VERSION 5.8 ;
BUSBITCHARS "[]" ;
DIVIDERCHAR "/" ;
UNITS
    DATABASE MICRONS 1000 ;
END UNITS

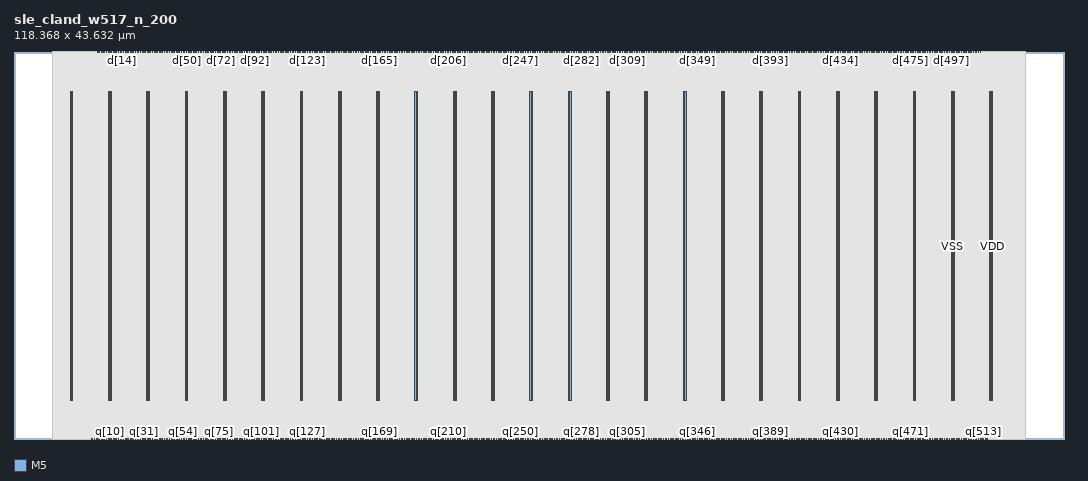
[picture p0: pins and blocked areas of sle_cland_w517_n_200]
MACRO sle_cland_w517_n_200
  FOREIGN sle_cland_w517_n_200 0 0 ;
  CLASS BLOCK ;
  SIZE 118.368 BY 43.632 ;
  PIN clk
    DIRECTION INPUT ;
    USE SIGNAL ;
    PORT
      LAYER M5 ;
        RECT  58.224 0 58.248 0.084 ;
    END
  END clk
  PIN d[0]
    DIRECTION INPUT ;
    USE SIGNAL ;
    PORT
      LAYER M5 ;
        RECT  9.84 43.548 9.864 43.632 ;
    END
  END d[0]
  PIN d[100]
    DIRECTION INPUT ;
    USE SIGNAL ;
    PORT
      LAYER M5 ;
        RECT  29.04 43.548 29.064 43.632 ;
    END
  END d[100]
  PIN d[101]
    DIRECTION INPUT ;
    USE SIGNAL ;
    PORT
      LAYER M5 ;
        RECT  28.656 43.548 28.68 43.632 ;
    END
  END d[101]
  PIN d[102]
    DIRECTION INPUT ;
    USE SIGNAL ;
    PORT
      LAYER M5 ;
        RECT  29.232 43.548 29.256 43.632 ;
    END
  END d[102]
  PIN d[103]
    DIRECTION INPUT ;
    USE SIGNAL ;
    PORT
      LAYER M5 ;
        RECT  28.848 43.548 28.872 43.632 ;
    END
  END d[103]
  PIN d[104]
    DIRECTION INPUT ;
    USE SIGNAL ;
    PORT
      LAYER M5 ;
        RECT  29.424 43.548 29.448 43.632 ;
    END
  END d[104]
  PIN d[105]
    DIRECTION INPUT ;
    USE SIGNAL ;
    PORT
      LAYER M5 ;
        RECT  29.616 43.548 29.64 43.632 ;
    END
  END d[105]
  PIN d[106]
    DIRECTION INPUT ;
    USE SIGNAL ;
    PORT
      LAYER M5 ;
        RECT  29.808 43.548 29.832 43.632 ;
    END
  END d[106]
  PIN d[107]
    DIRECTION INPUT ;
    USE SIGNAL ;
    PORT
      LAYER M5 ;
        RECT  30 43.548 30.024 43.632 ;
    END
  END d[107]
  PIN d[108]
    DIRECTION INPUT ;
    USE SIGNAL ;
    PORT
      LAYER M5 ;
        RECT  30.192 43.548 30.216 43.632 ;
    END
  END d[108]
  PIN d[109]
    DIRECTION INPUT ;
    USE SIGNAL ;
    PORT
      LAYER M5 ;
        RECT  30.384 43.548 30.408 43.632 ;
    END
  END d[109]
  PIN d[10]
    DIRECTION INPUT ;
    USE SIGNAL ;
    PORT
      LAYER M5 ;
        RECT  11.568 43.548 11.592 43.632 ;
    END
  END d[10]
  PIN d[110]
    DIRECTION INPUT ;
    USE SIGNAL ;
    PORT
      LAYER M5 ;
        RECT  30.576 43.548 30.6 43.632 ;
    END
  END d[110]
  PIN d[111]
    DIRECTION INPUT ;
    USE SIGNAL ;
    PORT
      LAYER M5 ;
        RECT  30.768 43.548 30.792 43.632 ;
    END
  END d[111]
  PIN d[112]
    DIRECTION INPUT ;
    USE SIGNAL ;
    PORT
      LAYER M5 ;
        RECT  30.96 43.548 30.984 43.632 ;
    END
  END d[112]
  PIN d[113]
    DIRECTION INPUT ;
    USE SIGNAL ;
    PORT
      LAYER M5 ;
        RECT  31.152 43.548 31.176 43.632 ;
    END
  END d[113]
  PIN d[114]
    DIRECTION INPUT ;
    USE SIGNAL ;
    PORT
      LAYER M5 ;
        RECT  31.344 43.548 31.368 43.632 ;
    END
  END d[114]
  PIN d[115]
    DIRECTION INPUT ;
    USE SIGNAL ;
    PORT
      LAYER M5 ;
        RECT  31.536 43.548 31.56 43.632 ;
    END
  END d[115]
  PIN d[116]
    DIRECTION INPUT ;
    USE SIGNAL ;
    PORT
      LAYER M5 ;
        RECT  31.728 43.548 31.752 43.632 ;
    END
  END d[116]
  PIN d[117]
    DIRECTION INPUT ;
    USE SIGNAL ;
    PORT
      LAYER M5 ;
        RECT  31.92 43.548 31.944 43.632 ;
    END
  END d[117]
  PIN d[118]
    DIRECTION INPUT ;
    USE SIGNAL ;
    PORT
      LAYER M5 ;
        RECT  32.112 43.548 32.136 43.632 ;
    END
  END d[118]
  PIN d[119]
    DIRECTION INPUT ;
    USE SIGNAL ;
    PORT
      LAYER M5 ;
        RECT  32.304 43.548 32.328 43.632 ;
    END
  END d[119]
  PIN d[11]
    DIRECTION INPUT ;
    USE SIGNAL ;
    PORT
      LAYER M5 ;
        RECT  11.376 43.548 11.4 43.632 ;
    END
  END d[11]
  PIN d[120]
    DIRECTION INPUT ;
    USE SIGNAL ;
    PORT
      LAYER M5 ;
        RECT  32.496 43.548 32.52 43.632 ;
    END
  END d[120]
  PIN d[121]
    DIRECTION INPUT ;
    USE SIGNAL ;
    PORT
      LAYER M5 ;
        RECT  32.688 43.548 32.712 43.632 ;
    END
  END d[121]
  PIN d[122]
    DIRECTION INPUT ;
    USE SIGNAL ;
    PORT
      LAYER M5 ;
        RECT  32.88 43.548 32.904 43.632 ;
    END
  END d[122]
  PIN d[123]
    DIRECTION INPUT ;
    USE SIGNAL ;
    PORT
      LAYER M5 ;
        RECT  33.072 43.548 33.096 43.632 ;
    END
  END d[123]
  PIN d[124]
    DIRECTION INPUT ;
    USE SIGNAL ;
    PORT
      LAYER M5 ;
        RECT  33.264 43.548 33.288 43.632 ;
    END
  END d[124]
  PIN d[125]
    DIRECTION INPUT ;
    USE SIGNAL ;
    PORT
      LAYER M5 ;
        RECT  33.456 43.548 33.48 43.632 ;
    END
  END d[125]
  PIN d[126]
    DIRECTION INPUT ;
    USE SIGNAL ;
    PORT
      LAYER M5 ;
        RECT  33.648 43.548 33.672 43.632 ;
    END
  END d[126]
  PIN d[127]
    DIRECTION INPUT ;
    USE SIGNAL ;
    PORT
      LAYER M5 ;
        RECT  33.84 43.548 33.864 43.632 ;
    END
  END d[127]
  PIN d[128]
    DIRECTION INPUT ;
    USE SIGNAL ;
    PORT
      LAYER M5 ;
        RECT  34.032 43.548 34.056 43.632 ;
    END
  END d[128]
  PIN d[129]
    DIRECTION INPUT ;
    USE SIGNAL ;
    PORT
      LAYER M5 ;
        RECT  34.224 43.548 34.248 43.632 ;
    END
  END d[129]
  PIN d[12]
    DIRECTION INPUT ;
    USE SIGNAL ;
    PORT
      LAYER M5 ;
        RECT  11.76 43.548 11.784 43.632 ;
    END
  END d[12]
  PIN d[130]
    DIRECTION INPUT ;
    USE SIGNAL ;
    PORT
      LAYER M5 ;
        RECT  34.416 43.548 34.44 43.632 ;
    END
  END d[130]
  PIN d[131]
    DIRECTION INPUT ;
    USE SIGNAL ;
    PORT
      LAYER M5 ;
        RECT  34.608 43.548 34.632 43.632 ;
    END
  END d[131]
  PIN d[132]
    DIRECTION INPUT ;
    USE SIGNAL ;
    PORT
      LAYER M5 ;
        RECT  34.8 43.548 34.824 43.632 ;
    END
  END d[132]
  PIN d[133]
    DIRECTION INPUT ;
    USE SIGNAL ;
    PORT
      LAYER M5 ;
        RECT  34.992 43.548 35.016 43.632 ;
    END
  END d[133]
  PIN d[134]
    DIRECTION INPUT ;
    USE SIGNAL ;
    PORT
      LAYER M5 ;
        RECT  35.184 43.548 35.208 43.632 ;
    END
  END d[134]
  PIN d[135]
    DIRECTION INPUT ;
    USE SIGNAL ;
    PORT
      LAYER M5 ;
        RECT  35.376 43.548 35.4 43.632 ;
    END
  END d[135]
  PIN d[136]
    DIRECTION INPUT ;
    USE SIGNAL ;
    PORT
      LAYER M5 ;
        RECT  35.76 43.548 35.784 43.632 ;
    END
  END d[136]
  PIN d[137]
    DIRECTION INPUT ;
    USE SIGNAL ;
    PORT
      LAYER M5 ;
        RECT  35.568 43.548 35.592 43.632 ;
    END
  END d[137]
  PIN d[138]
    DIRECTION INPUT ;
    USE SIGNAL ;
    PORT
      LAYER M5 ;
        RECT  35.952 43.548 35.976 43.632 ;
    END
  END d[138]
  PIN d[139]
    DIRECTION INPUT ;
    USE SIGNAL ;
    PORT
      LAYER M5 ;
        RECT  36.144 43.548 36.168 43.632 ;
    END
  END d[139]
  PIN d[13]
    DIRECTION INPUT ;
    USE SIGNAL ;
    PORT
      LAYER M5 ;
        RECT  11.952 43.548 11.976 43.632 ;
    END
  END d[13]
  PIN d[140]
    DIRECTION INPUT ;
    USE SIGNAL ;
    PORT
      LAYER M5 ;
        RECT  36.336 43.548 36.36 43.632 ;
    END
  END d[140]
  PIN d[141]
    DIRECTION INPUT ;
    USE SIGNAL ;
    PORT
      LAYER M5 ;
        RECT  36.528 43.548 36.552 43.632 ;
    END
  END d[141]
  PIN d[142]
    DIRECTION INPUT ;
    USE SIGNAL ;
    PORT
      LAYER M5 ;
        RECT  36.72 43.548 36.744 43.632 ;
    END
  END d[142]
  PIN d[143]
    DIRECTION INPUT ;
    USE SIGNAL ;
    PORT
      LAYER M5 ;
        RECT  36.912 43.548 36.936 43.632 ;
    END
  END d[143]
  PIN d[144]
    DIRECTION INPUT ;
    USE SIGNAL ;
    PORT
      LAYER M5 ;
        RECT  37.104 43.548 37.128 43.632 ;
    END
  END d[144]
  PIN d[145]
    DIRECTION INPUT ;
    USE SIGNAL ;
    PORT
      LAYER M5 ;
        RECT  37.296 43.548 37.32 43.632 ;
    END
  END d[145]
  PIN d[146]
    DIRECTION INPUT ;
    USE SIGNAL ;
    PORT
      LAYER M5 ;
        RECT  37.488 43.548 37.512 43.632 ;
    END
  END d[146]
  PIN d[147]
    DIRECTION INPUT ;
    USE SIGNAL ;
    PORT
      LAYER M5 ;
        RECT  37.872 43.548 37.896 43.632 ;
    END
  END d[147]
  PIN d[148]
    DIRECTION INPUT ;
    USE SIGNAL ;
    PORT
      LAYER M5 ;
        RECT  37.68 43.548 37.704 43.632 ;
    END
  END d[148]
  PIN d[149]
    DIRECTION INPUT ;
    USE SIGNAL ;
    PORT
      LAYER M5 ;
        RECT  38.064 43.548 38.088 43.632 ;
    END
  END d[149]
  PIN d[14]
    DIRECTION INPUT ;
    USE SIGNAL ;
    PORT
      LAYER M5 ;
        RECT  12.144 43.548 12.168 43.632 ;
    END
  END d[14]
  PIN d[150]
    DIRECTION INPUT ;
    USE SIGNAL ;
    PORT
      LAYER M5 ;
        RECT  38.64 43.548 38.664 43.632 ;
    END
  END d[150]
  PIN d[151]
    DIRECTION INPUT ;
    USE SIGNAL ;
    PORT
      LAYER M5 ;
        RECT  38.256 43.548 38.28 43.632 ;
    END
  END d[151]
  PIN d[152]
    DIRECTION INPUT ;
    USE SIGNAL ;
    PORT
      LAYER M5 ;
        RECT  38.832 43.548 38.856 43.632 ;
    END
  END d[152]
  PIN d[153]
    DIRECTION INPUT ;
    USE SIGNAL ;
    PORT
      LAYER M5 ;
        RECT  38.448 43.548 38.472 43.632 ;
    END
  END d[153]
  PIN d[154]
    DIRECTION INPUT ;
    USE SIGNAL ;
    PORT
      LAYER M5 ;
        RECT  39.024 43.548 39.048 43.632 ;
    END
  END d[154]
  PIN d[155]
    DIRECTION INPUT ;
    USE SIGNAL ;
    PORT
      LAYER M5 ;
        RECT  39.216 43.548 39.24 43.632 ;
    END
  END d[155]
  PIN d[156]
    DIRECTION INPUT ;
    USE SIGNAL ;
    PORT
      LAYER M5 ;
        RECT  39.408 43.548 39.432 43.632 ;
    END
  END d[156]
  PIN d[157]
    DIRECTION INPUT ;
    USE SIGNAL ;
    PORT
      LAYER M5 ;
        RECT  39.6 43.548 39.624 43.632 ;
    END
  END d[157]
  PIN d[158]
    DIRECTION INPUT ;
    USE SIGNAL ;
    PORT
      LAYER M5 ;
        RECT  39.792 43.548 39.816 43.632 ;
    END
  END d[158]
  PIN d[159]
    DIRECTION INPUT ;
    USE SIGNAL ;
    PORT
      LAYER M5 ;
        RECT  39.984 43.548 40.008 43.632 ;
    END
  END d[159]
  PIN d[15]
    DIRECTION INPUT ;
    USE SIGNAL ;
    PORT
      LAYER M5 ;
        RECT  12.336 43.548 12.36 43.632 ;
    END
  END d[15]
  PIN d[160]
    DIRECTION INPUT ;
    USE SIGNAL ;
    PORT
      LAYER M5 ;
        RECT  40.176 43.548 40.2 43.632 ;
    END
  END d[160]
  PIN d[161]
    DIRECTION INPUT ;
    USE SIGNAL ;
    PORT
      LAYER M5 ;
        RECT  40.368 43.548 40.392 43.632 ;
    END
  END d[161]
  PIN d[162]
    DIRECTION INPUT ;
    USE SIGNAL ;
    PORT
      LAYER M5 ;
        RECT  40.56 43.548 40.584 43.632 ;
    END
  END d[162]
  PIN d[163]
    DIRECTION INPUT ;
    USE SIGNAL ;
    PORT
      LAYER M5 ;
        RECT  40.752 43.548 40.776 43.632 ;
    END
  END d[163]
  PIN d[164]
    DIRECTION INPUT ;
    USE SIGNAL ;
    PORT
      LAYER M5 ;
        RECT  40.944 43.548 40.968 43.632 ;
    END
  END d[164]
  PIN d[165]
    DIRECTION INPUT ;
    USE SIGNAL ;
    PORT
      LAYER M5 ;
        RECT  41.136 43.548 41.16 43.632 ;
    END
  END d[165]
  PIN d[166]
    DIRECTION INPUT ;
    USE SIGNAL ;
    PORT
      LAYER M5 ;
        RECT  41.328 43.548 41.352 43.632 ;
    END
  END d[166]
  PIN d[167]
    DIRECTION INPUT ;
    USE SIGNAL ;
    PORT
      LAYER M5 ;
        RECT  41.52 43.548 41.544 43.632 ;
    END
  END d[167]
  PIN d[168]
    DIRECTION INPUT ;
    USE SIGNAL ;
    PORT
      LAYER M5 ;
        RECT  41.712 43.548 41.736 43.632 ;
    END
  END d[168]
  PIN d[169]
    DIRECTION INPUT ;
    USE SIGNAL ;
    PORT
      LAYER M5 ;
        RECT  41.904 43.548 41.928 43.632 ;
    END
  END d[169]
  PIN d[16]
    DIRECTION INPUT ;
    USE SIGNAL ;
    PORT
      LAYER M5 ;
        RECT  12.528 43.548 12.552 43.632 ;
    END
  END d[16]
  PIN d[170]
    DIRECTION INPUT ;
    USE SIGNAL ;
    PORT
      LAYER M5 ;
        RECT  42.096 43.548 42.12 43.632 ;
    END
  END d[170]
  PIN d[171]
    DIRECTION INPUT ;
    USE SIGNAL ;
    PORT
      LAYER M5 ;
        RECT  42.288 43.548 42.312 43.632 ;
    END
  END d[171]
  PIN d[172]
    DIRECTION INPUT ;
    USE SIGNAL ;
    PORT
      LAYER M5 ;
        RECT  42.48 43.548 42.504 43.632 ;
    END
  END d[172]
  PIN d[173]
    DIRECTION INPUT ;
    USE SIGNAL ;
    PORT
      LAYER M5 ;
        RECT  42.672 43.548 42.696 43.632 ;
    END
  END d[173]
  PIN d[174]
    DIRECTION INPUT ;
    USE SIGNAL ;
    PORT
      LAYER M5 ;
        RECT  42.864 43.548 42.888 43.632 ;
    END
  END d[174]
  PIN d[175]
    DIRECTION INPUT ;
    USE SIGNAL ;
    PORT
      LAYER M5 ;
        RECT  43.056 43.548 43.08 43.632 ;
    END
  END d[175]
  PIN d[176]
    DIRECTION INPUT ;
    USE SIGNAL ;
    PORT
      LAYER M5 ;
        RECT  43.248 43.548 43.272 43.632 ;
    END
  END d[176]
  PIN d[177]
    DIRECTION INPUT ;
    USE SIGNAL ;
    PORT
      LAYER M5 ;
        RECT  43.44 43.548 43.464 43.632 ;
    END
  END d[177]
  PIN d[178]
    DIRECTION INPUT ;
    USE SIGNAL ;
    PORT
      LAYER M5 ;
        RECT  43.632 43.548 43.656 43.632 ;
    END
  END d[178]
  PIN d[179]
    DIRECTION INPUT ;
    USE SIGNAL ;
    PORT
      LAYER M5 ;
        RECT  43.824 43.548 43.848 43.632 ;
    END
  END d[179]
  PIN d[17]
    DIRECTION INPUT ;
    USE SIGNAL ;
    PORT
      LAYER M5 ;
        RECT  12.72 43.548 12.744 43.632 ;
    END
  END d[17]
  PIN d[180]
    DIRECTION INPUT ;
    USE SIGNAL ;
    PORT
      LAYER M5 ;
        RECT  44.016 43.548 44.04 43.632 ;
    END
  END d[180]
  PIN d[181]
    DIRECTION INPUT ;
    USE SIGNAL ;
    PORT
      LAYER M5 ;
        RECT  44.208 43.548 44.232 43.632 ;
    END
  END d[181]
  PIN d[182]
    DIRECTION INPUT ;
    USE SIGNAL ;
    PORT
      LAYER M5 ;
        RECT  44.4 43.548 44.424 43.632 ;
    END
  END d[182]
  PIN d[183]
    DIRECTION INPUT ;
    USE SIGNAL ;
    PORT
      LAYER M5 ;
        RECT  44.592 43.548 44.616 43.632 ;
    END
  END d[183]
  PIN d[184]
    DIRECTION INPUT ;
    USE SIGNAL ;
    PORT
      LAYER M5 ;
        RECT  44.784 43.548 44.808 43.632 ;
    END
  END d[184]
  PIN d[185]
    DIRECTION INPUT ;
    USE SIGNAL ;
    PORT
      LAYER M5 ;
        RECT  44.976 43.548 45 43.632 ;
    END
  END d[185]
  PIN d[186]
    DIRECTION INPUT ;
    USE SIGNAL ;
    PORT
      LAYER M5 ;
        RECT  45.36 43.548 45.384 43.632 ;
    END
  END d[186]
  PIN d[187]
    DIRECTION INPUT ;
    USE SIGNAL ;
    PORT
      LAYER M5 ;
        RECT  45.168 43.548 45.192 43.632 ;
    END
  END d[187]
  PIN d[188]
    DIRECTION INPUT ;
    USE SIGNAL ;
    PORT
      LAYER M5 ;
        RECT  45.552 43.548 45.576 43.632 ;
    END
  END d[188]
  PIN d[189]
    DIRECTION INPUT ;
    USE SIGNAL ;
    PORT
      LAYER M5 ;
        RECT  45.744 43.548 45.768 43.632 ;
    END
  END d[189]
  PIN d[18]
    DIRECTION INPUT ;
    USE SIGNAL ;
    PORT
      LAYER M5 ;
        RECT  12.912 43.548 12.936 43.632 ;
    END
  END d[18]
  PIN d[190]
    DIRECTION INPUT ;
    USE SIGNAL ;
    PORT
      LAYER M5 ;
        RECT  45.936 43.548 45.96 43.632 ;
    END
  END d[190]
  PIN d[191]
    DIRECTION INPUT ;
    USE SIGNAL ;
    PORT
      LAYER M5 ;
        RECT  46.128 43.548 46.152 43.632 ;
    END
  END d[191]
  PIN d[192]
    DIRECTION INPUT ;
    USE SIGNAL ;
    PORT
      LAYER M5 ;
        RECT  46.32 43.548 46.344 43.632 ;
    END
  END d[192]
  PIN d[193]
    DIRECTION INPUT ;
    USE SIGNAL ;
    PORT
      LAYER M5 ;
        RECT  46.512 43.548 46.536 43.632 ;
    END
  END d[193]
  PIN d[194]
    DIRECTION INPUT ;
    USE SIGNAL ;
    PORT
      LAYER M5 ;
        RECT  46.704 43.548 46.728 43.632 ;
    END
  END d[194]
  PIN d[195]
    DIRECTION INPUT ;
    USE SIGNAL ;
    PORT
      LAYER M5 ;
        RECT  46.896 43.548 46.92 43.632 ;
    END
  END d[195]
  PIN d[196]
    DIRECTION INPUT ;
    USE SIGNAL ;
    PORT
      LAYER M5 ;
        RECT  47.088 43.548 47.112 43.632 ;
    END
  END d[196]
  PIN d[197]
    DIRECTION INPUT ;
    USE SIGNAL ;
    PORT
      LAYER M5 ;
        RECT  47.472 43.548 47.496 43.632 ;
    END
  END d[197]
  PIN d[198]
    DIRECTION INPUT ;
    USE SIGNAL ;
    PORT
      LAYER M5 ;
        RECT  47.28 43.548 47.304 43.632 ;
    END
  END d[198]
  PIN d[199]
    DIRECTION INPUT ;
    USE SIGNAL ;
    PORT
      LAYER M5 ;
        RECT  47.664 43.548 47.688 43.632 ;
    END
  END d[199]
  PIN d[19]
    DIRECTION INPUT ;
    USE SIGNAL ;
    PORT
      LAYER M5 ;
        RECT  13.104 43.548 13.128 43.632 ;
    END
  END d[19]
  PIN d[1]
    DIRECTION INPUT ;
    USE SIGNAL ;
    PORT
      LAYER M5 ;
        RECT  9.456 43.548 9.48 43.632 ;
    END
  END d[1]
  PIN d[200]
    DIRECTION INPUT ;
    USE SIGNAL ;
    PORT
      LAYER M5 ;
        RECT  48.24 43.548 48.264 43.632 ;
    END
  END d[200]
  PIN d[201]
    DIRECTION INPUT ;
    USE SIGNAL ;
    PORT
      LAYER M5 ;
        RECT  47.856 43.548 47.88 43.632 ;
    END
  END d[201]
  PIN d[202]
    DIRECTION INPUT ;
    USE SIGNAL ;
    PORT
      LAYER M5 ;
        RECT  48.432 43.548 48.456 43.632 ;
    END
  END d[202]
  PIN d[203]
    DIRECTION INPUT ;
    USE SIGNAL ;
    PORT
      LAYER M5 ;
        RECT  48.048 43.548 48.072 43.632 ;
    END
  END d[203]
  PIN d[204]
    DIRECTION INPUT ;
    USE SIGNAL ;
    PORT
      LAYER M5 ;
        RECT  48.624 43.548 48.648 43.632 ;
    END
  END d[204]
  PIN d[205]
    DIRECTION INPUT ;
    USE SIGNAL ;
    PORT
      LAYER M5 ;
        RECT  48.816 43.548 48.84 43.632 ;
    END
  END d[205]
  PIN d[206]
    DIRECTION INPUT ;
    USE SIGNAL ;
    PORT
      LAYER M5 ;
        RECT  49.008 43.548 49.032 43.632 ;
    END
  END d[206]
  PIN d[207]
    DIRECTION INPUT ;
    USE SIGNAL ;
    PORT
      LAYER M5 ;
        RECT  49.2 43.548 49.224 43.632 ;
    END
  END d[207]
  PIN d[208]
    DIRECTION INPUT ;
    USE SIGNAL ;
    PORT
      LAYER M5 ;
        RECT  49.392 43.548 49.416 43.632 ;
    END
  END d[208]
  PIN d[209]
    DIRECTION INPUT ;
    USE SIGNAL ;
    PORT
      LAYER M5 ;
        RECT  49.584 43.548 49.608 43.632 ;
    END
  END d[209]
  PIN d[20]
    DIRECTION INPUT ;
    USE SIGNAL ;
    PORT
      LAYER M5 ;
        RECT  13.296 43.548 13.32 43.632 ;
    END
  END d[20]
  PIN d[210]
    DIRECTION INPUT ;
    USE SIGNAL ;
    PORT
      LAYER M5 ;
        RECT  49.776 43.548 49.8 43.632 ;
    END
  END d[210]
  PIN d[211]
    DIRECTION INPUT ;
    USE SIGNAL ;
    PORT
      LAYER M5 ;
        RECT  49.968 43.548 49.992 43.632 ;
    END
  END d[211]
  PIN d[212]
    DIRECTION INPUT ;
    USE SIGNAL ;
    PORT
      LAYER M5 ;
        RECT  50.16 43.548 50.184 43.632 ;
    END
  END d[212]
  PIN d[213]
    DIRECTION INPUT ;
    USE SIGNAL ;
    PORT
      LAYER M5 ;
        RECT  50.352 43.548 50.376 43.632 ;
    END
  END d[213]
  PIN d[214]
    DIRECTION INPUT ;
    USE SIGNAL ;
    PORT
      LAYER M5 ;
        RECT  50.544 43.548 50.568 43.632 ;
    END
  END d[214]
  PIN d[215]
    DIRECTION INPUT ;
    USE SIGNAL ;
    PORT
      LAYER M5 ;
        RECT  50.736 43.548 50.76 43.632 ;
    END
  END d[215]
  PIN d[216]
    DIRECTION INPUT ;
    USE SIGNAL ;
    PORT
      LAYER M5 ;
        RECT  50.928 43.548 50.952 43.632 ;
    END
  END d[216]
  PIN d[217]
    DIRECTION INPUT ;
    USE SIGNAL ;
    PORT
      LAYER M5 ;
        RECT  51.12 43.548 51.144 43.632 ;
    END
  END d[217]
  PIN d[218]
    DIRECTION INPUT ;
    USE SIGNAL ;
    PORT
      LAYER M5 ;
        RECT  51.312 43.548 51.336 43.632 ;
    END
  END d[218]
  PIN d[219]
    DIRECTION INPUT ;
    USE SIGNAL ;
    PORT
      LAYER M5 ;
        RECT  51.504 43.548 51.528 43.632 ;
    END
  END d[219]
  PIN d[21]
    DIRECTION INPUT ;
    USE SIGNAL ;
    PORT
      LAYER M5 ;
        RECT  13.488 43.548 13.512 43.632 ;
    END
  END d[21]
  PIN d[220]
    DIRECTION INPUT ;
    USE SIGNAL ;
    PORT
      LAYER M5 ;
        RECT  51.696 43.548 51.72 43.632 ;
    END
  END d[220]
  PIN d[221]
    DIRECTION INPUT ;
    USE SIGNAL ;
    PORT
      LAYER M5 ;
        RECT  51.888 43.548 51.912 43.632 ;
    END
  END d[221]
  PIN d[222]
    DIRECTION INPUT ;
    USE SIGNAL ;
    PORT
      LAYER M5 ;
        RECT  52.08 43.548 52.104 43.632 ;
    END
  END d[222]
  PIN d[223]
    DIRECTION INPUT ;
    USE SIGNAL ;
    PORT
      LAYER M5 ;
        RECT  52.272 43.548 52.296 43.632 ;
    END
  END d[223]
  PIN d[224]
    DIRECTION INPUT ;
    USE SIGNAL ;
    PORT
      LAYER M5 ;
        RECT  52.464 43.548 52.488 43.632 ;
    END
  END d[224]
  PIN d[225]
    DIRECTION INPUT ;
    USE SIGNAL ;
    PORT
      LAYER M5 ;
        RECT  52.656 43.548 52.68 43.632 ;
    END
  END d[225]
  PIN d[226]
    DIRECTION INPUT ;
    USE SIGNAL ;
    PORT
      LAYER M5 ;
        RECT  52.848 43.548 52.872 43.632 ;
    END
  END d[226]
  PIN d[227]
    DIRECTION INPUT ;
    USE SIGNAL ;
    PORT
      LAYER M5 ;
        RECT  53.04 43.548 53.064 43.632 ;
    END
  END d[227]
  PIN d[228]
    DIRECTION INPUT ;
    USE SIGNAL ;
    PORT
      LAYER M5 ;
        RECT  53.232 43.548 53.256 43.632 ;
    END
  END d[228]
  PIN d[229]
    DIRECTION INPUT ;
    USE SIGNAL ;
    PORT
      LAYER M5 ;
        RECT  53.424 43.548 53.448 43.632 ;
    END
  END d[229]
  PIN d[22]
    DIRECTION INPUT ;
    USE SIGNAL ;
    PORT
      LAYER M5 ;
        RECT  13.872 43.548 13.896 43.632 ;
    END
  END d[22]
  PIN d[230]
    DIRECTION INPUT ;
    USE SIGNAL ;
    PORT
      LAYER M5 ;
        RECT  53.616 43.548 53.64 43.632 ;
    END
  END d[230]
  PIN d[231]
    DIRECTION INPUT ;
    USE SIGNAL ;
    PORT
      LAYER M5 ;
        RECT  53.808 43.548 53.832 43.632 ;
    END
  END d[231]
  PIN d[232]
    DIRECTION INPUT ;
    USE SIGNAL ;
    PORT
      LAYER M5 ;
        RECT  54 43.548 54.024 43.632 ;
    END
  END d[232]
  PIN d[233]
    DIRECTION INPUT ;
    USE SIGNAL ;
    PORT
      LAYER M5 ;
        RECT  54.192 43.548 54.216 43.632 ;
    END
  END d[233]
  PIN d[234]
    DIRECTION INPUT ;
    USE SIGNAL ;
    PORT
      LAYER M5 ;
        RECT  54.384 43.548 54.408 43.632 ;
    END
  END d[234]
  PIN d[235]
    DIRECTION INPUT ;
    USE SIGNAL ;
    PORT
      LAYER M5 ;
        RECT  54.576 43.548 54.6 43.632 ;
    END
  END d[235]
  PIN d[236]
    DIRECTION INPUT ;
    USE SIGNAL ;
    PORT
      LAYER M5 ;
        RECT  54.96 43.548 54.984 43.632 ;
    END
  END d[236]
  PIN d[237]
    DIRECTION INPUT ;
    USE SIGNAL ;
    PORT
      LAYER M5 ;
        RECT  54.768 43.548 54.792 43.632 ;
    END
  END d[237]
  PIN d[238]
    DIRECTION INPUT ;
    USE SIGNAL ;
    PORT
      LAYER M5 ;
        RECT  55.152 43.548 55.176 43.632 ;
    END
  END d[238]
  PIN d[239]
    DIRECTION INPUT ;
    USE SIGNAL ;
    PORT
      LAYER M5 ;
        RECT  55.344 43.548 55.368 43.632 ;
    END
  END d[239]
  PIN d[23]
    DIRECTION INPUT ;
    USE SIGNAL ;
    PORT
      LAYER M5 ;
        RECT  13.68 43.548 13.704 43.632 ;
    END
  END d[23]
  PIN d[240]
    DIRECTION INPUT ;
    USE SIGNAL ;
    PORT
      LAYER M5 ;
        RECT  55.536 43.548 55.56 43.632 ;
    END
  END d[240]
  PIN d[241]
    DIRECTION INPUT ;
    USE SIGNAL ;
    PORT
      LAYER M5 ;
        RECT  55.728 43.548 55.752 43.632 ;
    END
  END d[241]
  PIN d[242]
    DIRECTION INPUT ;
    USE SIGNAL ;
    PORT
      LAYER M5 ;
        RECT  55.92 43.548 55.944 43.632 ;
    END
  END d[242]
  PIN d[243]
    DIRECTION INPUT ;
    USE SIGNAL ;
    PORT
      LAYER M5 ;
        RECT  56.112 43.548 56.136 43.632 ;
    END
  END d[243]
  PIN d[244]
    DIRECTION INPUT ;
    USE SIGNAL ;
    PORT
      LAYER M5 ;
        RECT  56.304 43.548 56.328 43.632 ;
    END
  END d[244]
  PIN d[245]
    DIRECTION INPUT ;
    USE SIGNAL ;
    PORT
      LAYER M5 ;
        RECT  56.496 43.548 56.52 43.632 ;
    END
  END d[245]
  PIN d[246]
    DIRECTION INPUT ;
    USE SIGNAL ;
    PORT
      LAYER M5 ;
        RECT  56.688 43.548 56.712 43.632 ;
    END
  END d[246]
  PIN d[247]
    DIRECTION INPUT ;
    USE SIGNAL ;
    PORT
      LAYER M5 ;
        RECT  57.072 43.548 57.096 43.632 ;
    END
  END d[247]
  PIN d[248]
    DIRECTION INPUT ;
    USE SIGNAL ;
    PORT
      LAYER M5 ;
        RECT  56.88 43.548 56.904 43.632 ;
    END
  END d[248]
  PIN d[249]
    DIRECTION INPUT ;
    USE SIGNAL ;
    PORT
      LAYER M5 ;
        RECT  57.264 43.548 57.288 43.632 ;
    END
  END d[249]
  PIN d[24]
    DIRECTION INPUT ;
    USE SIGNAL ;
    PORT
      LAYER M5 ;
        RECT  14.064 43.548 14.088 43.632 ;
    END
  END d[24]
  PIN d[250]
    DIRECTION INPUT ;
    USE SIGNAL ;
    PORT
      LAYER M5 ;
        RECT  57.84 43.548 57.864 43.632 ;
    END
  END d[250]
  PIN d[251]
    DIRECTION INPUT ;
    USE SIGNAL ;
    PORT
      LAYER M5 ;
        RECT  57.456 43.548 57.48 43.632 ;
    END
  END d[251]
  PIN d[252]
    DIRECTION INPUT ;
    USE SIGNAL ;
    PORT
      LAYER M5 ;
        RECT  58.032 43.548 58.056 43.632 ;
    END
  END d[252]
  PIN d[253]
    DIRECTION INPUT ;
    USE SIGNAL ;
    PORT
      LAYER M5 ;
        RECT  57.648 43.548 57.672 43.632 ;
    END
  END d[253]
  PIN d[254]
    DIRECTION INPUT ;
    USE SIGNAL ;
    PORT
      LAYER M5 ;
        RECT  58.224 43.548 58.248 43.632 ;
    END
  END d[254]
  PIN d[255]
    DIRECTION INPUT ;
    USE SIGNAL ;
    PORT
      LAYER M5 ;
        RECT  58.416 43.548 58.44 43.632 ;
    END
  END d[255]
  PIN d[256]
    DIRECTION INPUT ;
    USE SIGNAL ;
    PORT
      LAYER M5 ;
        RECT  58.608 43.548 58.632 43.632 ;
    END
  END d[256]
  PIN d[257]
    DIRECTION INPUT ;
    USE SIGNAL ;
    PORT
      LAYER M5 ;
        RECT  58.8 43.548 58.824 43.632 ;
    END
  END d[257]
  PIN d[258]
    DIRECTION INPUT ;
    USE SIGNAL ;
    PORT
      LAYER M5 ;
        RECT  59.376 43.548 59.4 43.632 ;
    END
  END d[258]
  PIN d[259]
    DIRECTION INPUT ;
    USE SIGNAL ;
    PORT
      LAYER M5 ;
        RECT  59.568 43.548 59.592 43.632 ;
    END
  END d[259]
  PIN d[25]
    DIRECTION INPUT ;
    USE SIGNAL ;
    PORT
      LAYER M5 ;
        RECT  14.256 43.548 14.28 43.632 ;
    END
  END d[25]
  PIN d[260]
    DIRECTION INPUT ;
    USE SIGNAL ;
    PORT
      LAYER M5 ;
        RECT  59.76 43.548 59.784 43.632 ;
    END
  END d[260]
  PIN d[261]
    DIRECTION INPUT ;
    USE SIGNAL ;
    PORT
      LAYER M5 ;
        RECT  59.952 43.548 59.976 43.632 ;
    END
  END d[261]
  PIN d[262]
    DIRECTION INPUT ;
    USE SIGNAL ;
    PORT
      LAYER M5 ;
        RECT  60.144 43.548 60.168 43.632 ;
    END
  END d[262]
  PIN d[263]
    DIRECTION INPUT ;
    USE SIGNAL ;
    PORT
      LAYER M5 ;
        RECT  60.336 43.548 60.36 43.632 ;
    END
  END d[263]
  PIN d[264]
    DIRECTION INPUT ;
    USE SIGNAL ;
    PORT
      LAYER M5 ;
        RECT  60.528 43.548 60.552 43.632 ;
    END
  END d[264]
  PIN d[265]
    DIRECTION INPUT ;
    USE SIGNAL ;
    PORT
      LAYER M5 ;
        RECT  60.72 43.548 60.744 43.632 ;
    END
  END d[265]
  PIN d[266]
    DIRECTION INPUT ;
    USE SIGNAL ;
    PORT
      LAYER M5 ;
        RECT  60.912 43.548 60.936 43.632 ;
    END
  END d[266]
  PIN d[267]
    DIRECTION INPUT ;
    USE SIGNAL ;
    PORT
      LAYER M5 ;
        RECT  61.104 43.548 61.128 43.632 ;
    END
  END d[267]
  PIN d[268]
    DIRECTION INPUT ;
    USE SIGNAL ;
    PORT
      LAYER M5 ;
        RECT  61.296 43.548 61.32 43.632 ;
    END
  END d[268]
  PIN d[269]
    DIRECTION INPUT ;
    USE SIGNAL ;
    PORT
      LAYER M5 ;
        RECT  61.488 43.548 61.512 43.632 ;
    END
  END d[269]
  PIN d[26]
    DIRECTION INPUT ;
    USE SIGNAL ;
    PORT
      LAYER M5 ;
        RECT  14.448 43.548 14.472 43.632 ;
    END
  END d[26]
  PIN d[270]
    DIRECTION INPUT ;
    USE SIGNAL ;
    PORT
      LAYER M5 ;
        RECT  61.68 43.548 61.704 43.632 ;
    END
  END d[270]
  PIN d[271]
    DIRECTION INPUT ;
    USE SIGNAL ;
    PORT
      LAYER M5 ;
        RECT  61.872 43.548 61.896 43.632 ;
    END
  END d[271]
  PIN d[272]
    DIRECTION INPUT ;
    USE SIGNAL ;
    PORT
      LAYER M5 ;
        RECT  62.064 43.548 62.088 43.632 ;
    END
  END d[272]
  PIN d[273]
    DIRECTION INPUT ;
    USE SIGNAL ;
    PORT
      LAYER M5 ;
        RECT  62.256 43.548 62.28 43.632 ;
    END
  END d[273]
  PIN d[274]
    DIRECTION INPUT ;
    USE SIGNAL ;
    PORT
      LAYER M5 ;
        RECT  62.448 43.548 62.472 43.632 ;
    END
  END d[274]
  PIN d[275]
    DIRECTION INPUT ;
    USE SIGNAL ;
    PORT
      LAYER M5 ;
        RECT  62.64 43.548 62.664 43.632 ;
    END
  END d[275]
  PIN d[276]
    DIRECTION INPUT ;
    USE SIGNAL ;
    PORT
      LAYER M5 ;
        RECT  62.832 43.548 62.856 43.632 ;
    END
  END d[276]
  PIN d[277]
    DIRECTION INPUT ;
    USE SIGNAL ;
    PORT
      LAYER M5 ;
        RECT  63.024 43.548 63.048 43.632 ;
    END
  END d[277]
  PIN d[278]
    DIRECTION INPUT ;
    USE SIGNAL ;
    PORT
      LAYER M5 ;
        RECT  63.216 43.548 63.24 43.632 ;
    END
  END d[278]
  PIN d[279]
    DIRECTION INPUT ;
    USE SIGNAL ;
    PORT
      LAYER M5 ;
        RECT  63.408 43.548 63.432 43.632 ;
    END
  END d[279]
  PIN d[27]
    DIRECTION INPUT ;
    USE SIGNAL ;
    PORT
      LAYER M5 ;
        RECT  14.64 43.548 14.664 43.632 ;
    END
  END d[27]
  PIN d[280]
    DIRECTION INPUT ;
    USE SIGNAL ;
    PORT
      LAYER M5 ;
        RECT  63.6 43.548 63.624 43.632 ;
    END
  END d[280]
  PIN d[281]
    DIRECTION INPUT ;
    USE SIGNAL ;
    PORT
      LAYER M5 ;
        RECT  63.792 43.548 63.816 43.632 ;
    END
  END d[281]
  PIN d[282]
    DIRECTION INPUT ;
    USE SIGNAL ;
    PORT
      LAYER M5 ;
        RECT  63.984 43.548 64.008 43.632 ;
    END
  END d[282]
  PIN d[283]
    DIRECTION INPUT ;
    USE SIGNAL ;
    PORT
      LAYER M5 ;
        RECT  64.176 43.548 64.2 43.632 ;
    END
  END d[283]
  PIN d[284]
    DIRECTION INPUT ;
    USE SIGNAL ;
    PORT
      LAYER M5 ;
        RECT  64.368 43.548 64.392 43.632 ;
    END
  END d[284]
  PIN d[285]
    DIRECTION INPUT ;
    USE SIGNAL ;
    PORT
      LAYER M5 ;
        RECT  64.56 43.548 64.584 43.632 ;
    END
  END d[285]
  PIN d[286]
    DIRECTION INPUT ;
    USE SIGNAL ;
    PORT
      LAYER M5 ;
        RECT  64.752 43.548 64.776 43.632 ;
    END
  END d[286]
  PIN d[287]
    DIRECTION INPUT ;
    USE SIGNAL ;
    PORT
      LAYER M5 ;
        RECT  64.944 43.548 64.968 43.632 ;
    END
  END d[287]
  PIN d[288]
    DIRECTION INPUT ;
    USE SIGNAL ;
    PORT
      LAYER M5 ;
        RECT  65.136 43.548 65.16 43.632 ;
    END
  END d[288]
  PIN d[289]
    DIRECTION INPUT ;
    USE SIGNAL ;
    PORT
      LAYER M5 ;
        RECT  65.328 43.548 65.352 43.632 ;
    END
  END d[289]
  PIN d[28]
    DIRECTION INPUT ;
    USE SIGNAL ;
    PORT
      LAYER M5 ;
        RECT  14.832 43.548 14.856 43.632 ;
    END
  END d[28]
  PIN d[290]
    DIRECTION INPUT ;
    USE SIGNAL ;
    PORT
      LAYER M5 ;
        RECT  65.52 43.548 65.544 43.632 ;
    END
  END d[290]
  PIN d[291]
    DIRECTION INPUT ;
    USE SIGNAL ;
    PORT
      LAYER M5 ;
        RECT  65.712 43.548 65.736 43.632 ;
    END
  END d[291]
  PIN d[292]
    DIRECTION INPUT ;
    USE SIGNAL ;
    PORT
      LAYER M5 ;
        RECT  65.904 43.548 65.928 43.632 ;
    END
  END d[292]
  PIN d[293]
    DIRECTION INPUT ;
    USE SIGNAL ;
    PORT
      LAYER M5 ;
        RECT  66.096 43.548 66.12 43.632 ;
    END
  END d[293]
  PIN d[294]
    DIRECTION INPUT ;
    USE SIGNAL ;
    PORT
      LAYER M5 ;
        RECT  66.288 43.548 66.312 43.632 ;
    END
  END d[294]
  PIN d[295]
    DIRECTION INPUT ;
    USE SIGNAL ;
    PORT
      LAYER M5 ;
        RECT  66.48 43.548 66.504 43.632 ;
    END
  END d[295]
  PIN d[296]
    DIRECTION INPUT ;
    USE SIGNAL ;
    PORT
      LAYER M5 ;
        RECT  66.672 43.548 66.696 43.632 ;
    END
  END d[296]
  PIN d[297]
    DIRECTION INPUT ;
    USE SIGNAL ;
    PORT
      LAYER M5 ;
        RECT  67.248 43.548 67.272 43.632 ;
    END
  END d[297]
  PIN d[298]
    DIRECTION INPUT ;
    USE SIGNAL ;
    PORT
      LAYER M5 ;
        RECT  66.864 43.548 66.888 43.632 ;
    END
  END d[298]
  PIN d[299]
    DIRECTION INPUT ;
    USE SIGNAL ;
    PORT
      LAYER M5 ;
        RECT  67.44 43.548 67.464 43.632 ;
    END
  END d[299]
  PIN d[29]
    DIRECTION INPUT ;
    USE SIGNAL ;
    PORT
      LAYER M5 ;
        RECT  15.024 43.548 15.048 43.632 ;
    END
  END d[29]
  PIN d[2]
    DIRECTION INPUT ;
    USE SIGNAL ;
    PORT
      LAYER M5 ;
        RECT  10.032 43.548 10.056 43.632 ;
    END
  END d[2]
  PIN d[300]
    DIRECTION INPUT ;
    USE SIGNAL ;
    PORT
      LAYER M5 ;
        RECT  67.056 43.548 67.08 43.632 ;
    END
  END d[300]
  PIN d[301]
    DIRECTION INPUT ;
    USE SIGNAL ;
    PORT
      LAYER M5 ;
        RECT  67.632 43.548 67.656 43.632 ;
    END
  END d[301]
  PIN d[302]
    DIRECTION INPUT ;
    USE SIGNAL ;
    PORT
      LAYER M5 ;
        RECT  67.824 43.548 67.848 43.632 ;
    END
  END d[302]
  PIN d[303]
    DIRECTION INPUT ;
    USE SIGNAL ;
    PORT
      LAYER M5 ;
        RECT  68.016 43.548 68.04 43.632 ;
    END
  END d[303]
  PIN d[304]
    DIRECTION INPUT ;
    USE SIGNAL ;
    PORT
      LAYER M5 ;
        RECT  68.208 43.548 68.232 43.632 ;
    END
  END d[304]
  PIN d[305]
    DIRECTION INPUT ;
    USE SIGNAL ;
    PORT
      LAYER M5 ;
        RECT  68.4 43.548 68.424 43.632 ;
    END
  END d[305]
  PIN d[306]
    DIRECTION INPUT ;
    USE SIGNAL ;
    PORT
      LAYER M5 ;
        RECT  68.592 43.548 68.616 43.632 ;
    END
  END d[306]
  PIN d[307]
    DIRECTION INPUT ;
    USE SIGNAL ;
    PORT
      LAYER M5 ;
        RECT  68.784 43.548 68.808 43.632 ;
    END
  END d[307]
  PIN d[308]
    DIRECTION INPUT ;
    USE SIGNAL ;
    PORT
      LAYER M5 ;
        RECT  68.976 43.548 69 43.632 ;
    END
  END d[308]
  PIN d[309]
    DIRECTION INPUT ;
    USE SIGNAL ;
    PORT
      LAYER M5 ;
        RECT  69.168 43.548 69.192 43.632 ;
    END
  END d[309]
  PIN d[30]
    DIRECTION INPUT ;
    USE SIGNAL ;
    PORT
      LAYER M5 ;
        RECT  15.216 43.548 15.24 43.632 ;
    END
  END d[30]
  PIN d[310]
    DIRECTION INPUT ;
    USE SIGNAL ;
    PORT
      LAYER M5 ;
        RECT  69.36 43.548 69.384 43.632 ;
    END
  END d[310]
  PIN d[311]
    DIRECTION INPUT ;
    USE SIGNAL ;
    PORT
      LAYER M5 ;
        RECT  69.552 43.548 69.576 43.632 ;
    END
  END d[311]
  PIN d[312]
    DIRECTION INPUT ;
    USE SIGNAL ;
    PORT
      LAYER M5 ;
        RECT  69.744 43.548 69.768 43.632 ;
    END
  END d[312]
  PIN d[313]
    DIRECTION INPUT ;
    USE SIGNAL ;
    PORT
      LAYER M5 ;
        RECT  70.128 43.548 70.152 43.632 ;
    END
  END d[313]
  PIN d[314]
    DIRECTION INPUT ;
    USE SIGNAL ;
    PORT
      LAYER M5 ;
        RECT  69.936 43.548 69.96 43.632 ;
    END
  END d[314]
  PIN d[315]
    DIRECTION INPUT ;
    USE SIGNAL ;
    PORT
      LAYER M5 ;
        RECT  70.32 43.548 70.344 43.632 ;
    END
  END d[315]
  PIN d[316]
    DIRECTION INPUT ;
    USE SIGNAL ;
    PORT
      LAYER M5 ;
        RECT  70.512 43.548 70.536 43.632 ;
    END
  END d[316]
  PIN d[317]
    DIRECTION INPUT ;
    USE SIGNAL ;
    PORT
      LAYER M5 ;
        RECT  70.704 43.548 70.728 43.632 ;
    END
  END d[317]
  PIN d[318]
    DIRECTION INPUT ;
    USE SIGNAL ;
    PORT
      LAYER M5 ;
        RECT  70.896 43.548 70.92 43.632 ;
    END
  END d[318]
  PIN d[319]
    DIRECTION INPUT ;
    USE SIGNAL ;
    PORT
      LAYER M5 ;
        RECT  71.088 43.548 71.112 43.632 ;
    END
  END d[319]
  PIN d[31]
    DIRECTION INPUT ;
    USE SIGNAL ;
    PORT
      LAYER M5 ;
        RECT  15.408 43.548 15.432 43.632 ;
    END
  END d[31]
  PIN d[320]
    DIRECTION INPUT ;
    USE SIGNAL ;
    PORT
      LAYER M5 ;
        RECT  71.28 43.548 71.304 43.632 ;
    END
  END d[320]
  PIN d[321]
    DIRECTION INPUT ;
    USE SIGNAL ;
    PORT
      LAYER M5 ;
        RECT  71.472 43.548 71.496 43.632 ;
    END
  END d[321]
  PIN d[322]
    DIRECTION INPUT ;
    USE SIGNAL ;
    PORT
      LAYER M5 ;
        RECT  71.664 43.548 71.688 43.632 ;
    END
  END d[322]
  PIN d[323]
    DIRECTION INPUT ;
    USE SIGNAL ;
    PORT
      LAYER M5 ;
        RECT  71.856 43.548 71.88 43.632 ;
    END
  END d[323]
  PIN d[324]
    DIRECTION INPUT ;
    USE SIGNAL ;
    PORT
      LAYER M5 ;
        RECT  72.048 43.548 72.072 43.632 ;
    END
  END d[324]
  PIN d[325]
    DIRECTION INPUT ;
    USE SIGNAL ;
    PORT
      LAYER M5 ;
        RECT  72.24 43.548 72.264 43.632 ;
    END
  END d[325]
  PIN d[326]
    DIRECTION INPUT ;
    USE SIGNAL ;
    PORT
      LAYER M5 ;
        RECT  72.432 43.548 72.456 43.632 ;
    END
  END d[326]
  PIN d[327]
    DIRECTION INPUT ;
    USE SIGNAL ;
    PORT
      LAYER M5 ;
        RECT  72.624 43.548 72.648 43.632 ;
    END
  END d[327]
  PIN d[328]
    DIRECTION INPUT ;
    USE SIGNAL ;
    PORT
      LAYER M5 ;
        RECT  72.816 43.548 72.84 43.632 ;
    END
  END d[328]
  PIN d[329]
    DIRECTION INPUT ;
    USE SIGNAL ;
    PORT
      LAYER M5 ;
        RECT  73.008 43.548 73.032 43.632 ;
    END
  END d[329]
  PIN d[32]
    DIRECTION INPUT ;
    USE SIGNAL ;
    PORT
      LAYER M5 ;
        RECT  15.792 43.548 15.816 43.632 ;
    END
  END d[32]
  PIN d[330]
    DIRECTION INPUT ;
    USE SIGNAL ;
    PORT
      LAYER M5 ;
        RECT  73.2 43.548 73.224 43.632 ;
    END
  END d[330]
  PIN d[331]
    DIRECTION INPUT ;
    USE SIGNAL ;
    PORT
      LAYER M5 ;
        RECT  73.392 43.548 73.416 43.632 ;
    END
  END d[331]
  PIN d[332]
    DIRECTION INPUT ;
    USE SIGNAL ;
    PORT
      LAYER M5 ;
        RECT  73.584 43.548 73.608 43.632 ;
    END
  END d[332]
  PIN d[333]
    DIRECTION INPUT ;
    USE SIGNAL ;
    PORT
      LAYER M5 ;
        RECT  73.776 43.548 73.8 43.632 ;
    END
  END d[333]
  PIN d[334]
    DIRECTION INPUT ;
    USE SIGNAL ;
    PORT
      LAYER M5 ;
        RECT  73.968 43.548 73.992 43.632 ;
    END
  END d[334]
  PIN d[335]
    DIRECTION INPUT ;
    USE SIGNAL ;
    PORT
      LAYER M5 ;
        RECT  74.16 43.548 74.184 43.632 ;
    END
  END d[335]
  PIN d[336]
    DIRECTION INPUT ;
    USE SIGNAL ;
    PORT
      LAYER M5 ;
        RECT  74.352 43.548 74.376 43.632 ;
    END
  END d[336]
  PIN d[337]
    DIRECTION INPUT ;
    USE SIGNAL ;
    PORT
      LAYER M5 ;
        RECT  74.544 43.548 74.568 43.632 ;
    END
  END d[337]
  PIN d[338]
    DIRECTION INPUT ;
    USE SIGNAL ;
    PORT
      LAYER M5 ;
        RECT  74.736 43.548 74.76 43.632 ;
    END
  END d[338]
  PIN d[339]
    DIRECTION INPUT ;
    USE SIGNAL ;
    PORT
      LAYER M5 ;
        RECT  74.928 43.548 74.952 43.632 ;
    END
  END d[339]
  PIN d[33]
    DIRECTION INPUT ;
    USE SIGNAL ;
    PORT
      LAYER M5 ;
        RECT  15.6 43.548 15.624 43.632 ;
    END
  END d[33]
  PIN d[340]
    DIRECTION INPUT ;
    USE SIGNAL ;
    PORT
      LAYER M5 ;
        RECT  75.12 43.548 75.144 43.632 ;
    END
  END d[340]
  PIN d[341]
    DIRECTION INPUT ;
    USE SIGNAL ;
    PORT
      LAYER M5 ;
        RECT  75.312 43.548 75.336 43.632 ;
    END
  END d[341]
  PIN d[342]
    DIRECTION INPUT ;
    USE SIGNAL ;
    PORT
      LAYER M5 ;
        RECT  75.504 43.548 75.528 43.632 ;
    END
  END d[342]
  PIN d[343]
    DIRECTION INPUT ;
    USE SIGNAL ;
    PORT
      LAYER M5 ;
        RECT  75.696 43.548 75.72 43.632 ;
    END
  END d[343]
  PIN d[344]
    DIRECTION INPUT ;
    USE SIGNAL ;
    PORT
      LAYER M5 ;
        RECT  75.888 43.548 75.912 43.632 ;
    END
  END d[344]
  PIN d[345]
    DIRECTION INPUT ;
    USE SIGNAL ;
    PORT
      LAYER M5 ;
        RECT  76.08 43.548 76.104 43.632 ;
    END
  END d[345]
  PIN d[346]
    DIRECTION INPUT ;
    USE SIGNAL ;
    PORT
      LAYER M5 ;
        RECT  76.272 43.548 76.296 43.632 ;
    END
  END d[346]
  PIN d[347]
    DIRECTION INPUT ;
    USE SIGNAL ;
    PORT
      LAYER M5 ;
        RECT  76.848 43.548 76.872 43.632 ;
    END
  END d[347]
  PIN d[348]
    DIRECTION INPUT ;
    USE SIGNAL ;
    PORT
      LAYER M5 ;
        RECT  76.464 43.548 76.488 43.632 ;
    END
  END d[348]
  PIN d[349]
    DIRECTION INPUT ;
    USE SIGNAL ;
    PORT
      LAYER M5 ;
        RECT  77.04 43.548 77.064 43.632 ;
    END
  END d[349]
  PIN d[34]
    DIRECTION INPUT ;
    USE SIGNAL ;
    PORT
      LAYER M5 ;
        RECT  15.984 43.548 16.008 43.632 ;
    END
  END d[34]
  PIN d[350]
    DIRECTION INPUT ;
    USE SIGNAL ;
    PORT
      LAYER M5 ;
        RECT  76.656 43.548 76.68 43.632 ;
    END
  END d[350]
  PIN d[351]
    DIRECTION INPUT ;
    USE SIGNAL ;
    PORT
      LAYER M5 ;
        RECT  77.232 43.548 77.256 43.632 ;
    END
  END d[351]
  PIN d[352]
    DIRECTION INPUT ;
    USE SIGNAL ;
    PORT
      LAYER M5 ;
        RECT  77.424 43.548 77.448 43.632 ;
    END
  END d[352]
  PIN d[353]
    DIRECTION INPUT ;
    USE SIGNAL ;
    PORT
      LAYER M5 ;
        RECT  77.616 43.548 77.64 43.632 ;
    END
  END d[353]
  PIN d[354]
    DIRECTION INPUT ;
    USE SIGNAL ;
    PORT
      LAYER M5 ;
        RECT  77.808 43.548 77.832 43.632 ;
    END
  END d[354]
  PIN d[355]
    DIRECTION INPUT ;
    USE SIGNAL ;
    PORT
      LAYER M5 ;
        RECT  78 43.548 78.024 43.632 ;
    END
  END d[355]
  PIN d[356]
    DIRECTION INPUT ;
    USE SIGNAL ;
    PORT
      LAYER M5 ;
        RECT  78.192 43.548 78.216 43.632 ;
    END
  END d[356]
  PIN d[357]
    DIRECTION INPUT ;
    USE SIGNAL ;
    PORT
      LAYER M5 ;
        RECT  78.384 43.548 78.408 43.632 ;
    END
  END d[357]
  PIN d[358]
    DIRECTION INPUT ;
    USE SIGNAL ;
    PORT
      LAYER M5 ;
        RECT  78.576 43.548 78.6 43.632 ;
    END
  END d[358]
  PIN d[359]
    DIRECTION INPUT ;
    USE SIGNAL ;
    PORT
      LAYER M5 ;
        RECT  78.768 43.548 78.792 43.632 ;
    END
  END d[359]
  PIN d[35]
    DIRECTION INPUT ;
    USE SIGNAL ;
    PORT
      LAYER M5 ;
        RECT  16.176 43.548 16.2 43.632 ;
    END
  END d[35]
  PIN d[360]
    DIRECTION INPUT ;
    USE SIGNAL ;
    PORT
      LAYER M5 ;
        RECT  78.96 43.548 78.984 43.632 ;
    END
  END d[360]
  PIN d[361]
    DIRECTION INPUT ;
    USE SIGNAL ;
    PORT
      LAYER M5 ;
        RECT  79.152 43.548 79.176 43.632 ;
    END
  END d[361]
  PIN d[362]
    DIRECTION INPUT ;
    USE SIGNAL ;
    PORT
      LAYER M5 ;
        RECT  79.344 43.548 79.368 43.632 ;
    END
  END d[362]
  PIN d[363]
    DIRECTION INPUT ;
    USE SIGNAL ;
    PORT
      LAYER M5 ;
        RECT  79.728 43.548 79.752 43.632 ;
    END
  END d[363]
  PIN d[364]
    DIRECTION INPUT ;
    USE SIGNAL ;
    PORT
      LAYER M5 ;
        RECT  79.536 43.548 79.56 43.632 ;
    END
  END d[364]
  PIN d[365]
    DIRECTION INPUT ;
    USE SIGNAL ;
    PORT
      LAYER M5 ;
        RECT  79.92 43.548 79.944 43.632 ;
    END
  END d[365]
  PIN d[366]
    DIRECTION INPUT ;
    USE SIGNAL ;
    PORT
      LAYER M5 ;
        RECT  80.112 43.548 80.136 43.632 ;
    END
  END d[366]
  PIN d[367]
    DIRECTION INPUT ;
    USE SIGNAL ;
    PORT
      LAYER M5 ;
        RECT  80.304 43.548 80.328 43.632 ;
    END
  END d[367]
  PIN d[368]
    DIRECTION INPUT ;
    USE SIGNAL ;
    PORT
      LAYER M5 ;
        RECT  80.496 43.548 80.52 43.632 ;
    END
  END d[368]
  PIN d[369]
    DIRECTION INPUT ;
    USE SIGNAL ;
    PORT
      LAYER M5 ;
        RECT  80.688 43.548 80.712 43.632 ;
    END
  END d[369]
  PIN d[36]
    DIRECTION INPUT ;
    USE SIGNAL ;
    PORT
      LAYER M5 ;
        RECT  16.56 43.548 16.584 43.632 ;
    END
  END d[36]
  PIN d[370]
    DIRECTION INPUT ;
    USE SIGNAL ;
    PORT
      LAYER M5 ;
        RECT  80.88 43.548 80.904 43.632 ;
    END
  END d[370]
  PIN d[371]
    DIRECTION INPUT ;
    USE SIGNAL ;
    PORT
      LAYER M5 ;
        RECT  81.072 43.548 81.096 43.632 ;
    END
  END d[371]
  PIN d[372]
    DIRECTION INPUT ;
    USE SIGNAL ;
    PORT
      LAYER M5 ;
        RECT  81.264 43.548 81.288 43.632 ;
    END
  END d[372]
  PIN d[373]
    DIRECTION INPUT ;
    USE SIGNAL ;
    PORT
      LAYER M5 ;
        RECT  81.456 43.548 81.48 43.632 ;
    END
  END d[373]
  PIN d[374]
    DIRECTION INPUT ;
    USE SIGNAL ;
    PORT
      LAYER M5 ;
        RECT  81.648 43.548 81.672 43.632 ;
    END
  END d[374]
  PIN d[375]
    DIRECTION INPUT ;
    USE SIGNAL ;
    PORT
      LAYER M5 ;
        RECT  81.84 43.548 81.864 43.632 ;
    END
  END d[375]
  PIN d[376]
    DIRECTION INPUT ;
    USE SIGNAL ;
    PORT
      LAYER M5 ;
        RECT  82.032 43.548 82.056 43.632 ;
    END
  END d[376]
  PIN d[377]
    DIRECTION INPUT ;
    USE SIGNAL ;
    PORT
      LAYER M5 ;
        RECT  82.224 43.548 82.248 43.632 ;
    END
  END d[377]
  PIN d[378]
    DIRECTION INPUT ;
    USE SIGNAL ;
    PORT
      LAYER M5 ;
        RECT  82.416 43.548 82.44 43.632 ;
    END
  END d[378]
  PIN d[379]
    DIRECTION INPUT ;
    USE SIGNAL ;
    PORT
      LAYER M5 ;
        RECT  82.608 43.548 82.632 43.632 ;
    END
  END d[379]
  PIN d[37]
    DIRECTION INPUT ;
    USE SIGNAL ;
    PORT
      LAYER M5 ;
        RECT  16.368 43.548 16.392 43.632 ;
    END
  END d[37]
  PIN d[380]
    DIRECTION INPUT ;
    USE SIGNAL ;
    PORT
      LAYER M5 ;
        RECT  82.8 43.548 82.824 43.632 ;
    END
  END d[380]
  PIN d[381]
    DIRECTION INPUT ;
    USE SIGNAL ;
    PORT
      LAYER M5 ;
        RECT  82.992 43.548 83.016 43.632 ;
    END
  END d[381]
  PIN d[382]
    DIRECTION INPUT ;
    USE SIGNAL ;
    PORT
      LAYER M5 ;
        RECT  83.184 43.548 83.208 43.632 ;
    END
  END d[382]
  PIN d[383]
    DIRECTION INPUT ;
    USE SIGNAL ;
    PORT
      LAYER M5 ;
        RECT  83.376 43.548 83.4 43.632 ;
    END
  END d[383]
  PIN d[384]
    DIRECTION INPUT ;
    USE SIGNAL ;
    PORT
      LAYER M5 ;
        RECT  83.568 43.548 83.592 43.632 ;
    END
  END d[384]
  PIN d[385]
    DIRECTION INPUT ;
    USE SIGNAL ;
    PORT
      LAYER M5 ;
        RECT  83.76 43.548 83.784 43.632 ;
    END
  END d[385]
  PIN d[386]
    DIRECTION INPUT ;
    USE SIGNAL ;
    PORT
      LAYER M5 ;
        RECT  83.952 43.548 83.976 43.632 ;
    END
  END d[386]
  PIN d[387]
    DIRECTION INPUT ;
    USE SIGNAL ;
    PORT
      LAYER M5 ;
        RECT  84.144 43.548 84.168 43.632 ;
    END
  END d[387]
  PIN d[388]
    DIRECTION INPUT ;
    USE SIGNAL ;
    PORT
      LAYER M5 ;
        RECT  84.336 43.548 84.36 43.632 ;
    END
  END d[388]
  PIN d[389]
    DIRECTION INPUT ;
    USE SIGNAL ;
    PORT
      LAYER M5 ;
        RECT  84.528 43.548 84.552 43.632 ;
    END
  END d[389]
  PIN d[38]
    DIRECTION INPUT ;
    USE SIGNAL ;
    PORT
      LAYER M5 ;
        RECT  16.752 43.548 16.776 43.632 ;
    END
  END d[38]
  PIN d[390]
    DIRECTION INPUT ;
    USE SIGNAL ;
    PORT
      LAYER M5 ;
        RECT  84.72 43.548 84.744 43.632 ;
    END
  END d[390]
  PIN d[391]
    DIRECTION INPUT ;
    USE SIGNAL ;
    PORT
      LAYER M5 ;
        RECT  84.912 43.548 84.936 43.632 ;
    END
  END d[391]
  PIN d[392]
    DIRECTION INPUT ;
    USE SIGNAL ;
    PORT
      LAYER M5 ;
        RECT  85.104 43.548 85.128 43.632 ;
    END
  END d[392]
  PIN d[393]
    DIRECTION INPUT ;
    USE SIGNAL ;
    PORT
      LAYER M5 ;
        RECT  85.296 43.548 85.32 43.632 ;
    END
  END d[393]
  PIN d[394]
    DIRECTION INPUT ;
    USE SIGNAL ;
    PORT
      LAYER M5 ;
        RECT  85.488 43.548 85.512 43.632 ;
    END
  END d[394]
  PIN d[395]
    DIRECTION INPUT ;
    USE SIGNAL ;
    PORT
      LAYER M5 ;
        RECT  85.68 43.548 85.704 43.632 ;
    END
  END d[395]
  PIN d[396]
    DIRECTION INPUT ;
    USE SIGNAL ;
    PORT
      LAYER M5 ;
        RECT  85.872 43.548 85.896 43.632 ;
    END
  END d[396]
  PIN d[397]
    DIRECTION INPUT ;
    USE SIGNAL ;
    PORT
      LAYER M5 ;
        RECT  86.448 43.548 86.472 43.632 ;
    END
  END d[397]
  PIN d[398]
    DIRECTION INPUT ;
    USE SIGNAL ;
    PORT
      LAYER M5 ;
        RECT  86.064 43.548 86.088 43.632 ;
    END
  END d[398]
  PIN d[399]
    DIRECTION INPUT ;
    USE SIGNAL ;
    PORT
      LAYER M5 ;
        RECT  86.64 43.548 86.664 43.632 ;
    END
  END d[399]
  PIN d[39]
    DIRECTION INPUT ;
    USE SIGNAL ;
    PORT
      LAYER M5 ;
        RECT  16.944 43.548 16.968 43.632 ;
    END
  END d[39]
  PIN d[3]
    DIRECTION INPUT ;
    USE SIGNAL ;
    PORT
      LAYER M5 ;
        RECT  9.648 43.548 9.672 43.632 ;
    END
  END d[3]
  PIN d[400]
    DIRECTION INPUT ;
    USE SIGNAL ;
    PORT
      LAYER M5 ;
        RECT  86.256 43.548 86.28 43.632 ;
    END
  END d[400]
  PIN d[401]
    DIRECTION INPUT ;
    USE SIGNAL ;
    PORT
      LAYER M5 ;
        RECT  86.832 43.548 86.856 43.632 ;
    END
  END d[401]
  PIN d[402]
    DIRECTION INPUT ;
    USE SIGNAL ;
    PORT
      LAYER M5 ;
        RECT  87.024 43.548 87.048 43.632 ;
    END
  END d[402]
  PIN d[403]
    DIRECTION INPUT ;
    USE SIGNAL ;
    PORT
      LAYER M5 ;
        RECT  87.216 43.548 87.24 43.632 ;
    END
  END d[403]
  PIN d[404]
    DIRECTION INPUT ;
    USE SIGNAL ;
    PORT
      LAYER M5 ;
        RECT  87.408 43.548 87.432 43.632 ;
    END
  END d[404]
  PIN d[405]
    DIRECTION INPUT ;
    USE SIGNAL ;
    PORT
      LAYER M5 ;
        RECT  87.6 43.548 87.624 43.632 ;
    END
  END d[405]
  PIN d[406]
    DIRECTION INPUT ;
    USE SIGNAL ;
    PORT
      LAYER M5 ;
        RECT  87.792 43.548 87.816 43.632 ;
    END
  END d[406]
  PIN d[407]
    DIRECTION INPUT ;
    USE SIGNAL ;
    PORT
      LAYER M5 ;
        RECT  87.984 43.548 88.008 43.632 ;
    END
  END d[407]
  PIN d[408]
    DIRECTION INPUT ;
    USE SIGNAL ;
    PORT
      LAYER M5 ;
        RECT  88.176 43.548 88.2 43.632 ;
    END
  END d[408]
  PIN d[409]
    DIRECTION INPUT ;
    USE SIGNAL ;
    PORT
      LAYER M5 ;
        RECT  88.368 43.548 88.392 43.632 ;
    END
  END d[409]
  PIN d[40]
    DIRECTION INPUT ;
    USE SIGNAL ;
    PORT
      LAYER M5 ;
        RECT  17.136 43.548 17.16 43.632 ;
    END
  END d[40]
  PIN d[410]
    DIRECTION INPUT ;
    USE SIGNAL ;
    PORT
      LAYER M5 ;
        RECT  88.56 43.548 88.584 43.632 ;
    END
  END d[410]
  PIN d[411]
    DIRECTION INPUT ;
    USE SIGNAL ;
    PORT
      LAYER M5 ;
        RECT  88.752 43.548 88.776 43.632 ;
    END
  END d[411]
  PIN d[412]
    DIRECTION INPUT ;
    USE SIGNAL ;
    PORT
      LAYER M5 ;
        RECT  88.944 43.548 88.968 43.632 ;
    END
  END d[412]
  PIN d[413]
    DIRECTION INPUT ;
    USE SIGNAL ;
    PORT
      LAYER M5 ;
        RECT  89.328 43.548 89.352 43.632 ;
    END
  END d[413]
  PIN d[414]
    DIRECTION INPUT ;
    USE SIGNAL ;
    PORT
      LAYER M5 ;
        RECT  89.136 43.548 89.16 43.632 ;
    END
  END d[414]
  PIN d[415]
    DIRECTION INPUT ;
    USE SIGNAL ;
    PORT
      LAYER M5 ;
        RECT  89.52 43.548 89.544 43.632 ;
    END
  END d[415]
  PIN d[416]
    DIRECTION INPUT ;
    USE SIGNAL ;
    PORT
      LAYER M5 ;
        RECT  89.712 43.548 89.736 43.632 ;
    END
  END d[416]
  PIN d[417]
    DIRECTION INPUT ;
    USE SIGNAL ;
    PORT
      LAYER M5 ;
        RECT  89.904 43.548 89.928 43.632 ;
    END
  END d[417]
  PIN d[418]
    DIRECTION INPUT ;
    USE SIGNAL ;
    PORT
      LAYER M5 ;
        RECT  90.096 43.548 90.12 43.632 ;
    END
  END d[418]
  PIN d[419]
    DIRECTION INPUT ;
    USE SIGNAL ;
    PORT
      LAYER M5 ;
        RECT  90.288 43.548 90.312 43.632 ;
    END
  END d[419]
  PIN d[41]
    DIRECTION INPUT ;
    USE SIGNAL ;
    PORT
      LAYER M5 ;
        RECT  17.328 43.548 17.352 43.632 ;
    END
  END d[41]
  PIN d[420]
    DIRECTION INPUT ;
    USE SIGNAL ;
    PORT
      LAYER M5 ;
        RECT  90.48 43.548 90.504 43.632 ;
    END
  END d[420]
  PIN d[421]
    DIRECTION INPUT ;
    USE SIGNAL ;
    PORT
      LAYER M5 ;
        RECT  90.672 43.548 90.696 43.632 ;
    END
  END d[421]
  PIN d[422]
    DIRECTION INPUT ;
    USE SIGNAL ;
    PORT
      LAYER M5 ;
        RECT  90.864 43.548 90.888 43.632 ;
    END
  END d[422]
  PIN d[423]
    DIRECTION INPUT ;
    USE SIGNAL ;
    PORT
      LAYER M5 ;
        RECT  91.056 43.548 91.08 43.632 ;
    END
  END d[423]
  PIN d[424]
    DIRECTION INPUT ;
    USE SIGNAL ;
    PORT
      LAYER M5 ;
        RECT  91.248 43.548 91.272 43.632 ;
    END
  END d[424]
  PIN d[425]
    DIRECTION INPUT ;
    USE SIGNAL ;
    PORT
      LAYER M5 ;
        RECT  91.44 43.548 91.464 43.632 ;
    END
  END d[425]
  PIN d[426]
    DIRECTION INPUT ;
    USE SIGNAL ;
    PORT
      LAYER M5 ;
        RECT  91.632 43.548 91.656 43.632 ;
    END
  END d[426]
  PIN d[427]
    DIRECTION INPUT ;
    USE SIGNAL ;
    PORT
      LAYER M5 ;
        RECT  91.824 43.548 91.848 43.632 ;
    END
  END d[427]
  PIN d[428]
    DIRECTION INPUT ;
    USE SIGNAL ;
    PORT
      LAYER M5 ;
        RECT  92.016 43.548 92.04 43.632 ;
    END
  END d[428]
  PIN d[429]
    DIRECTION INPUT ;
    USE SIGNAL ;
    PORT
      LAYER M5 ;
        RECT  92.208 43.548 92.232 43.632 ;
    END
  END d[429]
  PIN d[42]
    DIRECTION INPUT ;
    USE SIGNAL ;
    PORT
      LAYER M5 ;
        RECT  17.712 43.548 17.736 43.632 ;
    END
  END d[42]
  PIN d[430]
    DIRECTION INPUT ;
    USE SIGNAL ;
    PORT
      LAYER M5 ;
        RECT  92.4 43.548 92.424 43.632 ;
    END
  END d[430]
  PIN d[431]
    DIRECTION INPUT ;
    USE SIGNAL ;
    PORT
      LAYER M5 ;
        RECT  92.592 43.548 92.616 43.632 ;
    END
  END d[431]
  PIN d[432]
    DIRECTION INPUT ;
    USE SIGNAL ;
    PORT
      LAYER M5 ;
        RECT  92.784 43.548 92.808 43.632 ;
    END
  END d[432]
  PIN d[433]
    DIRECTION INPUT ;
    USE SIGNAL ;
    PORT
      LAYER M5 ;
        RECT  92.976 43.548 93 43.632 ;
    END
  END d[433]
  PIN d[434]
    DIRECTION INPUT ;
    USE SIGNAL ;
    PORT
      LAYER M5 ;
        RECT  93.168 43.548 93.192 43.632 ;
    END
  END d[434]
  PIN d[435]
    DIRECTION INPUT ;
    USE SIGNAL ;
    PORT
      LAYER M5 ;
        RECT  93.36 43.548 93.384 43.632 ;
    END
  END d[435]
  PIN d[436]
    DIRECTION INPUT ;
    USE SIGNAL ;
    PORT
      LAYER M5 ;
        RECT  93.552 43.548 93.576 43.632 ;
    END
  END d[436]
  PIN d[437]
    DIRECTION INPUT ;
    USE SIGNAL ;
    PORT
      LAYER M5 ;
        RECT  93.744 43.548 93.768 43.632 ;
    END
  END d[437]
  PIN d[438]
    DIRECTION INPUT ;
    USE SIGNAL ;
    PORT
      LAYER M5 ;
        RECT  93.936 43.548 93.96 43.632 ;
    END
  END d[438]
  PIN d[439]
    DIRECTION INPUT ;
    USE SIGNAL ;
    PORT
      LAYER M5 ;
        RECT  94.128 43.548 94.152 43.632 ;
    END
  END d[439]
  PIN d[43]
    DIRECTION INPUT ;
    USE SIGNAL ;
    PORT
      LAYER M5 ;
        RECT  17.52 43.548 17.544 43.632 ;
    END
  END d[43]
  PIN d[440]
    DIRECTION INPUT ;
    USE SIGNAL ;
    PORT
      LAYER M5 ;
        RECT  94.32 43.548 94.344 43.632 ;
    END
  END d[440]
  PIN d[441]
    DIRECTION INPUT ;
    USE SIGNAL ;
    PORT
      LAYER M5 ;
        RECT  94.512 43.548 94.536 43.632 ;
    END
  END d[441]
  PIN d[442]
    DIRECTION INPUT ;
    USE SIGNAL ;
    PORT
      LAYER M5 ;
        RECT  94.704 43.548 94.728 43.632 ;
    END
  END d[442]
  PIN d[443]
    DIRECTION INPUT ;
    USE SIGNAL ;
    PORT
      LAYER M5 ;
        RECT  94.896 43.548 94.92 43.632 ;
    END
  END d[443]
  PIN d[444]
    DIRECTION INPUT ;
    USE SIGNAL ;
    PORT
      LAYER M5 ;
        RECT  95.088 43.548 95.112 43.632 ;
    END
  END d[444]
  PIN d[445]
    DIRECTION INPUT ;
    USE SIGNAL ;
    PORT
      LAYER M5 ;
        RECT  95.28 43.548 95.304 43.632 ;
    END
  END d[445]
  PIN d[446]
    DIRECTION INPUT ;
    USE SIGNAL ;
    PORT
      LAYER M5 ;
        RECT  95.472 43.548 95.496 43.632 ;
    END
  END d[446]
  PIN d[447]
    DIRECTION INPUT ;
    USE SIGNAL ;
    PORT
      LAYER M5 ;
        RECT  96.048 43.548 96.072 43.632 ;
    END
  END d[447]
  PIN d[448]
    DIRECTION INPUT ;
    USE SIGNAL ;
    PORT
      LAYER M5 ;
        RECT  95.664 43.548 95.688 43.632 ;
    END
  END d[448]
  PIN d[449]
    DIRECTION INPUT ;
    USE SIGNAL ;
    PORT
      LAYER M5 ;
        RECT  96.24 43.548 96.264 43.632 ;
    END
  END d[449]
  PIN d[44]
    DIRECTION INPUT ;
    USE SIGNAL ;
    PORT
      LAYER M5 ;
        RECT  17.904 43.548 17.928 43.632 ;
    END
  END d[44]
  PIN d[450]
    DIRECTION INPUT ;
    USE SIGNAL ;
    PORT
      LAYER M5 ;
        RECT  95.856 43.548 95.88 43.632 ;
    END
  END d[450]
  PIN d[451]
    DIRECTION INPUT ;
    USE SIGNAL ;
    PORT
      LAYER M5 ;
        RECT  96.432 43.548 96.456 43.632 ;
    END
  END d[451]
  PIN d[452]
    DIRECTION INPUT ;
    USE SIGNAL ;
    PORT
      LAYER M5 ;
        RECT  96.624 43.548 96.648 43.632 ;
    END
  END d[452]
  PIN d[453]
    DIRECTION INPUT ;
    USE SIGNAL ;
    PORT
      LAYER M5 ;
        RECT  96.816 43.548 96.84 43.632 ;
    END
  END d[453]
  PIN d[454]
    DIRECTION INPUT ;
    USE SIGNAL ;
    PORT
      LAYER M5 ;
        RECT  97.008 43.548 97.032 43.632 ;
    END
  END d[454]
  PIN d[455]
    DIRECTION INPUT ;
    USE SIGNAL ;
    PORT
      LAYER M5 ;
        RECT  97.2 43.548 97.224 43.632 ;
    END
  END d[455]
  PIN d[456]
    DIRECTION INPUT ;
    USE SIGNAL ;
    PORT
      LAYER M5 ;
        RECT  97.392 43.548 97.416 43.632 ;
    END
  END d[456]
  PIN d[457]
    DIRECTION INPUT ;
    USE SIGNAL ;
    PORT
      LAYER M5 ;
        RECT  97.584 43.548 97.608 43.632 ;
    END
  END d[457]
  PIN d[458]
    DIRECTION INPUT ;
    USE SIGNAL ;
    PORT
      LAYER M5 ;
        RECT  97.776 43.548 97.8 43.632 ;
    END
  END d[458]
  PIN d[459]
    DIRECTION INPUT ;
    USE SIGNAL ;
    PORT
      LAYER M5 ;
        RECT  97.968 43.548 97.992 43.632 ;
    END
  END d[459]
  PIN d[45]
    DIRECTION INPUT ;
    USE SIGNAL ;
    PORT
      LAYER M5 ;
        RECT  18.096 43.548 18.12 43.632 ;
    END
  END d[45]
  PIN d[460]
    DIRECTION INPUT ;
    USE SIGNAL ;
    PORT
      LAYER M5 ;
        RECT  98.16 43.548 98.184 43.632 ;
    END
  END d[460]
  PIN d[461]
    DIRECTION INPUT ;
    USE SIGNAL ;
    PORT
      LAYER M5 ;
        RECT  98.352 43.548 98.376 43.632 ;
    END
  END d[461]
  PIN d[462]
    DIRECTION INPUT ;
    USE SIGNAL ;
    PORT
      LAYER M5 ;
        RECT  98.544 43.548 98.568 43.632 ;
    END
  END d[462]
  PIN d[463]
    DIRECTION INPUT ;
    USE SIGNAL ;
    PORT
      LAYER M5 ;
        RECT  98.928 43.548 98.952 43.632 ;
    END
  END d[463]
  PIN d[464]
    DIRECTION INPUT ;
    USE SIGNAL ;
    PORT
      LAYER M5 ;
        RECT  98.736 43.548 98.76 43.632 ;
    END
  END d[464]
  PIN d[465]
    DIRECTION INPUT ;
    USE SIGNAL ;
    PORT
      LAYER M5 ;
        RECT  99.12 43.548 99.144 43.632 ;
    END
  END d[465]
  PIN d[466]
    DIRECTION INPUT ;
    USE SIGNAL ;
    PORT
      LAYER M5 ;
        RECT  99.312 43.548 99.336 43.632 ;
    END
  END d[466]
  PIN d[467]
    DIRECTION INPUT ;
    USE SIGNAL ;
    PORT
      LAYER M5 ;
        RECT  99.504 43.548 99.528 43.632 ;
    END
  END d[467]
  PIN d[468]
    DIRECTION INPUT ;
    USE SIGNAL ;
    PORT
      LAYER M5 ;
        RECT  99.696 43.548 99.72 43.632 ;
    END
  END d[468]
  PIN d[469]
    DIRECTION INPUT ;
    USE SIGNAL ;
    PORT
      LAYER M5 ;
        RECT  99.888 43.548 99.912 43.632 ;
    END
  END d[469]
  PIN d[46]
    DIRECTION INPUT ;
    USE SIGNAL ;
    PORT
      LAYER M5 ;
        RECT  18.288 43.548 18.312 43.632 ;
    END
  END d[46]
  PIN d[470]
    DIRECTION INPUT ;
    USE SIGNAL ;
    PORT
      LAYER M5 ;
        RECT  100.08 43.548 100.104 43.632 ;
    END
  END d[470]
  PIN d[471]
    DIRECTION INPUT ;
    USE SIGNAL ;
    PORT
      LAYER M5 ;
        RECT  100.272 43.548 100.296 43.632 ;
    END
  END d[471]
  PIN d[472]
    DIRECTION INPUT ;
    USE SIGNAL ;
    PORT
      LAYER M5 ;
        RECT  100.464 43.548 100.488 43.632 ;
    END
  END d[472]
  PIN d[473]
    DIRECTION INPUT ;
    USE SIGNAL ;
    PORT
      LAYER M5 ;
        RECT  100.656 43.548 100.68 43.632 ;
    END
  END d[473]
  PIN d[474]
    DIRECTION INPUT ;
    USE SIGNAL ;
    PORT
      LAYER M5 ;
        RECT  100.848 43.548 100.872 43.632 ;
    END
  END d[474]
  PIN d[475]
    DIRECTION INPUT ;
    USE SIGNAL ;
    PORT
      LAYER M5 ;
        RECT  101.04 43.548 101.064 43.632 ;
    END
  END d[475]
  PIN d[476]
    DIRECTION INPUT ;
    USE SIGNAL ;
    PORT
      LAYER M5 ;
        RECT  101.232 43.548 101.256 43.632 ;
    END
  END d[476]
  PIN d[477]
    DIRECTION INPUT ;
    USE SIGNAL ;
    PORT
      LAYER M5 ;
        RECT  101.424 43.548 101.448 43.632 ;
    END
  END d[477]
  PIN d[478]
    DIRECTION INPUT ;
    USE SIGNAL ;
    PORT
      LAYER M5 ;
        RECT  101.616 43.548 101.64 43.632 ;
    END
  END d[478]
  PIN d[479]
    DIRECTION INPUT ;
    USE SIGNAL ;
    PORT
      LAYER M5 ;
        RECT  101.808 43.548 101.832 43.632 ;
    END
  END d[479]
  PIN d[47]
    DIRECTION INPUT ;
    USE SIGNAL ;
    PORT
      LAYER M5 ;
        RECT  18.672 43.548 18.696 43.632 ;
    END
  END d[47]
  PIN d[480]
    DIRECTION INPUT ;
    USE SIGNAL ;
    PORT
      LAYER M5 ;
        RECT  102 43.548 102.024 43.632 ;
    END
  END d[480]
  PIN d[481]
    DIRECTION INPUT ;
    USE SIGNAL ;
    PORT
      LAYER M5 ;
        RECT  102.192 43.548 102.216 43.632 ;
    END
  END d[481]
  PIN d[482]
    DIRECTION INPUT ;
    USE SIGNAL ;
    PORT
      LAYER M5 ;
        RECT  102.384 43.548 102.408 43.632 ;
    END
  END d[482]
  PIN d[483]
    DIRECTION INPUT ;
    USE SIGNAL ;
    PORT
      LAYER M5 ;
        RECT  102.576 43.548 102.6 43.632 ;
    END
  END d[483]
  PIN d[484]
    DIRECTION INPUT ;
    USE SIGNAL ;
    PORT
      LAYER M5 ;
        RECT  102.768 43.548 102.792 43.632 ;
    END
  END d[484]
  PIN d[485]
    DIRECTION INPUT ;
    USE SIGNAL ;
    PORT
      LAYER M5 ;
        RECT  102.96 43.548 102.984 43.632 ;
    END
  END d[485]
  PIN d[486]
    DIRECTION INPUT ;
    USE SIGNAL ;
    PORT
      LAYER M5 ;
        RECT  103.152 43.548 103.176 43.632 ;
    END
  END d[486]
  PIN d[487]
    DIRECTION INPUT ;
    USE SIGNAL ;
    PORT
      LAYER M5 ;
        RECT  103.344 43.548 103.368 43.632 ;
    END
  END d[487]
  PIN d[488]
    DIRECTION INPUT ;
    USE SIGNAL ;
    PORT
      LAYER M5 ;
        RECT  103.536 43.548 103.56 43.632 ;
    END
  END d[488]
  PIN d[489]
    DIRECTION INPUT ;
    USE SIGNAL ;
    PORT
      LAYER M5 ;
        RECT  103.728 43.548 103.752 43.632 ;
    END
  END d[489]
  PIN d[48]
    DIRECTION INPUT ;
    USE SIGNAL ;
    PORT
      LAYER M5 ;
        RECT  18.48 43.548 18.504 43.632 ;
    END
  END d[48]
  PIN d[490]
    DIRECTION INPUT ;
    USE SIGNAL ;
    PORT
      LAYER M5 ;
        RECT  103.92 43.548 103.944 43.632 ;
    END
  END d[490]
  PIN d[491]
    DIRECTION INPUT ;
    USE SIGNAL ;
    PORT
      LAYER M5 ;
        RECT  104.112 43.548 104.136 43.632 ;
    END
  END d[491]
  PIN d[492]
    DIRECTION INPUT ;
    USE SIGNAL ;
    PORT
      LAYER M5 ;
        RECT  104.304 43.548 104.328 43.632 ;
    END
  END d[492]
  PIN d[493]
    DIRECTION INPUT ;
    USE SIGNAL ;
    PORT
      LAYER M5 ;
        RECT  104.496 43.548 104.52 43.632 ;
    END
  END d[493]
  PIN d[494]
    DIRECTION INPUT ;
    USE SIGNAL ;
    PORT
      LAYER M5 ;
        RECT  104.688 43.548 104.712 43.632 ;
    END
  END d[494]
  PIN d[495]
    DIRECTION INPUT ;
    USE SIGNAL ;
    PORT
      LAYER M5 ;
        RECT  104.88 43.548 104.904 43.632 ;
    END
  END d[495]
  PIN d[496]
    DIRECTION INPUT ;
    USE SIGNAL ;
    PORT
      LAYER M5 ;
        RECT  105.072 43.548 105.096 43.632 ;
    END
  END d[496]
  PIN d[497]
    DIRECTION INPUT ;
    USE SIGNAL ;
    PORT
      LAYER M5 ;
        RECT  105.648 43.548 105.672 43.632 ;
    END
  END d[497]
  PIN d[498]
    DIRECTION INPUT ;
    USE SIGNAL ;
    PORT
      LAYER M5 ;
        RECT  105.264 43.548 105.288 43.632 ;
    END
  END d[498]
  PIN d[499]
    DIRECTION INPUT ;
    USE SIGNAL ;
    PORT
      LAYER M5 ;
        RECT  105.84 43.548 105.864 43.632 ;
    END
  END d[499]
  PIN d[49]
    DIRECTION INPUT ;
    USE SIGNAL ;
    PORT
      LAYER M5 ;
        RECT  18.864 43.548 18.888 43.632 ;
    END
  END d[49]
  PIN d[4]
    DIRECTION INPUT ;
    USE SIGNAL ;
    PORT
      LAYER M5 ;
        RECT  10.224 43.548 10.248 43.632 ;
    END
  END d[4]
  PIN d[500]
    DIRECTION INPUT ;
    USE SIGNAL ;
    PORT
      LAYER M5 ;
        RECT  105.456 43.548 105.48 43.632 ;
    END
  END d[500]
  PIN d[501]
    DIRECTION INPUT ;
    USE SIGNAL ;
    PORT
      LAYER M5 ;
        RECT  106.032 43.548 106.056 43.632 ;
    END
  END d[501]
  PIN d[502]
    DIRECTION INPUT ;
    USE SIGNAL ;
    PORT
      LAYER M5 ;
        RECT  106.224 43.548 106.248 43.632 ;
    END
  END d[502]
  PIN d[503]
    DIRECTION INPUT ;
    USE SIGNAL ;
    PORT
      LAYER M5 ;
        RECT  106.416 43.548 106.44 43.632 ;
    END
  END d[503]
  PIN d[504]
    DIRECTION INPUT ;
    USE SIGNAL ;
    PORT
      LAYER M5 ;
        RECT  106.608 43.548 106.632 43.632 ;
    END
  END d[504]
  PIN d[505]
    DIRECTION INPUT ;
    USE SIGNAL ;
    PORT
      LAYER M5 ;
        RECT  106.8 43.548 106.824 43.632 ;
    END
  END d[505]
  PIN d[506]
    DIRECTION INPUT ;
    USE SIGNAL ;
    PORT
      LAYER M5 ;
        RECT  106.992 43.548 107.016 43.632 ;
    END
  END d[506]
  PIN d[507]
    DIRECTION INPUT ;
    USE SIGNAL ;
    PORT
      LAYER M5 ;
        RECT  107.376 43.548 107.4 43.632 ;
    END
  END d[507]
  PIN d[508]
    DIRECTION INPUT ;
    USE SIGNAL ;
    PORT
      LAYER M5 ;
        RECT  107.184 43.548 107.208 43.632 ;
    END
  END d[508]
  PIN d[509]
    DIRECTION INPUT ;
    USE SIGNAL ;
    PORT
      LAYER M5 ;
        RECT  107.568 43.548 107.592 43.632 ;
    END
  END d[509]
  PIN d[50]
    DIRECTION INPUT ;
    USE SIGNAL ;
    PORT
      LAYER M5 ;
        RECT  19.44 43.548 19.464 43.632 ;
    END
  END d[50]
  PIN d[510]
    DIRECTION INPUT ;
    USE SIGNAL ;
    PORT
      LAYER M5 ;
        RECT  107.76 43.548 107.784 43.632 ;
    END
  END d[510]
  PIN d[511]
    DIRECTION INPUT ;
    USE SIGNAL ;
    PORT
      LAYER M5 ;
        RECT  107.952 43.548 107.976 43.632 ;
    END
  END d[511]
  PIN d[512]
    DIRECTION INPUT ;
    USE SIGNAL ;
    PORT
      LAYER M5 ;
        RECT  108.144 43.548 108.168 43.632 ;
    END
  END d[512]
  PIN d[513]
    DIRECTION INPUT ;
    USE SIGNAL ;
    PORT
      LAYER M5 ;
        RECT  108.528 43.548 108.552 43.632 ;
    END
  END d[513]
  PIN d[514]
    DIRECTION INPUT ;
    USE SIGNAL ;
    PORT
      LAYER M5 ;
        RECT  108.336 43.548 108.36 43.632 ;
    END
  END d[514]
  PIN d[515]
    DIRECTION INPUT ;
    USE SIGNAL ;
    PORT
      LAYER M5 ;
        RECT  108.72 43.548 108.744 43.632 ;
    END
  END d[515]
  PIN d[516]
    DIRECTION INPUT ;
    USE SIGNAL ;
    PORT
      LAYER M5 ;
        RECT  108.912 43.548 108.936 43.632 ;
    END
  END d[516]
  PIN d[51]
    DIRECTION INPUT ;
    USE SIGNAL ;
    PORT
      LAYER M5 ;
        RECT  19.056 43.548 19.08 43.632 ;
    END
  END d[51]
  PIN d[52]
    DIRECTION INPUT ;
    USE SIGNAL ;
    PORT
      LAYER M5 ;
        RECT  19.632 43.548 19.656 43.632 ;
    END
  END d[52]
  PIN d[53]
    DIRECTION INPUT ;
    USE SIGNAL ;
    PORT
      LAYER M5 ;
        RECT  19.248 43.548 19.272 43.632 ;
    END
  END d[53]
  PIN d[54]
    DIRECTION INPUT ;
    USE SIGNAL ;
    PORT
      LAYER M5 ;
        RECT  19.824 43.548 19.848 43.632 ;
    END
  END d[54]
  PIN d[55]
    DIRECTION INPUT ;
    USE SIGNAL ;
    PORT
      LAYER M5 ;
        RECT  20.016 43.548 20.04 43.632 ;
    END
  END d[55]
  PIN d[56]
    DIRECTION INPUT ;
    USE SIGNAL ;
    PORT
      LAYER M5 ;
        RECT  20.208 43.548 20.232 43.632 ;
    END
  END d[56]
  PIN d[57]
    DIRECTION INPUT ;
    USE SIGNAL ;
    PORT
      LAYER M5 ;
        RECT  20.4 43.548 20.424 43.632 ;
    END
  END d[57]
  PIN d[58]
    DIRECTION INPUT ;
    USE SIGNAL ;
    PORT
      LAYER M5 ;
        RECT  20.592 43.548 20.616 43.632 ;
    END
  END d[58]
  PIN d[59]
    DIRECTION INPUT ;
    USE SIGNAL ;
    PORT
      LAYER M5 ;
        RECT  20.784 43.548 20.808 43.632 ;
    END
  END d[59]
  PIN d[5]
    DIRECTION INPUT ;
    USE SIGNAL ;
    PORT
      LAYER M5 ;
        RECT  10.416 43.548 10.44 43.632 ;
    END
  END d[5]
  PIN d[60]
    DIRECTION INPUT ;
    USE SIGNAL ;
    PORT
      LAYER M5 ;
        RECT  20.976 43.548 21 43.632 ;
    END
  END d[60]
  PIN d[61]
    DIRECTION INPUT ;
    USE SIGNAL ;
    PORT
      LAYER M5 ;
        RECT  21.168 43.548 21.192 43.632 ;
    END
  END d[61]
  PIN d[62]
    DIRECTION INPUT ;
    USE SIGNAL ;
    PORT
      LAYER M5 ;
        RECT  21.36 43.548 21.384 43.632 ;
    END
  END d[62]
  PIN d[63]
    DIRECTION INPUT ;
    USE SIGNAL ;
    PORT
      LAYER M5 ;
        RECT  21.552 43.548 21.576 43.632 ;
    END
  END d[63]
  PIN d[64]
    DIRECTION INPUT ;
    USE SIGNAL ;
    PORT
      LAYER M5 ;
        RECT  21.744 43.548 21.768 43.632 ;
    END
  END d[64]
  PIN d[65]
    DIRECTION INPUT ;
    USE SIGNAL ;
    PORT
      LAYER M5 ;
        RECT  21.936 43.548 21.96 43.632 ;
    END
  END d[65]
  PIN d[66]
    DIRECTION INPUT ;
    USE SIGNAL ;
    PORT
      LAYER M5 ;
        RECT  22.128 43.548 22.152 43.632 ;
    END
  END d[66]
  PIN d[67]
    DIRECTION INPUT ;
    USE SIGNAL ;
    PORT
      LAYER M5 ;
        RECT  22.32 43.548 22.344 43.632 ;
    END
  END d[67]
  PIN d[68]
    DIRECTION INPUT ;
    USE SIGNAL ;
    PORT
      LAYER M5 ;
        RECT  22.512 43.548 22.536 43.632 ;
    END
  END d[68]
  PIN d[69]
    DIRECTION INPUT ;
    USE SIGNAL ;
    PORT
      LAYER M5 ;
        RECT  22.704 43.548 22.728 43.632 ;
    END
  END d[69]
  PIN d[6]
    DIRECTION INPUT ;
    USE SIGNAL ;
    PORT
      LAYER M5 ;
        RECT  10.608 43.548 10.632 43.632 ;
    END
  END d[6]
  PIN d[70]
    DIRECTION INPUT ;
    USE SIGNAL ;
    PORT
      LAYER M5 ;
        RECT  22.896 43.548 22.92 43.632 ;
    END
  END d[70]
  PIN d[71]
    DIRECTION INPUT ;
    USE SIGNAL ;
    PORT
      LAYER M5 ;
        RECT  23.088 43.548 23.112 43.632 ;
    END
  END d[71]
  PIN d[72]
    DIRECTION INPUT ;
    USE SIGNAL ;
    PORT
      LAYER M5 ;
        RECT  23.28 43.548 23.304 43.632 ;
    END
  END d[72]
  PIN d[73]
    DIRECTION INPUT ;
    USE SIGNAL ;
    PORT
      LAYER M5 ;
        RECT  23.472 43.548 23.496 43.632 ;
    END
  END d[73]
  PIN d[74]
    DIRECTION INPUT ;
    USE SIGNAL ;
    PORT
      LAYER M5 ;
        RECT  23.664 43.548 23.688 43.632 ;
    END
  END d[74]
  PIN d[75]
    DIRECTION INPUT ;
    USE SIGNAL ;
    PORT
      LAYER M5 ;
        RECT  23.856 43.548 23.88 43.632 ;
    END
  END d[75]
  PIN d[76]
    DIRECTION INPUT ;
    USE SIGNAL ;
    PORT
      LAYER M5 ;
        RECT  24.048 43.548 24.072 43.632 ;
    END
  END d[76]
  PIN d[77]
    DIRECTION INPUT ;
    USE SIGNAL ;
    PORT
      LAYER M5 ;
        RECT  24.24 43.548 24.264 43.632 ;
    END
  END d[77]
  PIN d[78]
    DIRECTION INPUT ;
    USE SIGNAL ;
    PORT
      LAYER M5 ;
        RECT  24.432 43.548 24.456 43.632 ;
    END
  END d[78]
  PIN d[79]
    DIRECTION INPUT ;
    USE SIGNAL ;
    PORT
      LAYER M5 ;
        RECT  24.624 43.548 24.648 43.632 ;
    END
  END d[79]
  PIN d[7]
    DIRECTION INPUT ;
    USE SIGNAL ;
    PORT
      LAYER M5 ;
        RECT  10.8 43.548 10.824 43.632 ;
    END
  END d[7]
  PIN d[80]
    DIRECTION INPUT ;
    USE SIGNAL ;
    PORT
      LAYER M5 ;
        RECT  24.816 43.548 24.84 43.632 ;
    END
  END d[80]
  PIN d[81]
    DIRECTION INPUT ;
    USE SIGNAL ;
    PORT
      LAYER M5 ;
        RECT  25.008 43.548 25.032 43.632 ;
    END
  END d[81]
  PIN d[82]
    DIRECTION INPUT ;
    USE SIGNAL ;
    PORT
      LAYER M5 ;
        RECT  25.2 43.548 25.224 43.632 ;
    END
  END d[82]
  PIN d[83]
    DIRECTION INPUT ;
    USE SIGNAL ;
    PORT
      LAYER M5 ;
        RECT  25.392 43.548 25.416 43.632 ;
    END
  END d[83]
  PIN d[84]
    DIRECTION INPUT ;
    USE SIGNAL ;
    PORT
      LAYER M5 ;
        RECT  25.584 43.548 25.608 43.632 ;
    END
  END d[84]
  PIN d[85]
    DIRECTION INPUT ;
    USE SIGNAL ;
    PORT
      LAYER M5 ;
        RECT  25.776 43.548 25.8 43.632 ;
    END
  END d[85]
  PIN d[86]
    DIRECTION INPUT ;
    USE SIGNAL ;
    PORT
      LAYER M5 ;
        RECT  26.16 43.548 26.184 43.632 ;
    END
  END d[86]
  PIN d[87]
    DIRECTION INPUT ;
    USE SIGNAL ;
    PORT
      LAYER M5 ;
        RECT  25.968 43.548 25.992 43.632 ;
    END
  END d[87]
  PIN d[88]
    DIRECTION INPUT ;
    USE SIGNAL ;
    PORT
      LAYER M5 ;
        RECT  26.352 43.548 26.376 43.632 ;
    END
  END d[88]
  PIN d[89]
    DIRECTION INPUT ;
    USE SIGNAL ;
    PORT
      LAYER M5 ;
        RECT  26.544 43.548 26.568 43.632 ;
    END
  END d[89]
  PIN d[8]
    DIRECTION INPUT ;
    USE SIGNAL ;
    PORT
      LAYER M5 ;
        RECT  10.992 43.548 11.016 43.632 ;
    END
  END d[8]
  PIN d[90]
    DIRECTION INPUT ;
    USE SIGNAL ;
    PORT
      LAYER M5 ;
        RECT  26.736 43.548 26.76 43.632 ;
    END
  END d[90]
  PIN d[91]
    DIRECTION INPUT ;
    USE SIGNAL ;
    PORT
      LAYER M5 ;
        RECT  26.928 43.548 26.952 43.632 ;
    END
  END d[91]
  PIN d[92]
    DIRECTION INPUT ;
    USE SIGNAL ;
    PORT
      LAYER M5 ;
        RECT  27.12 43.548 27.144 43.632 ;
    END
  END d[92]
  PIN d[93]
    DIRECTION INPUT ;
    USE SIGNAL ;
    PORT
      LAYER M5 ;
        RECT  27.312 43.548 27.336 43.632 ;
    END
  END d[93]
  PIN d[94]
    DIRECTION INPUT ;
    USE SIGNAL ;
    PORT
      LAYER M5 ;
        RECT  27.504 43.548 27.528 43.632 ;
    END
  END d[94]
  PIN d[95]
    DIRECTION INPUT ;
    USE SIGNAL ;
    PORT
      LAYER M5 ;
        RECT  27.696 43.548 27.72 43.632 ;
    END
  END d[95]
  PIN d[96]
    DIRECTION INPUT ;
    USE SIGNAL ;
    PORT
      LAYER M5 ;
        RECT  27.888 43.548 27.912 43.632 ;
    END
  END d[96]
  PIN d[97]
    DIRECTION INPUT ;
    USE SIGNAL ;
    PORT
      LAYER M5 ;
        RECT  28.272 43.548 28.296 43.632 ;
    END
  END d[97]
  PIN d[98]
    DIRECTION INPUT ;
    USE SIGNAL ;
    PORT
      LAYER M5 ;
        RECT  28.08 43.548 28.104 43.632 ;
    END
  END d[98]
  PIN d[99]
    DIRECTION INPUT ;
    USE SIGNAL ;
    PORT
      LAYER M5 ;
        RECT  28.464 43.548 28.488 43.632 ;
    END
  END d[99]
  PIN d[9]
    DIRECTION INPUT ;
    USE SIGNAL ;
    PORT
      LAYER M5 ;
        RECT  11.184 43.548 11.208 43.632 ;
    END
  END d[9]
  PIN fault
    DIRECTION OUTPUT ;
    USE SIGNAL ;
    PORT
      LAYER M5 ;
        RECT  58.8 0 58.824 0.084 ;
    END
  END fault
  PIN fclk
    DIRECTION INPUT ;
    USE SIGNAL ;
    PORT
      LAYER M5 ;
        RECT  58.992 43.548 59.016 43.632 ;
    END
  END fclk
  PIN q[0]
    DIRECTION OUTPUT ;
    USE SIGNAL ;
    PORT
      LAYER M5 ;
        RECT  9.072 0 9.096 0.084 ;
    END
  END q[0]
  PIN q[100]
    DIRECTION OUTPUT ;
    USE SIGNAL ;
    PORT
      LAYER M5 ;
        RECT  28.272 0 28.296 0.084 ;
    END
  END q[100]
  PIN q[101]
    DIRECTION OUTPUT ;
    USE SIGNAL ;
    PORT
      LAYER M5 ;
        RECT  27.888 0 27.912 0.084 ;
    END
  END q[101]
  PIN q[102]
    DIRECTION OUTPUT ;
    USE SIGNAL ;
    PORT
      LAYER M5 ;
        RECT  28.464 0 28.488 0.084 ;
    END
  END q[102]
  PIN q[103]
    DIRECTION OUTPUT ;
    USE SIGNAL ;
    PORT
      LAYER M5 ;
        RECT  28.08 0 28.104 0.084 ;
    END
  END q[103]
  PIN q[104]
    DIRECTION OUTPUT ;
    USE SIGNAL ;
    PORT
      LAYER M5 ;
        RECT  28.656 0 28.68 0.084 ;
    END
  END q[104]
  PIN q[105]
    DIRECTION OUTPUT ;
    USE SIGNAL ;
    PORT
      LAYER M5 ;
        RECT  28.848 0 28.872 0.084 ;
    END
  END q[105]
  PIN q[106]
    DIRECTION OUTPUT ;
    USE SIGNAL ;
    PORT
      LAYER M5 ;
        RECT  29.04 0 29.064 0.084 ;
    END
  END q[106]
  PIN q[107]
    DIRECTION OUTPUT ;
    USE SIGNAL ;
    PORT
      LAYER M5 ;
        RECT  29.232 0 29.256 0.084 ;
    END
  END q[107]
  PIN q[108]
    DIRECTION OUTPUT ;
    USE SIGNAL ;
    PORT
      LAYER M5 ;
        RECT  29.424 0 29.448 0.084 ;
    END
  END q[108]
  PIN q[109]
    DIRECTION OUTPUT ;
    USE SIGNAL ;
    PORT
      LAYER M5 ;
        RECT  29.616 0 29.64 0.084 ;
    END
  END q[109]
  PIN q[10]
    DIRECTION OUTPUT ;
    USE SIGNAL ;
    PORT
      LAYER M5 ;
        RECT  10.8 0 10.824 0.084 ;
    END
  END q[10]
  PIN q[110]
    DIRECTION OUTPUT ;
    USE SIGNAL ;
    PORT
      LAYER M5 ;
        RECT  29.808 0 29.832 0.084 ;
    END
  END q[110]
  PIN q[111]
    DIRECTION OUTPUT ;
    USE SIGNAL ;
    PORT
      LAYER M5 ;
        RECT  30 0 30.024 0.084 ;
    END
  END q[111]
  PIN q[112]
    DIRECTION OUTPUT ;
    USE SIGNAL ;
    PORT
      LAYER M5 ;
        RECT  30.192 0 30.216 0.084 ;
    END
  END q[112]
  PIN q[113]
    DIRECTION OUTPUT ;
    USE SIGNAL ;
    PORT
      LAYER M5 ;
        RECT  30.384 0 30.408 0.084 ;
    END
  END q[113]
  PIN q[114]
    DIRECTION OUTPUT ;
    USE SIGNAL ;
    PORT
      LAYER M5 ;
        RECT  30.576 0 30.6 0.084 ;
    END
  END q[114]
  PIN q[115]
    DIRECTION OUTPUT ;
    USE SIGNAL ;
    PORT
      LAYER M5 ;
        RECT  30.768 0 30.792 0.084 ;
    END
  END q[115]
  PIN q[116]
    DIRECTION OUTPUT ;
    USE SIGNAL ;
    PORT
      LAYER M5 ;
        RECT  30.96 0 30.984 0.084 ;
    END
  END q[116]
  PIN q[117]
    DIRECTION OUTPUT ;
    USE SIGNAL ;
    PORT
      LAYER M5 ;
        RECT  31.152 0 31.176 0.084 ;
    END
  END q[117]
  PIN q[118]
    DIRECTION OUTPUT ;
    USE SIGNAL ;
    PORT
      LAYER M5 ;
        RECT  31.344 0 31.368 0.084 ;
    END
  END q[118]
  PIN q[119]
    DIRECTION OUTPUT ;
    USE SIGNAL ;
    PORT
      LAYER M5 ;
        RECT  31.536 0 31.56 0.084 ;
    END
  END q[119]
  PIN q[11]
    DIRECTION OUTPUT ;
    USE SIGNAL ;
    PORT
      LAYER M5 ;
        RECT  10.608 0 10.632 0.084 ;
    END
  END q[11]
  PIN q[120]
    DIRECTION OUTPUT ;
    USE SIGNAL ;
    PORT
      LAYER M5 ;
        RECT  31.728 0 31.752 0.084 ;
    END
  END q[120]
  PIN q[121]
    DIRECTION OUTPUT ;
    USE SIGNAL ;
    PORT
      LAYER M5 ;
        RECT  31.92 0 31.944 0.084 ;
    END
  END q[121]
  PIN q[122]
    DIRECTION OUTPUT ;
    USE SIGNAL ;
    PORT
      LAYER M5 ;
        RECT  32.112 0 32.136 0.084 ;
    END
  END q[122]
  PIN q[123]
    DIRECTION OUTPUT ;
    USE SIGNAL ;
    PORT
      LAYER M5 ;
        RECT  32.304 0 32.328 0.084 ;
    END
  END q[123]
  PIN q[124]
    DIRECTION OUTPUT ;
    USE SIGNAL ;
    PORT
      LAYER M5 ;
        RECT  32.496 0 32.52 0.084 ;
    END
  END q[124]
  PIN q[125]
    DIRECTION OUTPUT ;
    USE SIGNAL ;
    PORT
      LAYER M5 ;
        RECT  32.688 0 32.712 0.084 ;
    END
  END q[125]
  PIN q[126]
    DIRECTION OUTPUT ;
    USE SIGNAL ;
    PORT
      LAYER M5 ;
        RECT  32.88 0 32.904 0.084 ;
    END
  END q[126]
  PIN q[127]
    DIRECTION OUTPUT ;
    USE SIGNAL ;
    PORT
      LAYER M5 ;
        RECT  33.072 0 33.096 0.084 ;
    END
  END q[127]
  PIN q[128]
    DIRECTION OUTPUT ;
    USE SIGNAL ;
    PORT
      LAYER M5 ;
        RECT  33.264 0 33.288 0.084 ;
    END
  END q[128]
  PIN q[129]
    DIRECTION OUTPUT ;
    USE SIGNAL ;
    PORT
      LAYER M5 ;
        RECT  33.456 0 33.48 0.084 ;
    END
  END q[129]
  PIN q[12]
    DIRECTION OUTPUT ;
    USE SIGNAL ;
    PORT
      LAYER M5 ;
        RECT  10.992 0 11.016 0.084 ;
    END
  END q[12]
  PIN q[130]
    DIRECTION OUTPUT ;
    USE SIGNAL ;
    PORT
      LAYER M5 ;
        RECT  33.648 0 33.672 0.084 ;
    END
  END q[130]
  PIN q[131]
    DIRECTION OUTPUT ;
    USE SIGNAL ;
    PORT
      LAYER M5 ;
        RECT  33.84 0 33.864 0.084 ;
    END
  END q[131]
  PIN q[132]
    DIRECTION OUTPUT ;
    USE SIGNAL ;
    PORT
      LAYER M5 ;
        RECT  34.032 0 34.056 0.084 ;
    END
  END q[132]
  PIN q[133]
    DIRECTION OUTPUT ;
    USE SIGNAL ;
    PORT
      LAYER M5 ;
        RECT  34.224 0 34.248 0.084 ;
    END
  END q[133]
  PIN q[134]
    DIRECTION OUTPUT ;
    USE SIGNAL ;
    PORT
      LAYER M5 ;
        RECT  34.416 0 34.44 0.084 ;
    END
  END q[134]
  PIN q[135]
    DIRECTION OUTPUT ;
    USE SIGNAL ;
    PORT
      LAYER M5 ;
        RECT  34.608 0 34.632 0.084 ;
    END
  END q[135]
  PIN q[136]
    DIRECTION OUTPUT ;
    USE SIGNAL ;
    PORT
      LAYER M5 ;
        RECT  34.992 0 35.016 0.084 ;
    END
  END q[136]
  PIN q[137]
    DIRECTION OUTPUT ;
    USE SIGNAL ;
    PORT
      LAYER M5 ;
        RECT  34.8 0 34.824 0.084 ;
    END
  END q[137]
  PIN q[138]
    DIRECTION OUTPUT ;
    USE SIGNAL ;
    PORT
      LAYER M5 ;
        RECT  35.184 0 35.208 0.084 ;
    END
  END q[138]
  PIN q[139]
    DIRECTION OUTPUT ;
    USE SIGNAL ;
    PORT
      LAYER M5 ;
        RECT  35.376 0 35.4 0.084 ;
    END
  END q[139]
  PIN q[13]
    DIRECTION OUTPUT ;
    USE SIGNAL ;
    PORT
      LAYER M5 ;
        RECT  11.184 0 11.208 0.084 ;
    END
  END q[13]
  PIN q[140]
    DIRECTION OUTPUT ;
    USE SIGNAL ;
    PORT
      LAYER M5 ;
        RECT  35.568 0 35.592 0.084 ;
    END
  END q[140]
  PIN q[141]
    DIRECTION OUTPUT ;
    USE SIGNAL ;
    PORT
      LAYER M5 ;
        RECT  35.76 0 35.784 0.084 ;
    END
  END q[141]
  PIN q[142]
    DIRECTION OUTPUT ;
    USE SIGNAL ;
    PORT
      LAYER M5 ;
        RECT  35.952 0 35.976 0.084 ;
    END
  END q[142]
  PIN q[143]
    DIRECTION OUTPUT ;
    USE SIGNAL ;
    PORT
      LAYER M5 ;
        RECT  36.144 0 36.168 0.084 ;
    END
  END q[143]
  PIN q[144]
    DIRECTION OUTPUT ;
    USE SIGNAL ;
    PORT
      LAYER M5 ;
        RECT  36.336 0 36.36 0.084 ;
    END
  END q[144]
  PIN q[145]
    DIRECTION OUTPUT ;
    USE SIGNAL ;
    PORT
      LAYER M5 ;
        RECT  36.528 0 36.552 0.084 ;
    END
  END q[145]
  PIN q[146]
    DIRECTION OUTPUT ;
    USE SIGNAL ;
    PORT
      LAYER M5 ;
        RECT  36.72 0 36.744 0.084 ;
    END
  END q[146]
  PIN q[147]
    DIRECTION OUTPUT ;
    USE SIGNAL ;
    PORT
      LAYER M5 ;
        RECT  37.104 0 37.128 0.084 ;
    END
  END q[147]
  PIN q[148]
    DIRECTION OUTPUT ;
    USE SIGNAL ;
    PORT
      LAYER M5 ;
        RECT  36.912 0 36.936 0.084 ;
    END
  END q[148]
  PIN q[149]
    DIRECTION OUTPUT ;
    USE SIGNAL ;
    PORT
      LAYER M5 ;
        RECT  37.296 0 37.32 0.084 ;
    END
  END q[149]
  PIN q[14]
    DIRECTION OUTPUT ;
    USE SIGNAL ;
    PORT
      LAYER M5 ;
        RECT  11.376 0 11.4 0.084 ;
    END
  END q[14]
  PIN q[150]
    DIRECTION OUTPUT ;
    USE SIGNAL ;
    PORT
      LAYER M5 ;
        RECT  37.872 0 37.896 0.084 ;
    END
  END q[150]
  PIN q[151]
    DIRECTION OUTPUT ;
    USE SIGNAL ;
    PORT
      LAYER M5 ;
        RECT  37.488 0 37.512 0.084 ;
    END
  END q[151]
  PIN q[152]
    DIRECTION OUTPUT ;
    USE SIGNAL ;
    PORT
      LAYER M5 ;
        RECT  38.064 0 38.088 0.084 ;
    END
  END q[152]
  PIN q[153]
    DIRECTION OUTPUT ;
    USE SIGNAL ;
    PORT
      LAYER M5 ;
        RECT  37.68 0 37.704 0.084 ;
    END
  END q[153]
  PIN q[154]
    DIRECTION OUTPUT ;
    USE SIGNAL ;
    PORT
      LAYER M5 ;
        RECT  38.256 0 38.28 0.084 ;
    END
  END q[154]
  PIN q[155]
    DIRECTION OUTPUT ;
    USE SIGNAL ;
    PORT
      LAYER M5 ;
        RECT  38.448 0 38.472 0.084 ;
    END
  END q[155]
  PIN q[156]
    DIRECTION OUTPUT ;
    USE SIGNAL ;
    PORT
      LAYER M5 ;
        RECT  38.64 0 38.664 0.084 ;
    END
  END q[156]
  PIN q[157]
    DIRECTION OUTPUT ;
    USE SIGNAL ;
    PORT
      LAYER M5 ;
        RECT  38.832 0 38.856 0.084 ;
    END
  END q[157]
  PIN q[158]
    DIRECTION OUTPUT ;
    USE SIGNAL ;
    PORT
      LAYER M5 ;
        RECT  39.024 0 39.048 0.084 ;
    END
  END q[158]
  PIN q[159]
    DIRECTION OUTPUT ;
    USE SIGNAL ;
    PORT
      LAYER M5 ;
        RECT  39.216 0 39.24 0.084 ;
    END
  END q[159]
  PIN q[15]
    DIRECTION OUTPUT ;
    USE SIGNAL ;
    PORT
      LAYER M5 ;
        RECT  11.568 0 11.592 0.084 ;
    END
  END q[15]
  PIN q[160]
    DIRECTION OUTPUT ;
    USE SIGNAL ;
    PORT
      LAYER M5 ;
        RECT  39.408 0 39.432 0.084 ;
    END
  END q[160]
  PIN q[161]
    DIRECTION OUTPUT ;
    USE SIGNAL ;
    PORT
      LAYER M5 ;
        RECT  39.6 0 39.624 0.084 ;
    END
  END q[161]
  PIN q[162]
    DIRECTION OUTPUT ;
    USE SIGNAL ;
    PORT
      LAYER M5 ;
        RECT  39.792 0 39.816 0.084 ;
    END
  END q[162]
  PIN q[163]
    DIRECTION OUTPUT ;
    USE SIGNAL ;
    PORT
      LAYER M5 ;
        RECT  39.984 0 40.008 0.084 ;
    END
  END q[163]
  PIN q[164]
    DIRECTION OUTPUT ;
    USE SIGNAL ;
    PORT
      LAYER M5 ;
        RECT  40.176 0 40.2 0.084 ;
    END
  END q[164]
  PIN q[165]
    DIRECTION OUTPUT ;
    USE SIGNAL ;
    PORT
      LAYER M5 ;
        RECT  40.368 0 40.392 0.084 ;
    END
  END q[165]
  PIN q[166]
    DIRECTION OUTPUT ;
    USE SIGNAL ;
    PORT
      LAYER M5 ;
        RECT  40.56 0 40.584 0.084 ;
    END
  END q[166]
  PIN q[167]
    DIRECTION OUTPUT ;
    USE SIGNAL ;
    PORT
      LAYER M5 ;
        RECT  40.752 0 40.776 0.084 ;
    END
  END q[167]
  PIN q[168]
    DIRECTION OUTPUT ;
    USE SIGNAL ;
    PORT
      LAYER M5 ;
        RECT  40.944 0 40.968 0.084 ;
    END
  END q[168]
  PIN q[169]
    DIRECTION OUTPUT ;
    USE SIGNAL ;
    PORT
      LAYER M5 ;
        RECT  41.136 0 41.16 0.084 ;
    END
  END q[169]
  PIN q[16]
    DIRECTION OUTPUT ;
    USE SIGNAL ;
    PORT
      LAYER M5 ;
        RECT  11.76 0 11.784 0.084 ;
    END
  END q[16]
  PIN q[170]
    DIRECTION OUTPUT ;
    USE SIGNAL ;
    PORT
      LAYER M5 ;
        RECT  41.328 0 41.352 0.084 ;
    END
  END q[170]
  PIN q[171]
    DIRECTION OUTPUT ;
    USE SIGNAL ;
    PORT
      LAYER M5 ;
        RECT  41.52 0 41.544 0.084 ;
    END
  END q[171]
  PIN q[172]
    DIRECTION OUTPUT ;
    USE SIGNAL ;
    PORT
      LAYER M5 ;
        RECT  41.712 0 41.736 0.084 ;
    END
  END q[172]
  PIN q[173]
    DIRECTION OUTPUT ;
    USE SIGNAL ;
    PORT
      LAYER M5 ;
        RECT  41.904 0 41.928 0.084 ;
    END
  END q[173]
  PIN q[174]
    DIRECTION OUTPUT ;
    USE SIGNAL ;
    PORT
      LAYER M5 ;
        RECT  42.096 0 42.12 0.084 ;
    END
  END q[174]
  PIN q[175]
    DIRECTION OUTPUT ;
    USE SIGNAL ;
    PORT
      LAYER M5 ;
        RECT  42.288 0 42.312 0.084 ;
    END
  END q[175]
  PIN q[176]
    DIRECTION OUTPUT ;
    USE SIGNAL ;
    PORT
      LAYER M5 ;
        RECT  42.48 0 42.504 0.084 ;
    END
  END q[176]
  PIN q[177]
    DIRECTION OUTPUT ;
    USE SIGNAL ;
    PORT
      LAYER M5 ;
        RECT  42.672 0 42.696 0.084 ;
    END
  END q[177]
  PIN q[178]
    DIRECTION OUTPUT ;
    USE SIGNAL ;
    PORT
      LAYER M5 ;
        RECT  42.864 0 42.888 0.084 ;
    END
  END q[178]
  PIN q[179]
    DIRECTION OUTPUT ;
    USE SIGNAL ;
    PORT
      LAYER M5 ;
        RECT  43.056 0 43.08 0.084 ;
    END
  END q[179]
  PIN q[17]
    DIRECTION OUTPUT ;
    USE SIGNAL ;
    PORT
      LAYER M5 ;
        RECT  11.952 0 11.976 0.084 ;
    END
  END q[17]
  PIN q[180]
    DIRECTION OUTPUT ;
    USE SIGNAL ;
    PORT
      LAYER M5 ;
        RECT  43.248 0 43.272 0.084 ;
    END
  END q[180]
  PIN q[181]
    DIRECTION OUTPUT ;
    USE SIGNAL ;
    PORT
      LAYER M5 ;
        RECT  43.44 0 43.464 0.084 ;
    END
  END q[181]
  PIN q[182]
    DIRECTION OUTPUT ;
    USE SIGNAL ;
    PORT
      LAYER M5 ;
        RECT  43.632 0 43.656 0.084 ;
    END
  END q[182]
  PIN q[183]
    DIRECTION OUTPUT ;
    USE SIGNAL ;
    PORT
      LAYER M5 ;
        RECT  43.824 0 43.848 0.084 ;
    END
  END q[183]
  PIN q[184]
    DIRECTION OUTPUT ;
    USE SIGNAL ;
    PORT
      LAYER M5 ;
        RECT  44.016 0 44.04 0.084 ;
    END
  END q[184]
  PIN q[185]
    DIRECTION OUTPUT ;
    USE SIGNAL ;
    PORT
      LAYER M5 ;
        RECT  44.208 0 44.232 0.084 ;
    END
  END q[185]
  PIN q[186]
    DIRECTION OUTPUT ;
    USE SIGNAL ;
    PORT
      LAYER M5 ;
        RECT  44.592 0 44.616 0.084 ;
    END
  END q[186]
  PIN q[187]
    DIRECTION OUTPUT ;
    USE SIGNAL ;
    PORT
      LAYER M5 ;
        RECT  44.4 0 44.424 0.084 ;
    END
  END q[187]
  PIN q[188]
    DIRECTION OUTPUT ;
    USE SIGNAL ;
    PORT
      LAYER M5 ;
        RECT  44.784 0 44.808 0.084 ;
    END
  END q[188]
  PIN q[189]
    DIRECTION OUTPUT ;
    USE SIGNAL ;
    PORT
      LAYER M5 ;
        RECT  44.976 0 45 0.084 ;
    END
  END q[189]
  PIN q[18]
    DIRECTION OUTPUT ;
    USE SIGNAL ;
    PORT
      LAYER M5 ;
        RECT  12.144 0 12.168 0.084 ;
    END
  END q[18]
  PIN q[190]
    DIRECTION OUTPUT ;
    USE SIGNAL ;
    PORT
      LAYER M5 ;
        RECT  45.168 0 45.192 0.084 ;
    END
  END q[190]
  PIN q[191]
    DIRECTION OUTPUT ;
    USE SIGNAL ;
    PORT
      LAYER M5 ;
        RECT  45.36 0 45.384 0.084 ;
    END
  END q[191]
  PIN q[192]
    DIRECTION OUTPUT ;
    USE SIGNAL ;
    PORT
      LAYER M5 ;
        RECT  45.552 0 45.576 0.084 ;
    END
  END q[192]
  PIN q[193]
    DIRECTION OUTPUT ;
    USE SIGNAL ;
    PORT
      LAYER M5 ;
        RECT  45.744 0 45.768 0.084 ;
    END
  END q[193]
  PIN q[194]
    DIRECTION OUTPUT ;
    USE SIGNAL ;
    PORT
      LAYER M5 ;
        RECT  45.936 0 45.96 0.084 ;
    END
  END q[194]
  PIN q[195]
    DIRECTION OUTPUT ;
    USE SIGNAL ;
    PORT
      LAYER M5 ;
        RECT  46.128 0 46.152 0.084 ;
    END
  END q[195]
  PIN q[196]
    DIRECTION OUTPUT ;
    USE SIGNAL ;
    PORT
      LAYER M5 ;
        RECT  46.32 0 46.344 0.084 ;
    END
  END q[196]
  PIN q[197]
    DIRECTION OUTPUT ;
    USE SIGNAL ;
    PORT
      LAYER M5 ;
        RECT  46.704 0 46.728 0.084 ;
    END
  END q[197]
  PIN q[198]
    DIRECTION OUTPUT ;
    USE SIGNAL ;
    PORT
      LAYER M5 ;
        RECT  46.512 0 46.536 0.084 ;
    END
  END q[198]
  PIN q[199]
    DIRECTION OUTPUT ;
    USE SIGNAL ;
    PORT
      LAYER M5 ;
        RECT  46.896 0 46.92 0.084 ;
    END
  END q[199]
  PIN q[19]
    DIRECTION OUTPUT ;
    USE SIGNAL ;
    PORT
      LAYER M5 ;
        RECT  12.336 0 12.36 0.084 ;
    END
  END q[19]
  PIN q[1]
    DIRECTION OUTPUT ;
    USE SIGNAL ;
    PORT
      LAYER M5 ;
        RECT  8.688 0 8.712 0.084 ;
    END
  END q[1]
  PIN q[200]
    DIRECTION OUTPUT ;
    USE SIGNAL ;
    PORT
      LAYER M5 ;
        RECT  47.472 0 47.496 0.084 ;
    END
  END q[200]
  PIN q[201]
    DIRECTION OUTPUT ;
    USE SIGNAL ;
    PORT
      LAYER M5 ;
        RECT  47.088 0 47.112 0.084 ;
    END
  END q[201]
  PIN q[202]
    DIRECTION OUTPUT ;
    USE SIGNAL ;
    PORT
      LAYER M5 ;
        RECT  47.664 0 47.688 0.084 ;
    END
  END q[202]
  PIN q[203]
    DIRECTION OUTPUT ;
    USE SIGNAL ;
    PORT
      LAYER M5 ;
        RECT  47.28 0 47.304 0.084 ;
    END
  END q[203]
  PIN q[204]
    DIRECTION OUTPUT ;
    USE SIGNAL ;
    PORT
      LAYER M5 ;
        RECT  47.856 0 47.88 0.084 ;
    END
  END q[204]
  PIN q[205]
    DIRECTION OUTPUT ;
    USE SIGNAL ;
    PORT
      LAYER M5 ;
        RECT  48.048 0 48.072 0.084 ;
    END
  END q[205]
  PIN q[206]
    DIRECTION OUTPUT ;
    USE SIGNAL ;
    PORT
      LAYER M5 ;
        RECT  48.24 0 48.264 0.084 ;
    END
  END q[206]
  PIN q[207]
    DIRECTION OUTPUT ;
    USE SIGNAL ;
    PORT
      LAYER M5 ;
        RECT  48.432 0 48.456 0.084 ;
    END
  END q[207]
  PIN q[208]
    DIRECTION OUTPUT ;
    USE SIGNAL ;
    PORT
      LAYER M5 ;
        RECT  48.624 0 48.648 0.084 ;
    END
  END q[208]
  PIN q[209]
    DIRECTION OUTPUT ;
    USE SIGNAL ;
    PORT
      LAYER M5 ;
        RECT  48.816 0 48.84 0.084 ;
    END
  END q[209]
  PIN q[20]
    DIRECTION OUTPUT ;
    USE SIGNAL ;
    PORT
      LAYER M5 ;
        RECT  12.528 0 12.552 0.084 ;
    END
  END q[20]
  PIN q[210]
    DIRECTION OUTPUT ;
    USE SIGNAL ;
    PORT
      LAYER M5 ;
        RECT  49.008 0 49.032 0.084 ;
    END
  END q[210]
  PIN q[211]
    DIRECTION OUTPUT ;
    USE SIGNAL ;
    PORT
      LAYER M5 ;
        RECT  49.2 0 49.224 0.084 ;
    END
  END q[211]
  PIN q[212]
    DIRECTION OUTPUT ;
    USE SIGNAL ;
    PORT
      LAYER M5 ;
        RECT  49.392 0 49.416 0.084 ;
    END
  END q[212]
  PIN q[213]
    DIRECTION OUTPUT ;
    USE SIGNAL ;
    PORT
      LAYER M5 ;
        RECT  49.584 0 49.608 0.084 ;
    END
  END q[213]
  PIN q[214]
    DIRECTION OUTPUT ;
    USE SIGNAL ;
    PORT
      LAYER M5 ;
        RECT  49.776 0 49.8 0.084 ;
    END
  END q[214]
  PIN q[215]
    DIRECTION OUTPUT ;
    USE SIGNAL ;
    PORT
      LAYER M5 ;
        RECT  49.968 0 49.992 0.084 ;
    END
  END q[215]
  PIN q[216]
    DIRECTION OUTPUT ;
    USE SIGNAL ;
    PORT
      LAYER M5 ;
        RECT  50.16 0 50.184 0.084 ;
    END
  END q[216]
  PIN q[217]
    DIRECTION OUTPUT ;
    USE SIGNAL ;
    PORT
      LAYER M5 ;
        RECT  50.352 0 50.376 0.084 ;
    END
  END q[217]
  PIN q[218]
    DIRECTION OUTPUT ;
    USE SIGNAL ;
    PORT
      LAYER M5 ;
        RECT  50.544 0 50.568 0.084 ;
    END
  END q[218]
  PIN q[219]
    DIRECTION OUTPUT ;
    USE SIGNAL ;
    PORT
      LAYER M5 ;
        RECT  50.736 0 50.76 0.084 ;
    END
  END q[219]
  PIN q[21]
    DIRECTION OUTPUT ;
    USE SIGNAL ;
    PORT
      LAYER M5 ;
        RECT  12.72 0 12.744 0.084 ;
    END
  END q[21]
  PIN q[220]
    DIRECTION OUTPUT ;
    USE SIGNAL ;
    PORT
      LAYER M5 ;
        RECT  50.928 0 50.952 0.084 ;
    END
  END q[220]
  PIN q[221]
    DIRECTION OUTPUT ;
    USE SIGNAL ;
    PORT
      LAYER M5 ;
        RECT  51.12 0 51.144 0.084 ;
    END
  END q[221]
  PIN q[222]
    DIRECTION OUTPUT ;
    USE SIGNAL ;
    PORT
      LAYER M5 ;
        RECT  51.312 0 51.336 0.084 ;
    END
  END q[222]
  PIN q[223]
    DIRECTION OUTPUT ;
    USE SIGNAL ;
    PORT
      LAYER M5 ;
        RECT  51.504 0 51.528 0.084 ;
    END
  END q[223]
  PIN q[224]
    DIRECTION OUTPUT ;
    USE SIGNAL ;
    PORT
      LAYER M5 ;
        RECT  51.696 0 51.72 0.084 ;
    END
  END q[224]
  PIN q[225]
    DIRECTION OUTPUT ;
    USE SIGNAL ;
    PORT
      LAYER M5 ;
        RECT  51.888 0 51.912 0.084 ;
    END
  END q[225]
  PIN q[226]
    DIRECTION OUTPUT ;
    USE SIGNAL ;
    PORT
      LAYER M5 ;
        RECT  52.08 0 52.104 0.084 ;
    END
  END q[226]
  PIN q[227]
    DIRECTION OUTPUT ;
    USE SIGNAL ;
    PORT
      LAYER M5 ;
        RECT  52.272 0 52.296 0.084 ;
    END
  END q[227]
  PIN q[228]
    DIRECTION OUTPUT ;
    USE SIGNAL ;
    PORT
      LAYER M5 ;
        RECT  52.464 0 52.488 0.084 ;
    END
  END q[228]
  PIN q[229]
    DIRECTION OUTPUT ;
    USE SIGNAL ;
    PORT
      LAYER M5 ;
        RECT  52.656 0 52.68 0.084 ;
    END
  END q[229]
  PIN q[22]
    DIRECTION OUTPUT ;
    USE SIGNAL ;
    PORT
      LAYER M5 ;
        RECT  13.104 0 13.128 0.084 ;
    END
  END q[22]
  PIN q[230]
    DIRECTION OUTPUT ;
    USE SIGNAL ;
    PORT
      LAYER M5 ;
        RECT  52.848 0 52.872 0.084 ;
    END
  END q[230]
  PIN q[231]
    DIRECTION OUTPUT ;
    USE SIGNAL ;
    PORT
      LAYER M5 ;
        RECT  53.04 0 53.064 0.084 ;
    END
  END q[231]
  PIN q[232]
    DIRECTION OUTPUT ;
    USE SIGNAL ;
    PORT
      LAYER M5 ;
        RECT  53.232 0 53.256 0.084 ;
    END
  END q[232]
  PIN q[233]
    DIRECTION OUTPUT ;
    USE SIGNAL ;
    PORT
      LAYER M5 ;
        RECT  53.424 0 53.448 0.084 ;
    END
  END q[233]
  PIN q[234]
    DIRECTION OUTPUT ;
    USE SIGNAL ;
    PORT
      LAYER M5 ;
        RECT  53.616 0 53.64 0.084 ;
    END
  END q[234]
  PIN q[235]
    DIRECTION OUTPUT ;
    USE SIGNAL ;
    PORT
      LAYER M5 ;
        RECT  53.808 0 53.832 0.084 ;
    END
  END q[235]
  PIN q[236]
    DIRECTION OUTPUT ;
    USE SIGNAL ;
    PORT
      LAYER M5 ;
        RECT  54.192 0 54.216 0.084 ;
    END
  END q[236]
  PIN q[237]
    DIRECTION OUTPUT ;
    USE SIGNAL ;
    PORT
      LAYER M5 ;
        RECT  54 0 54.024 0.084 ;
    END
  END q[237]
  PIN q[238]
    DIRECTION OUTPUT ;
    USE SIGNAL ;
    PORT
      LAYER M5 ;
        RECT  54.384 0 54.408 0.084 ;
    END
  END q[238]
  PIN q[239]
    DIRECTION OUTPUT ;
    USE SIGNAL ;
    PORT
      LAYER M5 ;
        RECT  54.576 0 54.6 0.084 ;
    END
  END q[239]
  PIN q[23]
    DIRECTION OUTPUT ;
    USE SIGNAL ;
    PORT
      LAYER M5 ;
        RECT  12.912 0 12.936 0.084 ;
    END
  END q[23]
  PIN q[240]
    DIRECTION OUTPUT ;
    USE SIGNAL ;
    PORT
      LAYER M5 ;
        RECT  54.768 0 54.792 0.084 ;
    END
  END q[240]
  PIN q[241]
    DIRECTION OUTPUT ;
    USE SIGNAL ;
    PORT
      LAYER M5 ;
        RECT  54.96 0 54.984 0.084 ;
    END
  END q[241]
  PIN q[242]
    DIRECTION OUTPUT ;
    USE SIGNAL ;
    PORT
      LAYER M5 ;
        RECT  55.152 0 55.176 0.084 ;
    END
  END q[242]
  PIN q[243]
    DIRECTION OUTPUT ;
    USE SIGNAL ;
    PORT
      LAYER M5 ;
        RECT  55.344 0 55.368 0.084 ;
    END
  END q[243]
  PIN q[244]
    DIRECTION OUTPUT ;
    USE SIGNAL ;
    PORT
      LAYER M5 ;
        RECT  55.536 0 55.56 0.084 ;
    END
  END q[244]
  PIN q[245]
    DIRECTION OUTPUT ;
    USE SIGNAL ;
    PORT
      LAYER M5 ;
        RECT  55.728 0 55.752 0.084 ;
    END
  END q[245]
  PIN q[246]
    DIRECTION OUTPUT ;
    USE SIGNAL ;
    PORT
      LAYER M5 ;
        RECT  55.92 0 55.944 0.084 ;
    END
  END q[246]
  PIN q[247]
    DIRECTION OUTPUT ;
    USE SIGNAL ;
    PORT
      LAYER M5 ;
        RECT  56.304 0 56.328 0.084 ;
    END
  END q[247]
  PIN q[248]
    DIRECTION OUTPUT ;
    USE SIGNAL ;
    PORT
      LAYER M5 ;
        RECT  56.112 0 56.136 0.084 ;
    END
  END q[248]
  PIN q[249]
    DIRECTION OUTPUT ;
    USE SIGNAL ;
    PORT
      LAYER M5 ;
        RECT  56.496 0 56.52 0.084 ;
    END
  END q[249]
  PIN q[24]
    DIRECTION OUTPUT ;
    USE SIGNAL ;
    PORT
      LAYER M5 ;
        RECT  13.296 0 13.32 0.084 ;
    END
  END q[24]
  PIN q[250]
    DIRECTION OUTPUT ;
    USE SIGNAL ;
    PORT
      LAYER M5 ;
        RECT  57.072 0 57.096 0.084 ;
    END
  END q[250]
  PIN q[251]
    DIRECTION OUTPUT ;
    USE SIGNAL ;
    PORT
      LAYER M5 ;
        RECT  56.688 0 56.712 0.084 ;
    END
  END q[251]
  PIN q[252]
    DIRECTION OUTPUT ;
    USE SIGNAL ;
    PORT
      LAYER M5 ;
        RECT  57.264 0 57.288 0.084 ;
    END
  END q[252]
  PIN q[253]
    DIRECTION OUTPUT ;
    USE SIGNAL ;
    PORT
      LAYER M5 ;
        RECT  56.88 0 56.904 0.084 ;
    END
  END q[253]
  PIN q[254]
    DIRECTION OUTPUT ;
    USE SIGNAL ;
    PORT
      LAYER M5 ;
        RECT  57.456 0 57.48 0.084 ;
    END
  END q[254]
  PIN q[255]
    DIRECTION OUTPUT ;
    USE SIGNAL ;
    PORT
      LAYER M5 ;
        RECT  57.648 0 57.672 0.084 ;
    END
  END q[255]
  PIN q[256]
    DIRECTION OUTPUT ;
    USE SIGNAL ;
    PORT
      LAYER M5 ;
        RECT  57.84 0 57.864 0.084 ;
    END
  END q[256]
  PIN q[257]
    DIRECTION OUTPUT ;
    USE SIGNAL ;
    PORT
      LAYER M5 ;
        RECT  58.032 0 58.056 0.084 ;
    END
  END q[257]
  PIN q[258]
    DIRECTION OUTPUT ;
    USE SIGNAL ;
    PORT
      LAYER M5 ;
        RECT  60.144 0 60.168 0.084 ;
    END
  END q[258]
  PIN q[259]
    DIRECTION OUTPUT ;
    USE SIGNAL ;
    PORT
      LAYER M5 ;
        RECT  60.336 0 60.36 0.084 ;
    END
  END q[259]
  PIN q[25]
    DIRECTION OUTPUT ;
    USE SIGNAL ;
    PORT
      LAYER M5 ;
        RECT  13.488 0 13.512 0.084 ;
    END
  END q[25]
  PIN q[260]
    DIRECTION OUTPUT ;
    USE SIGNAL ;
    PORT
      LAYER M5 ;
        RECT  60.528 0 60.552 0.084 ;
    END
  END q[260]
  PIN q[261]
    DIRECTION OUTPUT ;
    USE SIGNAL ;
    PORT
      LAYER M5 ;
        RECT  60.72 0 60.744 0.084 ;
    END
  END q[261]
  PIN q[262]
    DIRECTION OUTPUT ;
    USE SIGNAL ;
    PORT
      LAYER M5 ;
        RECT  60.912 0 60.936 0.084 ;
    END
  END q[262]
  PIN q[263]
    DIRECTION OUTPUT ;
    USE SIGNAL ;
    PORT
      LAYER M5 ;
        RECT  61.104 0 61.128 0.084 ;
    END
  END q[263]
  PIN q[264]
    DIRECTION OUTPUT ;
    USE SIGNAL ;
    PORT
      LAYER M5 ;
        RECT  61.296 0 61.32 0.084 ;
    END
  END q[264]
  PIN q[265]
    DIRECTION OUTPUT ;
    USE SIGNAL ;
    PORT
      LAYER M5 ;
        RECT  61.488 0 61.512 0.084 ;
    END
  END q[265]
  PIN q[266]
    DIRECTION OUTPUT ;
    USE SIGNAL ;
    PORT
      LAYER M5 ;
        RECT  61.68 0 61.704 0.084 ;
    END
  END q[266]
  PIN q[267]
    DIRECTION OUTPUT ;
    USE SIGNAL ;
    PORT
      LAYER M5 ;
        RECT  61.872 0 61.896 0.084 ;
    END
  END q[267]
  PIN q[268]
    DIRECTION OUTPUT ;
    USE SIGNAL ;
    PORT
      LAYER M5 ;
        RECT  62.064 0 62.088 0.084 ;
    END
  END q[268]
  PIN q[269]
    DIRECTION OUTPUT ;
    USE SIGNAL ;
    PORT
      LAYER M5 ;
        RECT  62.256 0 62.28 0.084 ;
    END
  END q[269]
  PIN q[26]
    DIRECTION OUTPUT ;
    USE SIGNAL ;
    PORT
      LAYER M5 ;
        RECT  13.68 0 13.704 0.084 ;
    END
  END q[26]
  PIN q[270]
    DIRECTION OUTPUT ;
    USE SIGNAL ;
    PORT
      LAYER M5 ;
        RECT  62.448 0 62.472 0.084 ;
    END
  END q[270]
  PIN q[271]
    DIRECTION OUTPUT ;
    USE SIGNAL ;
    PORT
      LAYER M5 ;
        RECT  62.64 0 62.664 0.084 ;
    END
  END q[271]
  PIN q[272]
    DIRECTION OUTPUT ;
    USE SIGNAL ;
    PORT
      LAYER M5 ;
        RECT  62.832 0 62.856 0.084 ;
    END
  END q[272]
  PIN q[273]
    DIRECTION OUTPUT ;
    USE SIGNAL ;
    PORT
      LAYER M5 ;
        RECT  63.024 0 63.048 0.084 ;
    END
  END q[273]
  PIN q[274]
    DIRECTION OUTPUT ;
    USE SIGNAL ;
    PORT
      LAYER M5 ;
        RECT  63.216 0 63.24 0.084 ;
    END
  END q[274]
  PIN q[275]
    DIRECTION OUTPUT ;
    USE SIGNAL ;
    PORT
      LAYER M5 ;
        RECT  63.408 0 63.432 0.084 ;
    END
  END q[275]
  PIN q[276]
    DIRECTION OUTPUT ;
    USE SIGNAL ;
    PORT
      LAYER M5 ;
        RECT  63.6 0 63.624 0.084 ;
    END
  END q[276]
  PIN q[277]
    DIRECTION OUTPUT ;
    USE SIGNAL ;
    PORT
      LAYER M5 ;
        RECT  63.792 0 63.816 0.084 ;
    END
  END q[277]
  PIN q[278]
    DIRECTION OUTPUT ;
    USE SIGNAL ;
    PORT
      LAYER M5 ;
        RECT  63.984 0 64.008 0.084 ;
    END
  END q[278]
  PIN q[279]
    DIRECTION OUTPUT ;
    USE SIGNAL ;
    PORT
      LAYER M5 ;
        RECT  64.176 0 64.2 0.084 ;
    END
  END q[279]
  PIN q[27]
    DIRECTION OUTPUT ;
    USE SIGNAL ;
    PORT
      LAYER M5 ;
        RECT  13.872 0 13.896 0.084 ;
    END
  END q[27]
  PIN q[280]
    DIRECTION OUTPUT ;
    USE SIGNAL ;
    PORT
      LAYER M5 ;
        RECT  64.368 0 64.392 0.084 ;
    END
  END q[280]
  PIN q[281]
    DIRECTION OUTPUT ;
    USE SIGNAL ;
    PORT
      LAYER M5 ;
        RECT  64.56 0 64.584 0.084 ;
    END
  END q[281]
  PIN q[282]
    DIRECTION OUTPUT ;
    USE SIGNAL ;
    PORT
      LAYER M5 ;
        RECT  64.752 0 64.776 0.084 ;
    END
  END q[282]
  PIN q[283]
    DIRECTION OUTPUT ;
    USE SIGNAL ;
    PORT
      LAYER M5 ;
        RECT  64.944 0 64.968 0.084 ;
    END
  END q[283]
  PIN q[284]
    DIRECTION OUTPUT ;
    USE SIGNAL ;
    PORT
      LAYER M5 ;
        RECT  65.136 0 65.16 0.084 ;
    END
  END q[284]
  PIN q[285]
    DIRECTION OUTPUT ;
    USE SIGNAL ;
    PORT
      LAYER M5 ;
        RECT  65.328 0 65.352 0.084 ;
    END
  END q[285]
  PIN q[286]
    DIRECTION OUTPUT ;
    USE SIGNAL ;
    PORT
      LAYER M5 ;
        RECT  65.52 0 65.544 0.084 ;
    END
  END q[286]
  PIN q[287]
    DIRECTION OUTPUT ;
    USE SIGNAL ;
    PORT
      LAYER M5 ;
        RECT  65.712 0 65.736 0.084 ;
    END
  END q[287]
  PIN q[288]
    DIRECTION OUTPUT ;
    USE SIGNAL ;
    PORT
      LAYER M5 ;
        RECT  65.904 0 65.928 0.084 ;
    END
  END q[288]
  PIN q[289]
    DIRECTION OUTPUT ;
    USE SIGNAL ;
    PORT
      LAYER M5 ;
        RECT  66.096 0 66.12 0.084 ;
    END
  END q[289]
  PIN q[28]
    DIRECTION OUTPUT ;
    USE SIGNAL ;
    PORT
      LAYER M5 ;
        RECT  14.064 0 14.088 0.084 ;
    END
  END q[28]
  PIN q[290]
    DIRECTION OUTPUT ;
    USE SIGNAL ;
    PORT
      LAYER M5 ;
        RECT  66.288 0 66.312 0.084 ;
    END
  END q[290]
  PIN q[291]
    DIRECTION OUTPUT ;
    USE SIGNAL ;
    PORT
      LAYER M5 ;
        RECT  66.48 0 66.504 0.084 ;
    END
  END q[291]
  PIN q[292]
    DIRECTION OUTPUT ;
    USE SIGNAL ;
    PORT
      LAYER M5 ;
        RECT  66.672 0 66.696 0.084 ;
    END
  END q[292]
  PIN q[293]
    DIRECTION OUTPUT ;
    USE SIGNAL ;
    PORT
      LAYER M5 ;
        RECT  66.864 0 66.888 0.084 ;
    END
  END q[293]
  PIN q[294]
    DIRECTION OUTPUT ;
    USE SIGNAL ;
    PORT
      LAYER M5 ;
        RECT  67.056 0 67.08 0.084 ;
    END
  END q[294]
  PIN q[295]
    DIRECTION OUTPUT ;
    USE SIGNAL ;
    PORT
      LAYER M5 ;
        RECT  67.248 0 67.272 0.084 ;
    END
  END q[295]
  PIN q[296]
    DIRECTION OUTPUT ;
    USE SIGNAL ;
    PORT
      LAYER M5 ;
        RECT  67.44 0 67.464 0.084 ;
    END
  END q[296]
  PIN q[297]
    DIRECTION OUTPUT ;
    USE SIGNAL ;
    PORT
      LAYER M5 ;
        RECT  68.016 0 68.04 0.084 ;
    END
  END q[297]
  PIN q[298]
    DIRECTION OUTPUT ;
    USE SIGNAL ;
    PORT
      LAYER M5 ;
        RECT  67.632 0 67.656 0.084 ;
    END
  END q[298]
  PIN q[299]
    DIRECTION OUTPUT ;
    USE SIGNAL ;
    PORT
      LAYER M5 ;
        RECT  68.208 0 68.232 0.084 ;
    END
  END q[299]
  PIN q[29]
    DIRECTION OUTPUT ;
    USE SIGNAL ;
    PORT
      LAYER M5 ;
        RECT  14.256 0 14.28 0.084 ;
    END
  END q[29]
  PIN q[2]
    DIRECTION OUTPUT ;
    USE SIGNAL ;
    PORT
      LAYER M5 ;
        RECT  9.264 0 9.288 0.084 ;
    END
  END q[2]
  PIN q[300]
    DIRECTION OUTPUT ;
    USE SIGNAL ;
    PORT
      LAYER M5 ;
        RECT  67.824 0 67.848 0.084 ;
    END
  END q[300]
  PIN q[301]
    DIRECTION OUTPUT ;
    USE SIGNAL ;
    PORT
      LAYER M5 ;
        RECT  68.4 0 68.424 0.084 ;
    END
  END q[301]
  PIN q[302]
    DIRECTION OUTPUT ;
    USE SIGNAL ;
    PORT
      LAYER M5 ;
        RECT  68.592 0 68.616 0.084 ;
    END
  END q[302]
  PIN q[303]
    DIRECTION OUTPUT ;
    USE SIGNAL ;
    PORT
      LAYER M5 ;
        RECT  68.784 0 68.808 0.084 ;
    END
  END q[303]
  PIN q[304]
    DIRECTION OUTPUT ;
    USE SIGNAL ;
    PORT
      LAYER M5 ;
        RECT  68.976 0 69 0.084 ;
    END
  END q[304]
  PIN q[305]
    DIRECTION OUTPUT ;
    USE SIGNAL ;
    PORT
      LAYER M5 ;
        RECT  69.168 0 69.192 0.084 ;
    END
  END q[305]
  PIN q[306]
    DIRECTION OUTPUT ;
    USE SIGNAL ;
    PORT
      LAYER M5 ;
        RECT  69.36 0 69.384 0.084 ;
    END
  END q[306]
  PIN q[307]
    DIRECTION OUTPUT ;
    USE SIGNAL ;
    PORT
      LAYER M5 ;
        RECT  69.552 0 69.576 0.084 ;
    END
  END q[307]
  PIN q[308]
    DIRECTION OUTPUT ;
    USE SIGNAL ;
    PORT
      LAYER M5 ;
        RECT  69.744 0 69.768 0.084 ;
    END
  END q[308]
  PIN q[309]
    DIRECTION OUTPUT ;
    USE SIGNAL ;
    PORT
      LAYER M5 ;
        RECT  69.936 0 69.96 0.084 ;
    END
  END q[309]
  PIN q[30]
    DIRECTION OUTPUT ;
    USE SIGNAL ;
    PORT
      LAYER M5 ;
        RECT  14.448 0 14.472 0.084 ;
    END
  END q[30]
  PIN q[310]
    DIRECTION OUTPUT ;
    USE SIGNAL ;
    PORT
      LAYER M5 ;
        RECT  70.128 0 70.152 0.084 ;
    END
  END q[310]
  PIN q[311]
    DIRECTION OUTPUT ;
    USE SIGNAL ;
    PORT
      LAYER M5 ;
        RECT  70.32 0 70.344 0.084 ;
    END
  END q[311]
  PIN q[312]
    DIRECTION OUTPUT ;
    USE SIGNAL ;
    PORT
      LAYER M5 ;
        RECT  70.512 0 70.536 0.084 ;
    END
  END q[312]
  PIN q[313]
    DIRECTION OUTPUT ;
    USE SIGNAL ;
    PORT
      LAYER M5 ;
        RECT  70.896 0 70.92 0.084 ;
    END
  END q[313]
  PIN q[314]
    DIRECTION OUTPUT ;
    USE SIGNAL ;
    PORT
      LAYER M5 ;
        RECT  70.704 0 70.728 0.084 ;
    END
  END q[314]
  PIN q[315]
    DIRECTION OUTPUT ;
    USE SIGNAL ;
    PORT
      LAYER M5 ;
        RECT  71.088 0 71.112 0.084 ;
    END
  END q[315]
  PIN q[316]
    DIRECTION OUTPUT ;
    USE SIGNAL ;
    PORT
      LAYER M5 ;
        RECT  71.28 0 71.304 0.084 ;
    END
  END q[316]
  PIN q[317]
    DIRECTION OUTPUT ;
    USE SIGNAL ;
    PORT
      LAYER M5 ;
        RECT  71.472 0 71.496 0.084 ;
    END
  END q[317]
  PIN q[318]
    DIRECTION OUTPUT ;
    USE SIGNAL ;
    PORT
      LAYER M5 ;
        RECT  71.664 0 71.688 0.084 ;
    END
  END q[318]
  PIN q[319]
    DIRECTION OUTPUT ;
    USE SIGNAL ;
    PORT
      LAYER M5 ;
        RECT  71.856 0 71.88 0.084 ;
    END
  END q[319]
  PIN q[31]
    DIRECTION OUTPUT ;
    USE SIGNAL ;
    PORT
      LAYER M5 ;
        RECT  14.64 0 14.664 0.084 ;
    END
  END q[31]
  PIN q[320]
    DIRECTION OUTPUT ;
    USE SIGNAL ;
    PORT
      LAYER M5 ;
        RECT  72.048 0 72.072 0.084 ;
    END
  END q[320]
  PIN q[321]
    DIRECTION OUTPUT ;
    USE SIGNAL ;
    PORT
      LAYER M5 ;
        RECT  72.24 0 72.264 0.084 ;
    END
  END q[321]
  PIN q[322]
    DIRECTION OUTPUT ;
    USE SIGNAL ;
    PORT
      LAYER M5 ;
        RECT  72.432 0 72.456 0.084 ;
    END
  END q[322]
  PIN q[323]
    DIRECTION OUTPUT ;
    USE SIGNAL ;
    PORT
      LAYER M5 ;
        RECT  72.624 0 72.648 0.084 ;
    END
  END q[323]
  PIN q[324]
    DIRECTION OUTPUT ;
    USE SIGNAL ;
    PORT
      LAYER M5 ;
        RECT  72.816 0 72.84 0.084 ;
    END
  END q[324]
  PIN q[325]
    DIRECTION OUTPUT ;
    USE SIGNAL ;
    PORT
      LAYER M5 ;
        RECT  73.008 0 73.032 0.084 ;
    END
  END q[325]
  PIN q[326]
    DIRECTION OUTPUT ;
    USE SIGNAL ;
    PORT
      LAYER M5 ;
        RECT  73.2 0 73.224 0.084 ;
    END
  END q[326]
  PIN q[327]
    DIRECTION OUTPUT ;
    USE SIGNAL ;
    PORT
      LAYER M5 ;
        RECT  73.392 0 73.416 0.084 ;
    END
  END q[327]
  PIN q[328]
    DIRECTION OUTPUT ;
    USE SIGNAL ;
    PORT
      LAYER M5 ;
        RECT  73.584 0 73.608 0.084 ;
    END
  END q[328]
  PIN q[329]
    DIRECTION OUTPUT ;
    USE SIGNAL ;
    PORT
      LAYER M5 ;
        RECT  73.776 0 73.8 0.084 ;
    END
  END q[329]
  PIN q[32]
    DIRECTION OUTPUT ;
    USE SIGNAL ;
    PORT
      LAYER M5 ;
        RECT  15.024 0 15.048 0.084 ;
    END
  END q[32]
  PIN q[330]
    DIRECTION OUTPUT ;
    USE SIGNAL ;
    PORT
      LAYER M5 ;
        RECT  73.968 0 73.992 0.084 ;
    END
  END q[330]
  PIN q[331]
    DIRECTION OUTPUT ;
    USE SIGNAL ;
    PORT
      LAYER M5 ;
        RECT  74.16 0 74.184 0.084 ;
    END
  END q[331]
  PIN q[332]
    DIRECTION OUTPUT ;
    USE SIGNAL ;
    PORT
      LAYER M5 ;
        RECT  74.352 0 74.376 0.084 ;
    END
  END q[332]
  PIN q[333]
    DIRECTION OUTPUT ;
    USE SIGNAL ;
    PORT
      LAYER M5 ;
        RECT  74.544 0 74.568 0.084 ;
    END
  END q[333]
  PIN q[334]
    DIRECTION OUTPUT ;
    USE SIGNAL ;
    PORT
      LAYER M5 ;
        RECT  74.736 0 74.76 0.084 ;
    END
  END q[334]
  PIN q[335]
    DIRECTION OUTPUT ;
    USE SIGNAL ;
    PORT
      LAYER M5 ;
        RECT  74.928 0 74.952 0.084 ;
    END
  END q[335]
  PIN q[336]
    DIRECTION OUTPUT ;
    USE SIGNAL ;
    PORT
      LAYER M5 ;
        RECT  75.12 0 75.144 0.084 ;
    END
  END q[336]
  PIN q[337]
    DIRECTION OUTPUT ;
    USE SIGNAL ;
    PORT
      LAYER M5 ;
        RECT  75.312 0 75.336 0.084 ;
    END
  END q[337]
  PIN q[338]
    DIRECTION OUTPUT ;
    USE SIGNAL ;
    PORT
      LAYER M5 ;
        RECT  75.504 0 75.528 0.084 ;
    END
  END q[338]
  PIN q[339]
    DIRECTION OUTPUT ;
    USE SIGNAL ;
    PORT
      LAYER M5 ;
        RECT  75.696 0 75.72 0.084 ;
    END
  END q[339]
  PIN q[33]
    DIRECTION OUTPUT ;
    USE SIGNAL ;
    PORT
      LAYER M5 ;
        RECT  14.832 0 14.856 0.084 ;
    END
  END q[33]
  PIN q[340]
    DIRECTION OUTPUT ;
    USE SIGNAL ;
    PORT
      LAYER M5 ;
        RECT  75.888 0 75.912 0.084 ;
    END
  END q[340]
  PIN q[341]
    DIRECTION OUTPUT ;
    USE SIGNAL ;
    PORT
      LAYER M5 ;
        RECT  76.08 0 76.104 0.084 ;
    END
  END q[341]
  PIN q[342]
    DIRECTION OUTPUT ;
    USE SIGNAL ;
    PORT
      LAYER M5 ;
        RECT  76.272 0 76.296 0.084 ;
    END
  END q[342]
  PIN q[343]
    DIRECTION OUTPUT ;
    USE SIGNAL ;
    PORT
      LAYER M5 ;
        RECT  76.464 0 76.488 0.084 ;
    END
  END q[343]
  PIN q[344]
    DIRECTION OUTPUT ;
    USE SIGNAL ;
    PORT
      LAYER M5 ;
        RECT  76.656 0 76.68 0.084 ;
    END
  END q[344]
  PIN q[345]
    DIRECTION OUTPUT ;
    USE SIGNAL ;
    PORT
      LAYER M5 ;
        RECT  76.848 0 76.872 0.084 ;
    END
  END q[345]
  PIN q[346]
    DIRECTION OUTPUT ;
    USE SIGNAL ;
    PORT
      LAYER M5 ;
        RECT  77.04 0 77.064 0.084 ;
    END
  END q[346]
  PIN q[347]
    DIRECTION OUTPUT ;
    USE SIGNAL ;
    PORT
      LAYER M5 ;
        RECT  77.616 0 77.64 0.084 ;
    END
  END q[347]
  PIN q[348]
    DIRECTION OUTPUT ;
    USE SIGNAL ;
    PORT
      LAYER M5 ;
        RECT  77.232 0 77.256 0.084 ;
    END
  END q[348]
  PIN q[349]
    DIRECTION OUTPUT ;
    USE SIGNAL ;
    PORT
      LAYER M5 ;
        RECT  77.808 0 77.832 0.084 ;
    END
  END q[349]
  PIN q[34]
    DIRECTION OUTPUT ;
    USE SIGNAL ;
    PORT
      LAYER M5 ;
        RECT  15.216 0 15.24 0.084 ;
    END
  END q[34]
  PIN q[350]
    DIRECTION OUTPUT ;
    USE SIGNAL ;
    PORT
      LAYER M5 ;
        RECT  77.424 0 77.448 0.084 ;
    END
  END q[350]
  PIN q[351]
    DIRECTION OUTPUT ;
    USE SIGNAL ;
    PORT
      LAYER M5 ;
        RECT  78 0 78.024 0.084 ;
    END
  END q[351]
  PIN q[352]
    DIRECTION OUTPUT ;
    USE SIGNAL ;
    PORT
      LAYER M5 ;
        RECT  78.192 0 78.216 0.084 ;
    END
  END q[352]
  PIN q[353]
    DIRECTION OUTPUT ;
    USE SIGNAL ;
    PORT
      LAYER M5 ;
        RECT  78.384 0 78.408 0.084 ;
    END
  END q[353]
  PIN q[354]
    DIRECTION OUTPUT ;
    USE SIGNAL ;
    PORT
      LAYER M5 ;
        RECT  78.576 0 78.6 0.084 ;
    END
  END q[354]
  PIN q[355]
    DIRECTION OUTPUT ;
    USE SIGNAL ;
    PORT
      LAYER M5 ;
        RECT  78.768 0 78.792 0.084 ;
    END
  END q[355]
  PIN q[356]
    DIRECTION OUTPUT ;
    USE SIGNAL ;
    PORT
      LAYER M5 ;
        RECT  78.96 0 78.984 0.084 ;
    END
  END q[356]
  PIN q[357]
    DIRECTION OUTPUT ;
    USE SIGNAL ;
    PORT
      LAYER M5 ;
        RECT  79.152 0 79.176 0.084 ;
    END
  END q[357]
  PIN q[358]
    DIRECTION OUTPUT ;
    USE SIGNAL ;
    PORT
      LAYER M5 ;
        RECT  79.344 0 79.368 0.084 ;
    END
  END q[358]
  PIN q[359]
    DIRECTION OUTPUT ;
    USE SIGNAL ;
    PORT
      LAYER M5 ;
        RECT  79.536 0 79.56 0.084 ;
    END
  END q[359]
  PIN q[35]
    DIRECTION OUTPUT ;
    USE SIGNAL ;
    PORT
      LAYER M5 ;
        RECT  15.408 0 15.432 0.084 ;
    END
  END q[35]
  PIN q[360]
    DIRECTION OUTPUT ;
    USE SIGNAL ;
    PORT
      LAYER M5 ;
        RECT  79.728 0 79.752 0.084 ;
    END
  END q[360]
  PIN q[361]
    DIRECTION OUTPUT ;
    USE SIGNAL ;
    PORT
      LAYER M5 ;
        RECT  79.92 0 79.944 0.084 ;
    END
  END q[361]
  PIN q[362]
    DIRECTION OUTPUT ;
    USE SIGNAL ;
    PORT
      LAYER M5 ;
        RECT  80.112 0 80.136 0.084 ;
    END
  END q[362]
  PIN q[363]
    DIRECTION OUTPUT ;
    USE SIGNAL ;
    PORT
      LAYER M5 ;
        RECT  80.496 0 80.52 0.084 ;
    END
  END q[363]
  PIN q[364]
    DIRECTION OUTPUT ;
    USE SIGNAL ;
    PORT
      LAYER M5 ;
        RECT  80.304 0 80.328 0.084 ;
    END
  END q[364]
  PIN q[365]
    DIRECTION OUTPUT ;
    USE SIGNAL ;
    PORT
      LAYER M5 ;
        RECT  80.688 0 80.712 0.084 ;
    END
  END q[365]
  PIN q[366]
    DIRECTION OUTPUT ;
    USE SIGNAL ;
    PORT
      LAYER M5 ;
        RECT  80.88 0 80.904 0.084 ;
    END
  END q[366]
  PIN q[367]
    DIRECTION OUTPUT ;
    USE SIGNAL ;
    PORT
      LAYER M5 ;
        RECT  81.072 0 81.096 0.084 ;
    END
  END q[367]
  PIN q[368]
    DIRECTION OUTPUT ;
    USE SIGNAL ;
    PORT
      LAYER M5 ;
        RECT  81.264 0 81.288 0.084 ;
    END
  END q[368]
  PIN q[369]
    DIRECTION OUTPUT ;
    USE SIGNAL ;
    PORT
      LAYER M5 ;
        RECT  81.456 0 81.48 0.084 ;
    END
  END q[369]
  PIN q[36]
    DIRECTION OUTPUT ;
    USE SIGNAL ;
    PORT
      LAYER M5 ;
        RECT  15.792 0 15.816 0.084 ;
    END
  END q[36]
  PIN q[370]
    DIRECTION OUTPUT ;
    USE SIGNAL ;
    PORT
      LAYER M5 ;
        RECT  81.648 0 81.672 0.084 ;
    END
  END q[370]
  PIN q[371]
    DIRECTION OUTPUT ;
    USE SIGNAL ;
    PORT
      LAYER M5 ;
        RECT  81.84 0 81.864 0.084 ;
    END
  END q[371]
  PIN q[372]
    DIRECTION OUTPUT ;
    USE SIGNAL ;
    PORT
      LAYER M5 ;
        RECT  82.032 0 82.056 0.084 ;
    END
  END q[372]
  PIN q[373]
    DIRECTION OUTPUT ;
    USE SIGNAL ;
    PORT
      LAYER M5 ;
        RECT  82.224 0 82.248 0.084 ;
    END
  END q[373]
  PIN q[374]
    DIRECTION OUTPUT ;
    USE SIGNAL ;
    PORT
      LAYER M5 ;
        RECT  82.416 0 82.44 0.084 ;
    END
  END q[374]
  PIN q[375]
    DIRECTION OUTPUT ;
    USE SIGNAL ;
    PORT
      LAYER M5 ;
        RECT  82.608 0 82.632 0.084 ;
    END
  END q[375]
  PIN q[376]
    DIRECTION OUTPUT ;
    USE SIGNAL ;
    PORT
      LAYER M5 ;
        RECT  82.8 0 82.824 0.084 ;
    END
  END q[376]
  PIN q[377]
    DIRECTION OUTPUT ;
    USE SIGNAL ;
    PORT
      LAYER M5 ;
        RECT  82.992 0 83.016 0.084 ;
    END
  END q[377]
  PIN q[378]
    DIRECTION OUTPUT ;
    USE SIGNAL ;
    PORT
      LAYER M5 ;
        RECT  83.184 0 83.208 0.084 ;
    END
  END q[378]
  PIN q[379]
    DIRECTION OUTPUT ;
    USE SIGNAL ;
    PORT
      LAYER M5 ;
        RECT  83.376 0 83.4 0.084 ;
    END
  END q[379]
  PIN q[37]
    DIRECTION OUTPUT ;
    USE SIGNAL ;
    PORT
      LAYER M5 ;
        RECT  15.6 0 15.624 0.084 ;
    END
  END q[37]
  PIN q[380]
    DIRECTION OUTPUT ;
    USE SIGNAL ;
    PORT
      LAYER M5 ;
        RECT  83.568 0 83.592 0.084 ;
    END
  END q[380]
  PIN q[381]
    DIRECTION OUTPUT ;
    USE SIGNAL ;
    PORT
      LAYER M5 ;
        RECT  83.76 0 83.784 0.084 ;
    END
  END q[381]
  PIN q[382]
    DIRECTION OUTPUT ;
    USE SIGNAL ;
    PORT
      LAYER M5 ;
        RECT  83.952 0 83.976 0.084 ;
    END
  END q[382]
  PIN q[383]
    DIRECTION OUTPUT ;
    USE SIGNAL ;
    PORT
      LAYER M5 ;
        RECT  84.144 0 84.168 0.084 ;
    END
  END q[383]
  PIN q[384]
    DIRECTION OUTPUT ;
    USE SIGNAL ;
    PORT
      LAYER M5 ;
        RECT  84.336 0 84.36 0.084 ;
    END
  END q[384]
  PIN q[385]
    DIRECTION OUTPUT ;
    USE SIGNAL ;
    PORT
      LAYER M5 ;
        RECT  84.528 0 84.552 0.084 ;
    END
  END q[385]
  PIN q[386]
    DIRECTION OUTPUT ;
    USE SIGNAL ;
    PORT
      LAYER M5 ;
        RECT  84.72 0 84.744 0.084 ;
    END
  END q[386]
  PIN q[387]
    DIRECTION OUTPUT ;
    USE SIGNAL ;
    PORT
      LAYER M5 ;
        RECT  84.912 0 84.936 0.084 ;
    END
  END q[387]
  PIN q[388]
    DIRECTION OUTPUT ;
    USE SIGNAL ;
    PORT
      LAYER M5 ;
        RECT  85.104 0 85.128 0.084 ;
    END
  END q[388]
  PIN q[389]
    DIRECTION OUTPUT ;
    USE SIGNAL ;
    PORT
      LAYER M5 ;
        RECT  85.296 0 85.32 0.084 ;
    END
  END q[389]
  PIN q[38]
    DIRECTION OUTPUT ;
    USE SIGNAL ;
    PORT
      LAYER M5 ;
        RECT  15.984 0 16.008 0.084 ;
    END
  END q[38]
  PIN q[390]
    DIRECTION OUTPUT ;
    USE SIGNAL ;
    PORT
      LAYER M5 ;
        RECT  85.488 0 85.512 0.084 ;
    END
  END q[390]
  PIN q[391]
    DIRECTION OUTPUT ;
    USE SIGNAL ;
    PORT
      LAYER M5 ;
        RECT  85.68 0 85.704 0.084 ;
    END
  END q[391]
  PIN q[392]
    DIRECTION OUTPUT ;
    USE SIGNAL ;
    PORT
      LAYER M5 ;
        RECT  85.872 0 85.896 0.084 ;
    END
  END q[392]
  PIN q[393]
    DIRECTION OUTPUT ;
    USE SIGNAL ;
    PORT
      LAYER M5 ;
        RECT  86.064 0 86.088 0.084 ;
    END
  END q[393]
  PIN q[394]
    DIRECTION OUTPUT ;
    USE SIGNAL ;
    PORT
      LAYER M5 ;
        RECT  86.256 0 86.28 0.084 ;
    END
  END q[394]
  PIN q[395]
    DIRECTION OUTPUT ;
    USE SIGNAL ;
    PORT
      LAYER M5 ;
        RECT  86.448 0 86.472 0.084 ;
    END
  END q[395]
  PIN q[396]
    DIRECTION OUTPUT ;
    USE SIGNAL ;
    PORT
      LAYER M5 ;
        RECT  86.64 0 86.664 0.084 ;
    END
  END q[396]
  PIN q[397]
    DIRECTION OUTPUT ;
    USE SIGNAL ;
    PORT
      LAYER M5 ;
        RECT  87.216 0 87.24 0.084 ;
    END
  END q[397]
  PIN q[398]
    DIRECTION OUTPUT ;
    USE SIGNAL ;
    PORT
      LAYER M5 ;
        RECT  86.832 0 86.856 0.084 ;
    END
  END q[398]
  PIN q[399]
    DIRECTION OUTPUT ;
    USE SIGNAL ;
    PORT
      LAYER M5 ;
        RECT  87.408 0 87.432 0.084 ;
    END
  END q[399]
  PIN q[39]
    DIRECTION OUTPUT ;
    USE SIGNAL ;
    PORT
      LAYER M5 ;
        RECT  16.176 0 16.2 0.084 ;
    END
  END q[39]
  PIN q[3]
    DIRECTION OUTPUT ;
    USE SIGNAL ;
    PORT
      LAYER M5 ;
        RECT  8.88 0 8.904 0.084 ;
    END
  END q[3]
  PIN q[400]
    DIRECTION OUTPUT ;
    USE SIGNAL ;
    PORT
      LAYER M5 ;
        RECT  87.024 0 87.048 0.084 ;
    END
  END q[400]
  PIN q[401]
    DIRECTION OUTPUT ;
    USE SIGNAL ;
    PORT
      LAYER M5 ;
        RECT  87.6 0 87.624 0.084 ;
    END
  END q[401]
  PIN q[402]
    DIRECTION OUTPUT ;
    USE SIGNAL ;
    PORT
      LAYER M5 ;
        RECT  87.792 0 87.816 0.084 ;
    END
  END q[402]
  PIN q[403]
    DIRECTION OUTPUT ;
    USE SIGNAL ;
    PORT
      LAYER M5 ;
        RECT  87.984 0 88.008 0.084 ;
    END
  END q[403]
  PIN q[404]
    DIRECTION OUTPUT ;
    USE SIGNAL ;
    PORT
      LAYER M5 ;
        RECT  88.176 0 88.2 0.084 ;
    END
  END q[404]
  PIN q[405]
    DIRECTION OUTPUT ;
    USE SIGNAL ;
    PORT
      LAYER M5 ;
        RECT  88.368 0 88.392 0.084 ;
    END
  END q[405]
  PIN q[406]
    DIRECTION OUTPUT ;
    USE SIGNAL ;
    PORT
      LAYER M5 ;
        RECT  88.56 0 88.584 0.084 ;
    END
  END q[406]
  PIN q[407]
    DIRECTION OUTPUT ;
    USE SIGNAL ;
    PORT
      LAYER M5 ;
        RECT  88.752 0 88.776 0.084 ;
    END
  END q[407]
  PIN q[408]
    DIRECTION OUTPUT ;
    USE SIGNAL ;
    PORT
      LAYER M5 ;
        RECT  88.944 0 88.968 0.084 ;
    END
  END q[408]
  PIN q[409]
    DIRECTION OUTPUT ;
    USE SIGNAL ;
    PORT
      LAYER M5 ;
        RECT  89.136 0 89.16 0.084 ;
    END
  END q[409]
  PIN q[40]
    DIRECTION OUTPUT ;
    USE SIGNAL ;
    PORT
      LAYER M5 ;
        RECT  16.368 0 16.392 0.084 ;
    END
  END q[40]
  PIN q[410]
    DIRECTION OUTPUT ;
    USE SIGNAL ;
    PORT
      LAYER M5 ;
        RECT  89.328 0 89.352 0.084 ;
    END
  END q[410]
  PIN q[411]
    DIRECTION OUTPUT ;
    USE SIGNAL ;
    PORT
      LAYER M5 ;
        RECT  89.52 0 89.544 0.084 ;
    END
  END q[411]
  PIN q[412]
    DIRECTION OUTPUT ;
    USE SIGNAL ;
    PORT
      LAYER M5 ;
        RECT  89.712 0 89.736 0.084 ;
    END
  END q[412]
  PIN q[413]
    DIRECTION OUTPUT ;
    USE SIGNAL ;
    PORT
      LAYER M5 ;
        RECT  90.096 0 90.12 0.084 ;
    END
  END q[413]
  PIN q[414]
    DIRECTION OUTPUT ;
    USE SIGNAL ;
    PORT
      LAYER M5 ;
        RECT  89.904 0 89.928 0.084 ;
    END
  END q[414]
  PIN q[415]
    DIRECTION OUTPUT ;
    USE SIGNAL ;
    PORT
      LAYER M5 ;
        RECT  90.288 0 90.312 0.084 ;
    END
  END q[415]
  PIN q[416]
    DIRECTION OUTPUT ;
    USE SIGNAL ;
    PORT
      LAYER M5 ;
        RECT  90.48 0 90.504 0.084 ;
    END
  END q[416]
  PIN q[417]
    DIRECTION OUTPUT ;
    USE SIGNAL ;
    PORT
      LAYER M5 ;
        RECT  90.672 0 90.696 0.084 ;
    END
  END q[417]
  PIN q[418]
    DIRECTION OUTPUT ;
    USE SIGNAL ;
    PORT
      LAYER M5 ;
        RECT  90.864 0 90.888 0.084 ;
    END
  END q[418]
  PIN q[419]
    DIRECTION OUTPUT ;
    USE SIGNAL ;
    PORT
      LAYER M5 ;
        RECT  91.056 0 91.08 0.084 ;
    END
  END q[419]
  PIN q[41]
    DIRECTION OUTPUT ;
    USE SIGNAL ;
    PORT
      LAYER M5 ;
        RECT  16.56 0 16.584 0.084 ;
    END
  END q[41]
  PIN q[420]
    DIRECTION OUTPUT ;
    USE SIGNAL ;
    PORT
      LAYER M5 ;
        RECT  91.248 0 91.272 0.084 ;
    END
  END q[420]
  PIN q[421]
    DIRECTION OUTPUT ;
    USE SIGNAL ;
    PORT
      LAYER M5 ;
        RECT  91.44 0 91.464 0.084 ;
    END
  END q[421]
  PIN q[422]
    DIRECTION OUTPUT ;
    USE SIGNAL ;
    PORT
      LAYER M5 ;
        RECT  91.632 0 91.656 0.084 ;
    END
  END q[422]
  PIN q[423]
    DIRECTION OUTPUT ;
    USE SIGNAL ;
    PORT
      LAYER M5 ;
        RECT  91.824 0 91.848 0.084 ;
    END
  END q[423]
  PIN q[424]
    DIRECTION OUTPUT ;
    USE SIGNAL ;
    PORT
      LAYER M5 ;
        RECT  92.016 0 92.04 0.084 ;
    END
  END q[424]
  PIN q[425]
    DIRECTION OUTPUT ;
    USE SIGNAL ;
    PORT
      LAYER M5 ;
        RECT  92.208 0 92.232 0.084 ;
    END
  END q[425]
  PIN q[426]
    DIRECTION OUTPUT ;
    USE SIGNAL ;
    PORT
      LAYER M5 ;
        RECT  92.4 0 92.424 0.084 ;
    END
  END q[426]
  PIN q[427]
    DIRECTION OUTPUT ;
    USE SIGNAL ;
    PORT
      LAYER M5 ;
        RECT  92.592 0 92.616 0.084 ;
    END
  END q[427]
  PIN q[428]
    DIRECTION OUTPUT ;
    USE SIGNAL ;
    PORT
      LAYER M5 ;
        RECT  92.784 0 92.808 0.084 ;
    END
  END q[428]
  PIN q[429]
    DIRECTION OUTPUT ;
    USE SIGNAL ;
    PORT
      LAYER M5 ;
        RECT  92.976 0 93 0.084 ;
    END
  END q[429]
  PIN q[42]
    DIRECTION OUTPUT ;
    USE SIGNAL ;
    PORT
      LAYER M5 ;
        RECT  16.944 0 16.968 0.084 ;
    END
  END q[42]
  PIN q[430]
    DIRECTION OUTPUT ;
    USE SIGNAL ;
    PORT
      LAYER M5 ;
        RECT  93.168 0 93.192 0.084 ;
    END
  END q[430]
  PIN q[431]
    DIRECTION OUTPUT ;
    USE SIGNAL ;
    PORT
      LAYER M5 ;
        RECT  93.36 0 93.384 0.084 ;
    END
  END q[431]
  PIN q[432]
    DIRECTION OUTPUT ;
    USE SIGNAL ;
    PORT
      LAYER M5 ;
        RECT  93.552 0 93.576 0.084 ;
    END
  END q[432]
  PIN q[433]
    DIRECTION OUTPUT ;
    USE SIGNAL ;
    PORT
      LAYER M5 ;
        RECT  93.744 0 93.768 0.084 ;
    END
  END q[433]
  PIN q[434]
    DIRECTION OUTPUT ;
    USE SIGNAL ;
    PORT
      LAYER M5 ;
        RECT  93.936 0 93.96 0.084 ;
    END
  END q[434]
  PIN q[435]
    DIRECTION OUTPUT ;
    USE SIGNAL ;
    PORT
      LAYER M5 ;
        RECT  94.128 0 94.152 0.084 ;
    END
  END q[435]
  PIN q[436]
    DIRECTION OUTPUT ;
    USE SIGNAL ;
    PORT
      LAYER M5 ;
        RECT  94.32 0 94.344 0.084 ;
    END
  END q[436]
  PIN q[437]
    DIRECTION OUTPUT ;
    USE SIGNAL ;
    PORT
      LAYER M5 ;
        RECT  94.512 0 94.536 0.084 ;
    END
  END q[437]
  PIN q[438]
    DIRECTION OUTPUT ;
    USE SIGNAL ;
    PORT
      LAYER M5 ;
        RECT  94.704 0 94.728 0.084 ;
    END
  END q[438]
  PIN q[439]
    DIRECTION OUTPUT ;
    USE SIGNAL ;
    PORT
      LAYER M5 ;
        RECT  94.896 0 94.92 0.084 ;
    END
  END q[439]
  PIN q[43]
    DIRECTION OUTPUT ;
    USE SIGNAL ;
    PORT
      LAYER M5 ;
        RECT  16.752 0 16.776 0.084 ;
    END
  END q[43]
  PIN q[440]
    DIRECTION OUTPUT ;
    USE SIGNAL ;
    PORT
      LAYER M5 ;
        RECT  95.088 0 95.112 0.084 ;
    END
  END q[440]
  PIN q[441]
    DIRECTION OUTPUT ;
    USE SIGNAL ;
    PORT
      LAYER M5 ;
        RECT  95.28 0 95.304 0.084 ;
    END
  END q[441]
  PIN q[442]
    DIRECTION OUTPUT ;
    USE SIGNAL ;
    PORT
      LAYER M5 ;
        RECT  95.472 0 95.496 0.084 ;
    END
  END q[442]
  PIN q[443]
    DIRECTION OUTPUT ;
    USE SIGNAL ;
    PORT
      LAYER M5 ;
        RECT  95.664 0 95.688 0.084 ;
    END
  END q[443]
  PIN q[444]
    DIRECTION OUTPUT ;
    USE SIGNAL ;
    PORT
      LAYER M5 ;
        RECT  95.856 0 95.88 0.084 ;
    END
  END q[444]
  PIN q[445]
    DIRECTION OUTPUT ;
    USE SIGNAL ;
    PORT
      LAYER M5 ;
        RECT  96.048 0 96.072 0.084 ;
    END
  END q[445]
  PIN q[446]
    DIRECTION OUTPUT ;
    USE SIGNAL ;
    PORT
      LAYER M5 ;
        RECT  96.24 0 96.264 0.084 ;
    END
  END q[446]
  PIN q[447]
    DIRECTION OUTPUT ;
    USE SIGNAL ;
    PORT
      LAYER M5 ;
        RECT  96.816 0 96.84 0.084 ;
    END
  END q[447]
  PIN q[448]
    DIRECTION OUTPUT ;
    USE SIGNAL ;
    PORT
      LAYER M5 ;
        RECT  96.432 0 96.456 0.084 ;
    END
  END q[448]
  PIN q[449]
    DIRECTION OUTPUT ;
    USE SIGNAL ;
    PORT
      LAYER M5 ;
        RECT  97.008 0 97.032 0.084 ;
    END
  END q[449]
  PIN q[44]
    DIRECTION OUTPUT ;
    USE SIGNAL ;
    PORT
      LAYER M5 ;
        RECT  17.136 0 17.16 0.084 ;
    END
  END q[44]
  PIN q[450]
    DIRECTION OUTPUT ;
    USE SIGNAL ;
    PORT
      LAYER M5 ;
        RECT  96.624 0 96.648 0.084 ;
    END
  END q[450]
  PIN q[451]
    DIRECTION OUTPUT ;
    USE SIGNAL ;
    PORT
      LAYER M5 ;
        RECT  97.2 0 97.224 0.084 ;
    END
  END q[451]
  PIN q[452]
    DIRECTION OUTPUT ;
    USE SIGNAL ;
    PORT
      LAYER M5 ;
        RECT  97.392 0 97.416 0.084 ;
    END
  END q[452]
  PIN q[453]
    DIRECTION OUTPUT ;
    USE SIGNAL ;
    PORT
      LAYER M5 ;
        RECT  97.584 0 97.608 0.084 ;
    END
  END q[453]
  PIN q[454]
    DIRECTION OUTPUT ;
    USE SIGNAL ;
    PORT
      LAYER M5 ;
        RECT  97.776 0 97.8 0.084 ;
    END
  END q[454]
  PIN q[455]
    DIRECTION OUTPUT ;
    USE SIGNAL ;
    PORT
      LAYER M5 ;
        RECT  97.968 0 97.992 0.084 ;
    END
  END q[455]
  PIN q[456]
    DIRECTION OUTPUT ;
    USE SIGNAL ;
    PORT
      LAYER M5 ;
        RECT  98.16 0 98.184 0.084 ;
    END
  END q[456]
  PIN q[457]
    DIRECTION OUTPUT ;
    USE SIGNAL ;
    PORT
      LAYER M5 ;
        RECT  98.352 0 98.376 0.084 ;
    END
  END q[457]
  PIN q[458]
    DIRECTION OUTPUT ;
    USE SIGNAL ;
    PORT
      LAYER M5 ;
        RECT  98.544 0 98.568 0.084 ;
    END
  END q[458]
  PIN q[459]
    DIRECTION OUTPUT ;
    USE SIGNAL ;
    PORT
      LAYER M5 ;
        RECT  98.736 0 98.76 0.084 ;
    END
  END q[459]
  PIN q[45]
    DIRECTION OUTPUT ;
    USE SIGNAL ;
    PORT
      LAYER M5 ;
        RECT  17.328 0 17.352 0.084 ;
    END
  END q[45]
  PIN q[460]
    DIRECTION OUTPUT ;
    USE SIGNAL ;
    PORT
      LAYER M5 ;
        RECT  98.928 0 98.952 0.084 ;
    END
  END q[460]
  PIN q[461]
    DIRECTION OUTPUT ;
    USE SIGNAL ;
    PORT
      LAYER M5 ;
        RECT  99.12 0 99.144 0.084 ;
    END
  END q[461]
  PIN q[462]
    DIRECTION OUTPUT ;
    USE SIGNAL ;
    PORT
      LAYER M5 ;
        RECT  99.312 0 99.336 0.084 ;
    END
  END q[462]
  PIN q[463]
    DIRECTION OUTPUT ;
    USE SIGNAL ;
    PORT
      LAYER M5 ;
        RECT  99.696 0 99.72 0.084 ;
    END
  END q[463]
  PIN q[464]
    DIRECTION OUTPUT ;
    USE SIGNAL ;
    PORT
      LAYER M5 ;
        RECT  99.504 0 99.528 0.084 ;
    END
  END q[464]
  PIN q[465]
    DIRECTION OUTPUT ;
    USE SIGNAL ;
    PORT
      LAYER M5 ;
        RECT  99.888 0 99.912 0.084 ;
    END
  END q[465]
  PIN q[466]
    DIRECTION OUTPUT ;
    USE SIGNAL ;
    PORT
      LAYER M5 ;
        RECT  100.08 0 100.104 0.084 ;
    END
  END q[466]
  PIN q[467]
    DIRECTION OUTPUT ;
    USE SIGNAL ;
    PORT
      LAYER M5 ;
        RECT  100.272 0 100.296 0.084 ;
    END
  END q[467]
  PIN q[468]
    DIRECTION OUTPUT ;
    USE SIGNAL ;
    PORT
      LAYER M5 ;
        RECT  100.464 0 100.488 0.084 ;
    END
  END q[468]
  PIN q[469]
    DIRECTION OUTPUT ;
    USE SIGNAL ;
    PORT
      LAYER M5 ;
        RECT  100.656 0 100.68 0.084 ;
    END
  END q[469]
  PIN q[46]
    DIRECTION OUTPUT ;
    USE SIGNAL ;
    PORT
      LAYER M5 ;
        RECT  17.52 0 17.544 0.084 ;
    END
  END q[46]
  PIN q[470]
    DIRECTION OUTPUT ;
    USE SIGNAL ;
    PORT
      LAYER M5 ;
        RECT  100.848 0 100.872 0.084 ;
    END
  END q[470]
  PIN q[471]
    DIRECTION OUTPUT ;
    USE SIGNAL ;
    PORT
      LAYER M5 ;
        RECT  101.04 0 101.064 0.084 ;
    END
  END q[471]
  PIN q[472]
    DIRECTION OUTPUT ;
    USE SIGNAL ;
    PORT
      LAYER M5 ;
        RECT  101.232 0 101.256 0.084 ;
    END
  END q[472]
  PIN q[473]
    DIRECTION OUTPUT ;
    USE SIGNAL ;
    PORT
      LAYER M5 ;
        RECT  101.424 0 101.448 0.084 ;
    END
  END q[473]
  PIN q[474]
    DIRECTION OUTPUT ;
    USE SIGNAL ;
    PORT
      LAYER M5 ;
        RECT  101.616 0 101.64 0.084 ;
    END
  END q[474]
  PIN q[475]
    DIRECTION OUTPUT ;
    USE SIGNAL ;
    PORT
      LAYER M5 ;
        RECT  101.808 0 101.832 0.084 ;
    END
  END q[475]
  PIN q[476]
    DIRECTION OUTPUT ;
    USE SIGNAL ;
    PORT
      LAYER M5 ;
        RECT  102 0 102.024 0.084 ;
    END
  END q[476]
  PIN q[477]
    DIRECTION OUTPUT ;
    USE SIGNAL ;
    PORT
      LAYER M5 ;
        RECT  102.192 0 102.216 0.084 ;
    END
  END q[477]
  PIN q[478]
    DIRECTION OUTPUT ;
    USE SIGNAL ;
    PORT
      LAYER M5 ;
        RECT  102.384 0 102.408 0.084 ;
    END
  END q[478]
  PIN q[479]
    DIRECTION OUTPUT ;
    USE SIGNAL ;
    PORT
      LAYER M5 ;
        RECT  102.576 0 102.6 0.084 ;
    END
  END q[479]
  PIN q[47]
    DIRECTION OUTPUT ;
    USE SIGNAL ;
    PORT
      LAYER M5 ;
        RECT  17.904 0 17.928 0.084 ;
    END
  END q[47]
  PIN q[480]
    DIRECTION OUTPUT ;
    USE SIGNAL ;
    PORT
      LAYER M5 ;
        RECT  102.768 0 102.792 0.084 ;
    END
  END q[480]
  PIN q[481]
    DIRECTION OUTPUT ;
    USE SIGNAL ;
    PORT
      LAYER M5 ;
        RECT  102.96 0 102.984 0.084 ;
    END
  END q[481]
  PIN q[482]
    DIRECTION OUTPUT ;
    USE SIGNAL ;
    PORT
      LAYER M5 ;
        RECT  103.152 0 103.176 0.084 ;
    END
  END q[482]
  PIN q[483]
    DIRECTION OUTPUT ;
    USE SIGNAL ;
    PORT
      LAYER M5 ;
        RECT  103.344 0 103.368 0.084 ;
    END
  END q[483]
  PIN q[484]
    DIRECTION OUTPUT ;
    USE SIGNAL ;
    PORT
      LAYER M5 ;
        RECT  103.536 0 103.56 0.084 ;
    END
  END q[484]
  PIN q[485]
    DIRECTION OUTPUT ;
    USE SIGNAL ;
    PORT
      LAYER M5 ;
        RECT  103.728 0 103.752 0.084 ;
    END
  END q[485]
  PIN q[486]
    DIRECTION OUTPUT ;
    USE SIGNAL ;
    PORT
      LAYER M5 ;
        RECT  103.92 0 103.944 0.084 ;
    END
  END q[486]
  PIN q[487]
    DIRECTION OUTPUT ;
    USE SIGNAL ;
    PORT
      LAYER M5 ;
        RECT  104.112 0 104.136 0.084 ;
    END
  END q[487]
  PIN q[488]
    DIRECTION OUTPUT ;
    USE SIGNAL ;
    PORT
      LAYER M5 ;
        RECT  104.304 0 104.328 0.084 ;
    END
  END q[488]
  PIN q[489]
    DIRECTION OUTPUT ;
    USE SIGNAL ;
    PORT
      LAYER M5 ;
        RECT  104.496 0 104.52 0.084 ;
    END
  END q[489]
  PIN q[48]
    DIRECTION OUTPUT ;
    USE SIGNAL ;
    PORT
      LAYER M5 ;
        RECT  17.712 0 17.736 0.084 ;
    END
  END q[48]
  PIN q[490]
    DIRECTION OUTPUT ;
    USE SIGNAL ;
    PORT
      LAYER M5 ;
        RECT  104.688 0 104.712 0.084 ;
    END
  END q[490]
  PIN q[491]
    DIRECTION OUTPUT ;
    USE SIGNAL ;
    PORT
      LAYER M5 ;
        RECT  104.88 0 104.904 0.084 ;
    END
  END q[491]
  PIN q[492]
    DIRECTION OUTPUT ;
    USE SIGNAL ;
    PORT
      LAYER M5 ;
        RECT  105.072 0 105.096 0.084 ;
    END
  END q[492]
  PIN q[493]
    DIRECTION OUTPUT ;
    USE SIGNAL ;
    PORT
      LAYER M5 ;
        RECT  105.264 0 105.288 0.084 ;
    END
  END q[493]
  PIN q[494]
    DIRECTION OUTPUT ;
    USE SIGNAL ;
    PORT
      LAYER M5 ;
        RECT  105.456 0 105.48 0.084 ;
    END
  END q[494]
  PIN q[495]
    DIRECTION OUTPUT ;
    USE SIGNAL ;
    PORT
      LAYER M5 ;
        RECT  105.648 0 105.672 0.084 ;
    END
  END q[495]
  PIN q[496]
    DIRECTION OUTPUT ;
    USE SIGNAL ;
    PORT
      LAYER M5 ;
        RECT  105.84 0 105.864 0.084 ;
    END
  END q[496]
  PIN q[497]
    DIRECTION OUTPUT ;
    USE SIGNAL ;
    PORT
      LAYER M5 ;
        RECT  106.416 0 106.44 0.084 ;
    END
  END q[497]
  PIN q[498]
    DIRECTION OUTPUT ;
    USE SIGNAL ;
    PORT
      LAYER M5 ;
        RECT  106.032 0 106.056 0.084 ;
    END
  END q[498]
  PIN q[499]
    DIRECTION OUTPUT ;
    USE SIGNAL ;
    PORT
      LAYER M5 ;
        RECT  106.608 0 106.632 0.084 ;
    END
  END q[499]
  PIN q[49]
    DIRECTION OUTPUT ;
    USE SIGNAL ;
    PORT
      LAYER M5 ;
        RECT  18.096 0 18.12 0.084 ;
    END
  END q[49]
  PIN q[4]
    DIRECTION OUTPUT ;
    USE SIGNAL ;
    PORT
      LAYER M5 ;
        RECT  9.456 0 9.48 0.084 ;
    END
  END q[4]
  PIN q[500]
    DIRECTION OUTPUT ;
    USE SIGNAL ;
    PORT
      LAYER M5 ;
        RECT  106.224 0 106.248 0.084 ;
    END
  END q[500]
  PIN q[501]
    DIRECTION OUTPUT ;
    USE SIGNAL ;
    PORT
      LAYER M5 ;
        RECT  106.8 0 106.824 0.084 ;
    END
  END q[501]
  PIN q[502]
    DIRECTION OUTPUT ;
    USE SIGNAL ;
    PORT
      LAYER M5 ;
        RECT  106.992 0 107.016 0.084 ;
    END
  END q[502]
  PIN q[503]
    DIRECTION OUTPUT ;
    USE SIGNAL ;
    PORT
      LAYER M5 ;
        RECT  107.184 0 107.208 0.084 ;
    END
  END q[503]
  PIN q[504]
    DIRECTION OUTPUT ;
    USE SIGNAL ;
    PORT
      LAYER M5 ;
        RECT  107.376 0 107.4 0.084 ;
    END
  END q[504]
  PIN q[505]
    DIRECTION OUTPUT ;
    USE SIGNAL ;
    PORT
      LAYER M5 ;
        RECT  107.568 0 107.592 0.084 ;
    END
  END q[505]
  PIN q[506]
    DIRECTION OUTPUT ;
    USE SIGNAL ;
    PORT
      LAYER M5 ;
        RECT  107.76 0 107.784 0.084 ;
    END
  END q[506]
  PIN q[507]
    DIRECTION OUTPUT ;
    USE SIGNAL ;
    PORT
      LAYER M5 ;
        RECT  108.144 0 108.168 0.084 ;
    END
  END q[507]
  PIN q[508]
    DIRECTION OUTPUT ;
    USE SIGNAL ;
    PORT
      LAYER M5 ;
        RECT  107.952 0 107.976 0.084 ;
    END
  END q[508]
  PIN q[509]
    DIRECTION OUTPUT ;
    USE SIGNAL ;
    PORT
      LAYER M5 ;
        RECT  108.336 0 108.36 0.084 ;
    END
  END q[509]
  PIN q[50]
    DIRECTION OUTPUT ;
    USE SIGNAL ;
    PORT
      LAYER M5 ;
        RECT  18.672 0 18.696 0.084 ;
    END
  END q[50]
  PIN q[510]
    DIRECTION OUTPUT ;
    USE SIGNAL ;
    PORT
      LAYER M5 ;
        RECT  108.528 0 108.552 0.084 ;
    END
  END q[510]
  PIN q[511]
    DIRECTION OUTPUT ;
    USE SIGNAL ;
    PORT
      LAYER M5 ;
        RECT  108.72 0 108.744 0.084 ;
    END
  END q[511]
  PIN q[512]
    DIRECTION OUTPUT ;
    USE SIGNAL ;
    PORT
      LAYER M5 ;
        RECT  108.912 0 108.936 0.084 ;
    END
  END q[512]
  PIN q[513]
    DIRECTION OUTPUT ;
    USE SIGNAL ;
    PORT
      LAYER M5 ;
        RECT  109.296 0 109.32 0.084 ;
    END
  END q[513]
  PIN q[514]
    DIRECTION OUTPUT ;
    USE SIGNAL ;
    PORT
      LAYER M5 ;
        RECT  109.104 0 109.128 0.084 ;
    END
  END q[514]
  PIN q[515]
    DIRECTION OUTPUT ;
    USE SIGNAL ;
    PORT
      LAYER M5 ;
        RECT  109.488 0 109.512 0.084 ;
    END
  END q[515]
  PIN q[516]
    DIRECTION OUTPUT ;
    USE SIGNAL ;
    PORT
      LAYER M5 ;
        RECT  109.68 0 109.704 0.084 ;
    END
  END q[516]
  PIN q[51]
    DIRECTION OUTPUT ;
    USE SIGNAL ;
    PORT
      LAYER M5 ;
        RECT  18.288 0 18.312 0.084 ;
    END
  END q[51]
  PIN q[52]
    DIRECTION OUTPUT ;
    USE SIGNAL ;
    PORT
      LAYER M5 ;
        RECT  18.864 0 18.888 0.084 ;
    END
  END q[52]
  PIN q[53]
    DIRECTION OUTPUT ;
    USE SIGNAL ;
    PORT
      LAYER M5 ;
        RECT  18.48 0 18.504 0.084 ;
    END
  END q[53]
  PIN q[54]
    DIRECTION OUTPUT ;
    USE SIGNAL ;
    PORT
      LAYER M5 ;
        RECT  19.056 0 19.08 0.084 ;
    END
  END q[54]
  PIN q[55]
    DIRECTION OUTPUT ;
    USE SIGNAL ;
    PORT
      LAYER M5 ;
        RECT  19.248 0 19.272 0.084 ;
    END
  END q[55]
  PIN q[56]
    DIRECTION OUTPUT ;
    USE SIGNAL ;
    PORT
      LAYER M5 ;
        RECT  19.44 0 19.464 0.084 ;
    END
  END q[56]
  PIN q[57]
    DIRECTION OUTPUT ;
    USE SIGNAL ;
    PORT
      LAYER M5 ;
        RECT  19.632 0 19.656 0.084 ;
    END
  END q[57]
  PIN q[58]
    DIRECTION OUTPUT ;
    USE SIGNAL ;
    PORT
      LAYER M5 ;
        RECT  19.824 0 19.848 0.084 ;
    END
  END q[58]
  PIN q[59]
    DIRECTION OUTPUT ;
    USE SIGNAL ;
    PORT
      LAYER M5 ;
        RECT  20.016 0 20.04 0.084 ;
    END
  END q[59]
  PIN q[5]
    DIRECTION OUTPUT ;
    USE SIGNAL ;
    PORT
      LAYER M5 ;
        RECT  9.648 0 9.672 0.084 ;
    END
  END q[5]
  PIN q[60]
    DIRECTION OUTPUT ;
    USE SIGNAL ;
    PORT
      LAYER M5 ;
        RECT  20.208 0 20.232 0.084 ;
    END
  END q[60]
  PIN q[61]
    DIRECTION OUTPUT ;
    USE SIGNAL ;
    PORT
      LAYER M5 ;
        RECT  20.4 0 20.424 0.084 ;
    END
  END q[61]
  PIN q[62]
    DIRECTION OUTPUT ;
    USE SIGNAL ;
    PORT
      LAYER M5 ;
        RECT  20.592 0 20.616 0.084 ;
    END
  END q[62]
  PIN q[63]
    DIRECTION OUTPUT ;
    USE SIGNAL ;
    PORT
      LAYER M5 ;
        RECT  20.784 0 20.808 0.084 ;
    END
  END q[63]
  PIN q[64]
    DIRECTION OUTPUT ;
    USE SIGNAL ;
    PORT
      LAYER M5 ;
        RECT  20.976 0 21 0.084 ;
    END
  END q[64]
  PIN q[65]
    DIRECTION OUTPUT ;
    USE SIGNAL ;
    PORT
      LAYER M5 ;
        RECT  21.168 0 21.192 0.084 ;
    END
  END q[65]
  PIN q[66]
    DIRECTION OUTPUT ;
    USE SIGNAL ;
    PORT
      LAYER M5 ;
        RECT  21.36 0 21.384 0.084 ;
    END
  END q[66]
  PIN q[67]
    DIRECTION OUTPUT ;
    USE SIGNAL ;
    PORT
      LAYER M5 ;
        RECT  21.552 0 21.576 0.084 ;
    END
  END q[67]
  PIN q[68]
    DIRECTION OUTPUT ;
    USE SIGNAL ;
    PORT
      LAYER M5 ;
        RECT  21.744 0 21.768 0.084 ;
    END
  END q[68]
  PIN q[69]
    DIRECTION OUTPUT ;
    USE SIGNAL ;
    PORT
      LAYER M5 ;
        RECT  21.936 0 21.96 0.084 ;
    END
  END q[69]
  PIN q[6]
    DIRECTION OUTPUT ;
    USE SIGNAL ;
    PORT
      LAYER M5 ;
        RECT  9.84 0 9.864 0.084 ;
    END
  END q[6]
  PIN q[70]
    DIRECTION OUTPUT ;
    USE SIGNAL ;
    PORT
      LAYER M5 ;
        RECT  22.128 0 22.152 0.084 ;
    END
  END q[70]
  PIN q[71]
    DIRECTION OUTPUT ;
    USE SIGNAL ;
    PORT
      LAYER M5 ;
        RECT  22.32 0 22.344 0.084 ;
    END
  END q[71]
  PIN q[72]
    DIRECTION OUTPUT ;
    USE SIGNAL ;
    PORT
      LAYER M5 ;
        RECT  22.512 0 22.536 0.084 ;
    END
  END q[72]
  PIN q[73]
    DIRECTION OUTPUT ;
    USE SIGNAL ;
    PORT
      LAYER M5 ;
        RECT  22.704 0 22.728 0.084 ;
    END
  END q[73]
  PIN q[74]
    DIRECTION OUTPUT ;
    USE SIGNAL ;
    PORT
      LAYER M5 ;
        RECT  22.896 0 22.92 0.084 ;
    END
  END q[74]
  PIN q[75]
    DIRECTION OUTPUT ;
    USE SIGNAL ;
    PORT
      LAYER M5 ;
        RECT  23.088 0 23.112 0.084 ;
    END
  END q[75]
  PIN q[76]
    DIRECTION OUTPUT ;
    USE SIGNAL ;
    PORT
      LAYER M5 ;
        RECT  23.28 0 23.304 0.084 ;
    END
  END q[76]
  PIN q[77]
    DIRECTION OUTPUT ;
    USE SIGNAL ;
    PORT
      LAYER M5 ;
        RECT  23.472 0 23.496 0.084 ;
    END
  END q[77]
  PIN q[78]
    DIRECTION OUTPUT ;
    USE SIGNAL ;
    PORT
      LAYER M5 ;
        RECT  23.664 0 23.688 0.084 ;
    END
  END q[78]
  PIN q[79]
    DIRECTION OUTPUT ;
    USE SIGNAL ;
    PORT
      LAYER M5 ;
        RECT  23.856 0 23.88 0.084 ;
    END
  END q[79]
  PIN q[7]
    DIRECTION OUTPUT ;
    USE SIGNAL ;
    PORT
      LAYER M5 ;
        RECT  10.032 0 10.056 0.084 ;
    END
  END q[7]
  PIN q[80]
    DIRECTION OUTPUT ;
    USE SIGNAL ;
    PORT
      LAYER M5 ;
        RECT  24.048 0 24.072 0.084 ;
    END
  END q[80]
  PIN q[81]
    DIRECTION OUTPUT ;
    USE SIGNAL ;
    PORT
      LAYER M5 ;
        RECT  24.24 0 24.264 0.084 ;
    END
  END q[81]
  PIN q[82]
    DIRECTION OUTPUT ;
    USE SIGNAL ;
    PORT
      LAYER M5 ;
        RECT  24.432 0 24.456 0.084 ;
    END
  END q[82]
  PIN q[83]
    DIRECTION OUTPUT ;
    USE SIGNAL ;
    PORT
      LAYER M5 ;
        RECT  24.624 0 24.648 0.084 ;
    END
  END q[83]
  PIN q[84]
    DIRECTION OUTPUT ;
    USE SIGNAL ;
    PORT
      LAYER M5 ;
        RECT  24.816 0 24.84 0.084 ;
    END
  END q[84]
  PIN q[85]
    DIRECTION OUTPUT ;
    USE SIGNAL ;
    PORT
      LAYER M5 ;
        RECT  25.008 0 25.032 0.084 ;
    END
  END q[85]
  PIN q[86]
    DIRECTION OUTPUT ;
    USE SIGNAL ;
    PORT
      LAYER M5 ;
        RECT  25.392 0 25.416 0.084 ;
    END
  END q[86]
  PIN q[87]
    DIRECTION OUTPUT ;
    USE SIGNAL ;
    PORT
      LAYER M5 ;
        RECT  25.2 0 25.224 0.084 ;
    END
  END q[87]
  PIN q[88]
    DIRECTION OUTPUT ;
    USE SIGNAL ;
    PORT
      LAYER M5 ;
        RECT  25.584 0 25.608 0.084 ;
    END
  END q[88]
  PIN q[89]
    DIRECTION OUTPUT ;
    USE SIGNAL ;
    PORT
      LAYER M5 ;
        RECT  25.776 0 25.8 0.084 ;
    END
  END q[89]
  PIN q[8]
    DIRECTION OUTPUT ;
    USE SIGNAL ;
    PORT
      LAYER M5 ;
        RECT  10.224 0 10.248 0.084 ;
    END
  END q[8]
  PIN q[90]
    DIRECTION OUTPUT ;
    USE SIGNAL ;
    PORT
      LAYER M5 ;
        RECT  25.968 0 25.992 0.084 ;
    END
  END q[90]
  PIN q[91]
    DIRECTION OUTPUT ;
    USE SIGNAL ;
    PORT
      LAYER M5 ;
        RECT  26.16 0 26.184 0.084 ;
    END
  END q[91]
  PIN q[92]
    DIRECTION OUTPUT ;
    USE SIGNAL ;
    PORT
      LAYER M5 ;
        RECT  26.352 0 26.376 0.084 ;
    END
  END q[92]
  PIN q[93]
    DIRECTION OUTPUT ;
    USE SIGNAL ;
    PORT
      LAYER M5 ;
        RECT  26.544 0 26.568 0.084 ;
    END
  END q[93]
  PIN q[94]
    DIRECTION OUTPUT ;
    USE SIGNAL ;
    PORT
      LAYER M5 ;
        RECT  26.736 0 26.76 0.084 ;
    END
  END q[94]
  PIN q[95]
    DIRECTION OUTPUT ;
    USE SIGNAL ;
    PORT
      LAYER M5 ;
        RECT  26.928 0 26.952 0.084 ;
    END
  END q[95]
  PIN q[96]
    DIRECTION OUTPUT ;
    USE SIGNAL ;
    PORT
      LAYER M5 ;
        RECT  27.12 0 27.144 0.084 ;
    END
  END q[96]
  PIN q[97]
    DIRECTION OUTPUT ;
    USE SIGNAL ;
    PORT
      LAYER M5 ;
        RECT  27.504 0 27.528 0.084 ;
    END
  END q[97]
  PIN q[98]
    DIRECTION OUTPUT ;
    USE SIGNAL ;
    PORT
      LAYER M5 ;
        RECT  27.312 0 27.336 0.084 ;
    END
  END q[98]
  PIN q[99]
    DIRECTION OUTPUT ;
    USE SIGNAL ;
    PORT
      LAYER M5 ;
        RECT  27.696 0 27.72 0.084 ;
    END
  END q[99]
  PIN q[9]
    DIRECTION OUTPUT ;
    USE SIGNAL ;
    PORT
      LAYER M5 ;
        RECT  10.416 0 10.44 0.084 ;
    END
  END q[9]
  PIN ready
    DIRECTION OUTPUT ;
    USE SIGNAL ;
    PORT
      LAYER M5 ;
        RECT  58.608 0 58.632 0.084 ;
    END
  END ready
  PIN rst_n
    DIRECTION INPUT ;
    USE SIGNAL ;
    PORT
      LAYER M5 ;
        RECT  58.416 0 58.44 0.084 ;
    END
  END rst_n
  PIN strap_k[0]
    DIRECTION INPUT ;
    USE SIGNAL ;
    PORT
      LAYER M5 ;
        RECT  58.992 0 59.016 0.084 ;
    END
  END strap_k[0]
  PIN strap_k[1]
    DIRECTION INPUT ;
    USE SIGNAL ;
    PORT
      LAYER M5 ;
        RECT  59.184 0 59.208 0.084 ;
    END
  END strap_k[1]
  PIN strap_k[2]
    DIRECTION INPUT ;
    USE SIGNAL ;
    PORT
      LAYER M5 ;
        RECT  59.376 0 59.4 0.084 ;
    END
  END strap_k[2]
  PIN strap_k[3]
    DIRECTION INPUT ;
    USE SIGNAL ;
    PORT
      LAYER M5 ;
        RECT  59.568 0 59.592 0.084 ;
    END
  END strap_k[3]
  PIN strap_k[4]
    DIRECTION INPUT ;
    USE SIGNAL ;
    PORT
      LAYER M5 ;
        RECT  59.76 0 59.784 0.084 ;
    END
  END strap_k[4]
  PIN strap_k[5]
    DIRECTION INPUT ;
    USE SIGNAL ;
    PORT
      LAYER M5 ;
        RECT  59.952 0 59.976 0.084 ;
    END
  END strap_k[5]
  PIN t_rst_n
    DIRECTION INPUT ;
    USE SIGNAL ;
    PORT
      LAYER M5 ;
        RECT  59.184 43.548 59.208 43.632 ;
    END
  END t_rst_n
  PIN VDD
    DIRECTION INOUT ;
    USE POWER ;
    PORT
      LAYER M5 ;
        RECT  110.196 4.311 110.316 39.173 ;
        RECT  105.876 4.311 105.996 39.173 ;
        RECT  101.556 4.311 101.676 39.173 ;
        RECT  97.236 4.311 97.356 39.173 ;
        RECT  92.916 4.311 93.036 39.173 ;
        RECT  88.596 4.311 88.716 39.173 ;
        RECT  84.276 4.311 84.396 39.173 ;
        RECT  79.956 4.311 80.076 39.173 ;
        RECT  75.636 4.311 75.756 39.173 ;
        RECT  71.316 4.311 71.436 39.173 ;
        RECT  66.996 4.311 67.116 39.173 ;
        RECT  62.676 4.311 62.796 39.173 ;
        RECT  58.356 4.311 58.476 39.173 ;
        RECT  54.036 4.311 54.156 39.173 ;
        RECT  49.716 4.311 49.836 39.173 ;
        RECT  45.396 4.311 45.516 39.173 ;
        RECT  41.076 4.311 41.196 39.173 ;
        RECT  36.756 4.311 36.876 39.173 ;
        RECT  32.436 4.311 32.556 39.173 ;
        RECT  28.116 4.311 28.236 39.173 ;
        RECT  23.796 4.311 23.916 39.173 ;
        RECT  19.476 4.311 19.596 39.173 ;
        RECT  15.156 4.311 15.276 39.173 ;
        RECT  10.836 4.311 10.956 39.173 ;
        RECT  6.516 4.311 6.636 39.173 ;
    END
  END VDD
  PIN VSS
    DIRECTION INOUT ;
    USE GROUND ;
    PORT
      LAYER M5 ;
        RECT  110.004 4.297 110.124 39.159 ;
        RECT  105.684 4.297 105.804 39.159 ;
        RECT  101.364 4.297 101.484 39.159 ;
        RECT  97.044 4.297 97.164 39.159 ;
        RECT  92.724 4.297 92.844 39.159 ;
        RECT  88.404 4.297 88.524 39.159 ;
        RECT  84.084 4.297 84.204 39.159 ;
        RECT  79.764 4.297 79.884 39.159 ;
        RECT  75.444 4.297 75.564 39.159 ;
        RECT  71.124 4.297 71.244 39.159 ;
        RECT  66.804 4.297 66.924 39.159 ;
        RECT  62.484 4.297 62.604 39.159 ;
        RECT  58.164 4.297 58.284 39.159 ;
        RECT  53.844 4.297 53.964 39.159 ;
        RECT  49.524 4.297 49.644 39.159 ;
        RECT  45.204 4.297 45.324 39.159 ;
        RECT  40.884 4.297 41.004 39.159 ;
        RECT  36.564 4.297 36.684 39.159 ;
        RECT  32.244 4.297 32.364 39.159 ;
        RECT  27.924 4.297 28.044 39.159 ;
        RECT  23.604 4.297 23.724 39.159 ;
        RECT  19.284 4.297 19.404 39.159 ;
        RECT  14.964 4.297 15.084 39.159 ;
        RECT  10.644 4.297 10.764 39.159 ;
        RECT  6.324 4.297 6.444 39.159 ;
    END
  END VSS
  OBS
    LAYER RVTN ;
     RECT  4.32 0 114.048 43.632 ;
    LAYER RVTP ;
     RECT  4.32 0 114.048 43.632 ;
    LAYER M1 ;
     RECT  4.32 0 114.048 43.632 ;
    LAYER M2 ;
     RECT  4.32 0 114.048 43.632 ;
    LAYER M3 ;
     RECT  4.32 0 114.048 43.632 ;
    LAYER M4 ;
     RECT  4.32 0 114.048 43.632 ;
    LAYER M5 ;
     RECT  4.32 0 114.048 43.632 ;
  END
END sle_cland_w517_n_200
END LIBRARY
